VERSION 5.7 ;
  NOWIREEXTENSIONATPIN ON ;
  DIVIDERCHAR "/" ;
  BUSBITCHARS "[]" ;
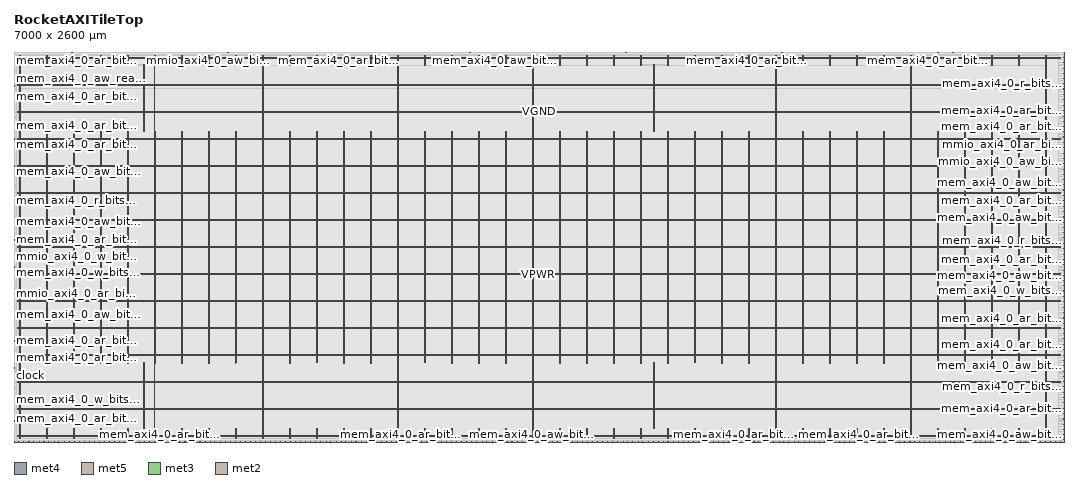
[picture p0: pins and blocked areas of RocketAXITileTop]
MACRO RocketAXITileTop
  CLASS BLOCK ;
  FOREIGN RocketAXITileTop ;
  ORIGIN 0.000 0.000 ;
  SIZE 7000.000 BY 2600.000 ;
  PIN VGND
    DIRECTION INOUT ;
    USE GROUND ;
    PORT
      LAYER met4 ;
        RECT 39.060 21.520 40.660 2578.800 ;
    END
    PORT
      LAYER met4 ;
        RECT 219.060 21.520 220.660 90.020 ;
    END
    PORT
      LAYER met4 ;
        RECT 219.060 527.140 220.660 2072.400 ;
    END
    PORT
      LAYER met4 ;
        RECT 219.060 2509.520 220.660 2578.800 ;
    END
    PORT
      LAYER met4 ;
        RECT 399.060 21.520 400.660 90.020 ;
    END
    PORT
      LAYER met4 ;
        RECT 399.060 526.520 400.660 2073.020 ;
    END
    PORT
      LAYER met4 ;
        RECT 399.060 2509.520 400.660 2578.800 ;
    END
    PORT
      LAYER met4 ;
        RECT 579.060 21.520 580.660 89.400 ;
    END
    PORT
      LAYER met4 ;
        RECT 579.060 527.140 580.660 2072.400 ;
    END
    PORT
      LAYER met4 ;
        RECT 579.060 2510.140 580.660 2578.800 ;
    END
    PORT
      LAYER met4 ;
        RECT 759.060 21.520 760.660 90.020 ;
    END
    PORT
      LAYER met4 ;
        RECT 759.060 526.520 760.660 2073.020 ;
    END
    PORT
      LAYER met4 ;
        RECT 759.060 2509.520 760.660 2578.800 ;
    END
    PORT
      LAYER met4 ;
        RECT 939.060 21.520 940.660 90.020 ;
    END
    PORT
      LAYER met4 ;
        RECT 939.060 526.520 940.660 2073.020 ;
    END
    PORT
      LAYER met4 ;
        RECT 939.060 2509.520 940.660 2578.800 ;
    END
    PORT
      LAYER met4 ;
        RECT 1119.060 21.520 1120.660 90.020 ;
    END
    PORT
      LAYER met4 ;
        RECT 1119.060 526.520 1120.660 2073.020 ;
    END
    PORT
      LAYER met4 ;
        RECT 1119.060 2509.520 1120.660 2578.800 ;
    END
    PORT
      LAYER met4 ;
        RECT 1299.060 21.520 1300.660 90.020 ;
    END
    PORT
      LAYER met4 ;
        RECT 1299.060 526.520 1300.660 2073.020 ;
    END
    PORT
      LAYER met4 ;
        RECT 1299.060 2509.520 1300.660 2578.800 ;
    END
    PORT
      LAYER met4 ;
        RECT 1479.060 21.520 1480.660 89.400 ;
    END
    PORT
      LAYER met4 ;
        RECT 1479.060 527.140 1480.660 2072.400 ;
    END
    PORT
      LAYER met4 ;
        RECT 1479.060 2510.140 1480.660 2578.800 ;
    END
    PORT
      LAYER met4 ;
        RECT 1659.060 21.520 1660.660 2578.800 ;
    END
    PORT
      LAYER met4 ;
        RECT 1839.060 21.520 1840.660 90.020 ;
    END
    PORT
      LAYER met4 ;
        RECT 1839.060 526.520 1840.660 2073.020 ;
    END
    PORT
      LAYER met4 ;
        RECT 1839.060 2509.520 1840.660 2578.800 ;
    END
    PORT
      LAYER met4 ;
        RECT 2019.060 21.520 2020.660 90.020 ;
    END
    PORT
      LAYER met4 ;
        RECT 2019.060 527.140 2020.660 2072.400 ;
    END
    PORT
      LAYER met4 ;
        RECT 2019.060 2509.520 2020.660 2578.800 ;
    END
    PORT
      LAYER met4 ;
        RECT 2199.060 21.520 2200.660 90.020 ;
    END
    PORT
      LAYER met4 ;
        RECT 2199.060 526.520 2200.660 2073.020 ;
    END
    PORT
      LAYER met4 ;
        RECT 2199.060 2509.520 2200.660 2578.800 ;
    END
    PORT
      LAYER met4 ;
        RECT 2379.060 21.520 2380.660 90.020 ;
    END
    PORT
      LAYER met4 ;
        RECT 2379.060 526.520 2380.660 2073.020 ;
    END
    PORT
      LAYER met4 ;
        RECT 2379.060 2509.520 2380.660 2578.800 ;
    END
    PORT
      LAYER met4 ;
        RECT 2559.060 21.520 2560.660 2578.800 ;
    END
    PORT
      LAYER met4 ;
        RECT 2739.060 21.520 2740.660 90.020 ;
    END
    PORT
      LAYER met4 ;
        RECT 2739.060 527.140 2740.660 2072.400 ;
    END
    PORT
      LAYER met4 ;
        RECT 2739.060 2509.520 2740.660 2578.800 ;
    END
    PORT
      LAYER met4 ;
        RECT 2919.060 21.520 2920.660 90.020 ;
    END
    PORT
      LAYER met4 ;
        RECT 2919.060 526.520 2920.660 2073.020 ;
    END
    PORT
      LAYER met4 ;
        RECT 2919.060 2509.520 2920.660 2578.800 ;
    END
    PORT
      LAYER met4 ;
        RECT 3099.060 21.520 3100.660 90.020 ;
    END
    PORT
      LAYER met4 ;
        RECT 3099.060 526.520 3100.660 2073.020 ;
    END
    PORT
      LAYER met4 ;
        RECT 3099.060 2509.520 3100.660 2578.800 ;
    END
    PORT
      LAYER met4 ;
        RECT 3279.060 21.520 3280.660 90.020 ;
    END
    PORT
      LAYER met4 ;
        RECT 3279.060 526.520 3280.660 2073.020 ;
    END
    PORT
      LAYER met4 ;
        RECT 3279.060 2509.520 3280.660 2578.800 ;
    END
    PORT
      LAYER met4 ;
        RECT 3459.060 21.520 3460.660 2578.800 ;
    END
    PORT
      LAYER met4 ;
        RECT 3639.060 21.520 3640.660 90.020 ;
    END
    PORT
      LAYER met4 ;
        RECT 3639.060 526.520 3640.660 2073.020 ;
    END
    PORT
      LAYER met4 ;
        RECT 3639.060 2509.520 3640.660 2578.800 ;
    END
    PORT
      LAYER met4 ;
        RECT 3819.060 21.520 3820.660 89.400 ;
    END
    PORT
      LAYER met4 ;
        RECT 3819.060 526.520 3820.660 2073.020 ;
    END
    PORT
      LAYER met4 ;
        RECT 3819.060 2510.140 3820.660 2578.800 ;
    END
    PORT
      LAYER met4 ;
        RECT 3999.060 21.520 4000.660 90.020 ;
    END
    PORT
      LAYER met4 ;
        RECT 3999.060 526.520 4000.660 2073.020 ;
    END
    PORT
      LAYER met4 ;
        RECT 3999.060 2509.520 4000.660 2578.800 ;
    END
    PORT
      LAYER met4 ;
        RECT 4179.060 21.520 4180.660 90.020 ;
    END
    PORT
      LAYER met4 ;
        RECT 4179.060 526.520 4180.660 2073.020 ;
    END
    PORT
      LAYER met4 ;
        RECT 4179.060 2509.520 4180.660 2578.800 ;
    END
    PORT
      LAYER met4 ;
        RECT 4359.060 21.520 4360.660 90.020 ;
    END
    PORT
      LAYER met4 ;
        RECT 4359.060 526.520 4360.660 2073.020 ;
    END
    PORT
      LAYER met4 ;
        RECT 4359.060 2509.520 4360.660 2578.800 ;
    END
    PORT
      LAYER met4 ;
        RECT 4539.060 21.520 4540.660 90.020 ;
    END
    PORT
      LAYER met4 ;
        RECT 4539.060 527.140 4540.660 2072.400 ;
    END
    PORT
      LAYER met4 ;
        RECT 4539.060 2509.520 4540.660 2578.800 ;
    END
    PORT
      LAYER met4 ;
        RECT 4719.060 21.520 4720.660 90.020 ;
    END
    PORT
      LAYER met4 ;
        RECT 4719.060 526.520 4720.660 2073.020 ;
    END
    PORT
      LAYER met4 ;
        RECT 4719.060 2509.520 4720.660 2578.800 ;
    END
    PORT
      LAYER met4 ;
        RECT 4899.060 21.520 4900.660 90.020 ;
    END
    PORT
      LAYER met4 ;
        RECT 4899.060 526.520 4900.660 2073.020 ;
    END
    PORT
      LAYER met4 ;
        RECT 4899.060 2509.520 4900.660 2578.800 ;
    END
    PORT
      LAYER met4 ;
        RECT 5079.060 21.520 5080.660 2578.800 ;
    END
    PORT
      LAYER met4 ;
        RECT 5259.060 21.520 5260.660 90.020 ;
    END
    PORT
      LAYER met4 ;
        RECT 5259.060 526.520 5260.660 2073.020 ;
    END
    PORT
      LAYER met4 ;
        RECT 5259.060 2509.520 5260.660 2578.800 ;
    END
    PORT
      LAYER met4 ;
        RECT 5439.060 21.520 5440.660 90.020 ;
    END
    PORT
      LAYER met4 ;
        RECT 5439.060 526.520 5440.660 2073.020 ;
    END
    PORT
      LAYER met4 ;
        RECT 5439.060 2509.520 5440.660 2578.800 ;
    END
    PORT
      LAYER met4 ;
        RECT 5619.060 21.520 5620.660 90.020 ;
    END
    PORT
      LAYER met4 ;
        RECT 5619.060 526.520 5620.660 2073.020 ;
    END
    PORT
      LAYER met4 ;
        RECT 5619.060 2509.520 5620.660 2578.800 ;
    END
    PORT
      LAYER met4 ;
        RECT 5799.060 21.520 5800.660 89.400 ;
    END
    PORT
      LAYER met4 ;
        RECT 5799.060 526.520 5800.660 2073.020 ;
    END
    PORT
      LAYER met4 ;
        RECT 5799.060 2510.140 5800.660 2578.800 ;
    END
    PORT
      LAYER met4 ;
        RECT 5979.060 21.520 5980.660 2578.800 ;
    END
    PORT
      LAYER met4 ;
        RECT 6159.060 21.520 6160.660 90.020 ;
    END
    PORT
      LAYER met4 ;
        RECT 6159.060 527.140 6160.660 2072.400 ;
    END
    PORT
      LAYER met4 ;
        RECT 6159.060 2509.520 6160.660 2578.800 ;
    END
    PORT
      LAYER met4 ;
        RECT 6339.060 21.520 6340.660 90.020 ;
    END
    PORT
      LAYER met4 ;
        RECT 6339.060 527.140 6340.660 2072.400 ;
    END
    PORT
      LAYER met4 ;
        RECT 6339.060 2509.520 6340.660 2578.800 ;
    END
    PORT
      LAYER met4 ;
        RECT 6519.060 21.520 6520.660 90.020 ;
    END
    PORT
      LAYER met4 ;
        RECT 6519.060 526.520 6520.660 2073.020 ;
    END
    PORT
      LAYER met4 ;
        RECT 6519.060 2509.520 6520.660 2578.800 ;
    END
    PORT
      LAYER met4 ;
        RECT 6699.060 21.520 6700.660 90.020 ;
    END
    PORT
      LAYER met4 ;
        RECT 6699.060 526.520 6700.660 2073.020 ;
    END
    PORT
      LAYER met4 ;
        RECT 6699.060 2509.520 6700.660 2578.800 ;
    END
    PORT
      LAYER met4 ;
        RECT 6879.060 21.520 6880.660 2578.800 ;
    END
    PORT
      LAYER met5 ;
        RECT 20.000 40.910 6979.820 42.510 ;
    END
    PORT
      LAYER met5 ;
        RECT 20.000 220.910 6979.820 222.510 ;
    END
    PORT
      LAYER met5 ;
        RECT 20.000 400.910 6979.820 402.510 ;
    END
    PORT
      LAYER met5 ;
        RECT 20.000 580.910 6979.820 582.510 ;
    END
    PORT
      LAYER met5 ;
        RECT 20.000 760.910 6979.820 762.510 ;
    END
    PORT
      LAYER met5 ;
        RECT 20.000 940.910 6979.820 942.510 ;
    END
    PORT
      LAYER met5 ;
        RECT 20.000 1120.910 6979.820 1122.510 ;
    END
    PORT
      LAYER met5 ;
        RECT 20.000 1300.910 6979.820 1302.510 ;
    END
    PORT
      LAYER met5 ;
        RECT 20.000 1480.910 6979.820 1482.510 ;
    END
    PORT
      LAYER met5 ;
        RECT 20.000 1660.910 6979.820 1662.510 ;
    END
    PORT
      LAYER met5 ;
        RECT 20.000 1840.910 6979.820 1842.510 ;
    END
    PORT
      LAYER met5 ;
        RECT 20.000 2020.910 6979.820 2022.510 ;
    END
    PORT
      LAYER met5 ;
        RECT 20.000 2200.910 6979.820 2202.510 ;
    END
    PORT
      LAYER met5 ;
        RECT 20.000 2380.910 6979.820 2382.510 ;
    END
    PORT
      LAYER met5 ;
        RECT 20.000 2560.910 6979.820 2562.510 ;
    END
    PORT
      LAYER met4 ;
        RECT 865.380 86.800 866.980 527.920 ;
    END
    PORT
      LAYER met4 ;
        RECT 4267.540 2069.680 4269.140 2513.520 ;
    END
    PORT
      LAYER met4 ;
        RECT 865.380 2072.400 866.980 2513.520 ;
    END
    PORT
      LAYER met4 ;
        RECT 4267.540 86.800 4269.140 530.640 ;
    END
  END VGND
  PIN VPWR
    DIRECTION INOUT ;
    USE POWER ;
    PORT
      LAYER met4 ;
        RECT 35.760 21.520 37.360 2578.800 ;
    END
    PORT
      LAYER met4 ;
        RECT 215.760 21.520 217.360 90.020 ;
    END
    PORT
      LAYER met4 ;
        RECT 215.760 527.140 217.360 2072.400 ;
    END
    PORT
      LAYER met4 ;
        RECT 215.760 2509.520 217.360 2578.800 ;
    END
    PORT
      LAYER met4 ;
        RECT 395.760 21.520 397.360 90.020 ;
    END
    PORT
      LAYER met4 ;
        RECT 395.760 527.140 397.360 2072.400 ;
    END
    PORT
      LAYER met4 ;
        RECT 395.760 2509.520 397.360 2578.800 ;
    END
    PORT
      LAYER met4 ;
        RECT 575.760 21.520 577.360 90.020 ;
    END
    PORT
      LAYER met4 ;
        RECT 575.760 526.520 577.360 2073.020 ;
    END
    PORT
      LAYER met4 ;
        RECT 575.760 2509.520 577.360 2578.800 ;
    END
    PORT
      LAYER met4 ;
        RECT 755.760 21.520 757.360 90.020 ;
    END
    PORT
      LAYER met4 ;
        RECT 755.760 526.520 757.360 2073.020 ;
    END
    PORT
      LAYER met4 ;
        RECT 755.760 2509.520 757.360 2578.800 ;
    END
    PORT
      LAYER met4 ;
        RECT 935.760 21.520 937.360 2578.800 ;
    END
    PORT
      LAYER met4 ;
        RECT 1115.760 21.520 1117.360 89.400 ;
    END
    PORT
      LAYER met4 ;
        RECT 1115.760 527.140 1117.360 2072.400 ;
    END
    PORT
      LAYER met4 ;
        RECT 1115.760 2510.140 1117.360 2578.800 ;
    END
    PORT
      LAYER met4 ;
        RECT 1295.760 21.520 1297.360 90.020 ;
    END
    PORT
      LAYER met4 ;
        RECT 1295.760 526.520 1297.360 2073.020 ;
    END
    PORT
      LAYER met4 ;
        RECT 1295.760 2509.520 1297.360 2578.800 ;
    END
    PORT
      LAYER met4 ;
        RECT 1475.760 21.520 1477.360 90.020 ;
    END
    PORT
      LAYER met4 ;
        RECT 1475.760 526.520 1477.360 2073.020 ;
    END
    PORT
      LAYER met4 ;
        RECT 1475.760 2509.520 1477.360 2578.800 ;
    END
    PORT
      LAYER met4 ;
        RECT 1655.760 21.520 1657.360 2578.800 ;
    END
    PORT
      LAYER met4 ;
        RECT 1835.760 21.520 1837.360 90.020 ;
    END
    PORT
      LAYER met4 ;
        RECT 1835.760 526.520 1837.360 2073.020 ;
    END
    PORT
      LAYER met4 ;
        RECT 1835.760 2509.520 1837.360 2578.800 ;
    END
    PORT
      LAYER met4 ;
        RECT 2015.760 21.520 2017.360 89.400 ;
    END
    PORT
      LAYER met4 ;
        RECT 2015.760 527.140 2017.360 2072.400 ;
    END
    PORT
      LAYER met4 ;
        RECT 2015.760 2510.140 2017.360 2578.800 ;
    END
    PORT
      LAYER met4 ;
        RECT 2195.760 21.520 2197.360 90.020 ;
    END
    PORT
      LAYER met4 ;
        RECT 2195.760 526.520 2197.360 2073.020 ;
    END
    PORT
      LAYER met4 ;
        RECT 2195.760 2509.520 2197.360 2578.800 ;
    END
    PORT
      LAYER met4 ;
        RECT 2375.760 21.520 2377.360 90.020 ;
    END
    PORT
      LAYER met4 ;
        RECT 2375.760 526.520 2377.360 2073.020 ;
    END
    PORT
      LAYER met4 ;
        RECT 2375.760 2509.520 2377.360 2578.800 ;
    END
    PORT
      LAYER met4 ;
        RECT 2555.760 21.520 2557.360 2578.800 ;
    END
    PORT
      LAYER met4 ;
        RECT 2735.760 21.520 2737.360 90.020 ;
    END
    PORT
      LAYER met4 ;
        RECT 2735.760 527.140 2737.360 2072.400 ;
    END
    PORT
      LAYER met4 ;
        RECT 2735.760 2509.520 2737.360 2578.800 ;
    END
    PORT
      LAYER met4 ;
        RECT 2915.760 21.520 2917.360 89.400 ;
    END
    PORT
      LAYER met4 ;
        RECT 2915.760 527.140 2917.360 2072.400 ;
    END
    PORT
      LAYER met4 ;
        RECT 2915.760 2510.140 2917.360 2578.800 ;
    END
    PORT
      LAYER met4 ;
        RECT 3095.760 21.520 3097.360 90.020 ;
    END
    PORT
      LAYER met4 ;
        RECT 3095.760 526.520 3097.360 2073.020 ;
    END
    PORT
      LAYER met4 ;
        RECT 3095.760 2509.520 3097.360 2578.800 ;
    END
    PORT
      LAYER met4 ;
        RECT 3275.760 21.520 3277.360 90.020 ;
    END
    PORT
      LAYER met4 ;
        RECT 3275.760 526.520 3277.360 2073.020 ;
    END
    PORT
      LAYER met4 ;
        RECT 3275.760 2509.520 3277.360 2578.800 ;
    END
    PORT
      LAYER met4 ;
        RECT 3455.760 21.520 3457.360 2578.800 ;
    END
    PORT
      LAYER met4 ;
        RECT 3635.760 21.520 3637.360 90.020 ;
    END
    PORT
      LAYER met4 ;
        RECT 3635.760 526.520 3637.360 2073.020 ;
    END
    PORT
      LAYER met4 ;
        RECT 3635.760 2509.520 3637.360 2578.800 ;
    END
    PORT
      LAYER met4 ;
        RECT 3815.760 21.520 3817.360 90.020 ;
    END
    PORT
      LAYER met4 ;
        RECT 3815.760 527.140 3817.360 2072.400 ;
    END
    PORT
      LAYER met4 ;
        RECT 3815.760 2509.520 3817.360 2578.800 ;
    END
    PORT
      LAYER met4 ;
        RECT 3995.760 21.520 3997.360 90.020 ;
    END
    PORT
      LAYER met4 ;
        RECT 3995.760 526.520 3997.360 2073.020 ;
    END
    PORT
      LAYER met4 ;
        RECT 3995.760 2509.520 3997.360 2578.800 ;
    END
    PORT
      LAYER met4 ;
        RECT 4175.760 21.520 4177.360 90.020 ;
    END
    PORT
      LAYER met4 ;
        RECT 4175.760 526.520 4177.360 2073.020 ;
    END
    PORT
      LAYER met4 ;
        RECT 4175.760 2509.520 4177.360 2578.800 ;
    END
    PORT
      LAYER met4 ;
        RECT 4355.760 21.520 4357.360 90.020 ;
    END
    PORT
      LAYER met4 ;
        RECT 4355.760 526.520 4357.360 2073.020 ;
    END
    PORT
      LAYER met4 ;
        RECT 4355.760 2509.520 4357.360 2578.800 ;
    END
    PORT
      LAYER met4 ;
        RECT 4535.760 21.520 4537.360 90.020 ;
    END
    PORT
      LAYER met4 ;
        RECT 4535.760 527.140 4537.360 2072.400 ;
    END
    PORT
      LAYER met4 ;
        RECT 4535.760 2509.520 4537.360 2578.800 ;
    END
    PORT
      LAYER met4 ;
        RECT 4715.760 21.520 4717.360 89.400 ;
    END
    PORT
      LAYER met4 ;
        RECT 4715.760 527.140 4717.360 2072.400 ;
    END
    PORT
      LAYER met4 ;
        RECT 4715.760 2510.140 4717.360 2578.800 ;
    END
    PORT
      LAYER met4 ;
        RECT 4895.760 21.520 4897.360 90.020 ;
    END
    PORT
      LAYER met4 ;
        RECT 4895.760 526.520 4897.360 2073.020 ;
    END
    PORT
      LAYER met4 ;
        RECT 4895.760 2509.520 4897.360 2578.800 ;
    END
    PORT
      LAYER met4 ;
        RECT 5075.760 21.520 5077.360 2578.800 ;
    END
    PORT
      LAYER met4 ;
        RECT 5255.760 21.520 5257.360 90.020 ;
    END
    PORT
      LAYER met4 ;
        RECT 5255.760 526.520 5257.360 2073.020 ;
    END
    PORT
      LAYER met4 ;
        RECT 5255.760 2509.520 5257.360 2578.800 ;
    END
    PORT
      LAYER met4 ;
        RECT 5435.760 21.520 5437.360 90.020 ;
    END
    PORT
      LAYER met4 ;
        RECT 5435.760 526.520 5437.360 2073.020 ;
    END
    PORT
      LAYER met4 ;
        RECT 5435.760 2509.520 5437.360 2578.800 ;
    END
    PORT
      LAYER met4 ;
        RECT 5615.760 21.520 5617.360 89.400 ;
    END
    PORT
      LAYER met4 ;
        RECT 5615.760 527.140 5617.360 2072.400 ;
    END
    PORT
      LAYER met4 ;
        RECT 5615.760 2510.140 5617.360 2578.800 ;
    END
    PORT
      LAYER met4 ;
        RECT 5795.760 21.520 5797.360 90.020 ;
    END
    PORT
      LAYER met4 ;
        RECT 5795.760 526.520 5797.360 2073.020 ;
    END
    PORT
      LAYER met4 ;
        RECT 5795.760 2509.520 5797.360 2578.800 ;
    END
    PORT
      LAYER met4 ;
        RECT 5975.760 21.520 5977.360 2578.800 ;
    END
    PORT
      LAYER met4 ;
        RECT 6155.760 21.520 6157.360 90.020 ;
    END
    PORT
      LAYER met4 ;
        RECT 6155.760 526.520 6157.360 2073.020 ;
    END
    PORT
      LAYER met4 ;
        RECT 6155.760 2509.520 6157.360 2578.800 ;
    END
    PORT
      LAYER met4 ;
        RECT 6335.760 21.520 6337.360 90.020 ;
    END
    PORT
      LAYER met4 ;
        RECT 6335.760 527.140 6337.360 2072.400 ;
    END
    PORT
      LAYER met4 ;
        RECT 6335.760 2509.520 6337.360 2578.800 ;
    END
    PORT
      LAYER met4 ;
        RECT 6515.760 21.520 6517.360 89.400 ;
    END
    PORT
      LAYER met4 ;
        RECT 6515.760 527.140 6517.360 2072.400 ;
    END
    PORT
      LAYER met4 ;
        RECT 6515.760 2510.140 6517.360 2578.800 ;
    END
    PORT
      LAYER met4 ;
        RECT 6695.760 21.520 6697.360 90.020 ;
    END
    PORT
      LAYER met4 ;
        RECT 6695.760 526.520 6697.360 2073.020 ;
    END
    PORT
      LAYER met4 ;
        RECT 6695.760 2509.520 6697.360 2578.800 ;
    END
    PORT
      LAYER met4 ;
        RECT 6875.760 21.520 6877.360 2578.800 ;
    END
    PORT
      LAYER met5 ;
        RECT 20.000 37.610 6979.820 39.210 ;
    END
    PORT
      LAYER met5 ;
        RECT 20.000 217.610 6979.820 219.210 ;
    END
    PORT
      LAYER met5 ;
        RECT 20.000 397.610 6979.820 399.210 ;
    END
    PORT
      LAYER met5 ;
        RECT 20.000 577.610 6979.820 579.210 ;
    END
    PORT
      LAYER met5 ;
        RECT 20.000 757.610 6979.820 759.210 ;
    END
    PORT
      LAYER met5 ;
        RECT 20.000 937.610 6979.820 939.210 ;
    END
    PORT
      LAYER met5 ;
        RECT 20.000 1117.610 6979.820 1119.210 ;
    END
    PORT
      LAYER met5 ;
        RECT 20.000 1297.610 6979.820 1299.210 ;
    END
    PORT
      LAYER met5 ;
        RECT 20.000 1477.610 6979.820 1479.210 ;
    END
    PORT
      LAYER met5 ;
        RECT 20.000 1657.610 6979.820 1659.210 ;
    END
    PORT
      LAYER met5 ;
        RECT 20.000 1837.610 6979.820 1839.210 ;
    END
    PORT
      LAYER met5 ;
        RECT 20.000 2017.610 6979.820 2019.210 ;
    END
    PORT
      LAYER met5 ;
        RECT 20.000 2197.610 6979.820 2199.210 ;
    END
    PORT
      LAYER met5 ;
        RECT 20.000 2377.610 6979.820 2379.210 ;
    END
    PORT
      LAYER met5 ;
        RECT 20.000 2557.610 6979.820 2559.210 ;
    END
    PORT
      LAYER met4 ;
        RECT 4263.860 2069.680 4265.460 2513.520 ;
    END
    PORT
      LAYER met4 ;
        RECT 4263.860 86.800 4265.460 530.640 ;
    END
  END VPWR
  PIN clock
    DIRECTION INPUT ;
    USE SIGNAL ;
    ANTENNAGATEAREA 1.286700 ;
    ANTENNADIFFAREA 0.434700 ;
    PORT
      LAYER met3 ;
        RECT 0.000 493.040 4.000 493.640 ;
    END
  END clock
  PIN mem_axi4_0_ar_bits_addr[0]
    DIRECTION OUTPUT TRISTATE ;
    USE SIGNAL ;
    ANTENNADIFFAREA 0.795200 ;
    PORT
      LAYER met2 ;
        RECT 4179.650 2596.000 4179.930 2600.000 ;
    END
  END mem_axi4_0_ar_bits_addr[0]
  PIN mem_axi4_0_ar_bits_addr[10]
    DIRECTION OUTPUT TRISTATE ;
    USE SIGNAL ;
    ANTENNADIFFAREA 0.795200 ;
    PORT
      LAYER met2 ;
        RECT 2550.330 0.000 2550.610 4.000 ;
    END
  END mem_axi4_0_ar_bits_addr[10]
  PIN mem_axi4_0_ar_bits_addr[11]
    DIRECTION OUTPUT TRISTATE ;
    USE SIGNAL ;
    ANTENNADIFFAREA 0.795200 ;
    PORT
      LAYER met2 ;
        RECT 4514.530 2596.000 4514.810 2600.000 ;
    END
  END mem_axi4_0_ar_bits_addr[11]
  PIN mem_axi4_0_ar_bits_addr[12]
    DIRECTION OUTPUT TRISTATE ;
    USE SIGNAL ;
    ANTENNADIFFAREA 0.795200 ;
    PORT
      LAYER met3 ;
        RECT 0.000 1346.440 4.000 1347.040 ;
    END
  END mem_axi4_0_ar_bits_addr[12]
  PIN mem_axi4_0_ar_bits_addr[13]
    DIRECTION OUTPUT TRISTATE ;
    USE SIGNAL ;
    ANTENNADIFFAREA 0.795200 ;
    PORT
      LAYER met3 ;
        RECT 6996.000 2104.640 7000.000 2105.240 ;
    END
  END mem_axi4_0_ar_bits_addr[13]
  PIN mem_axi4_0_ar_bits_addr[14]
    DIRECTION OUTPUT TRISTATE ;
    USE SIGNAL ;
    ANTENNADIFFAREA 0.795200 ;
    PORT
      LAYER met3 ;
        RECT 0.000 68.040 4.000 68.640 ;
    END
  END mem_axi4_0_ar_bits_addr[14]
  PIN mem_axi4_0_ar_bits_addr[15]
    DIRECTION OUTPUT TRISTATE ;
    USE SIGNAL ;
    ANTENNADIFFAREA 0.795200 ;
    PORT
      LAYER met3 ;
        RECT 0.000 2301.840 4.000 2302.440 ;
    END
  END mem_axi4_0_ar_bits_addr[15]
  PIN mem_axi4_0_ar_bits_addr[16]
    DIRECTION OUTPUT TRISTATE ;
    USE SIGNAL ;
    ANTENNADIFFAREA 0.795200 ;
    PORT
      LAYER met2 ;
        RECT 4884.830 2596.000 4885.110 2600.000 ;
    END
  END mem_axi4_0_ar_bits_addr[16]
  PIN mem_axi4_0_ar_bits_addr[17]
    DIRECTION OUTPUT TRISTATE ;
    USE SIGNAL ;
    ANTENNADIFFAREA 0.795200 ;
    PORT
      LAYER met2 ;
        RECT 2167.150 2596.000 2167.430 2600.000 ;
    END
  END mem_axi4_0_ar_bits_addr[17]
  PIN mem_axi4_0_ar_bits_addr[18]
    DIRECTION OUTPUT TRISTATE ;
    USE SIGNAL ;
    ANTENNADIFFAREA 0.795200 ;
    PORT
      LAYER met3 ;
        RECT 6996.000 1217.240 7000.000 1217.840 ;
    END
  END mem_axi4_0_ar_bits_addr[18]
  PIN mem_axi4_0_ar_bits_addr[19]
    DIRECTION OUTPUT TRISTATE ;
    USE SIGNAL ;
    ANTENNADIFFAREA 0.795200 ;
    PORT
      LAYER met3 ;
        RECT 6996.000 826.240 7000.000 826.840 ;
    END
  END mem_axi4_0_ar_bits_addr[19]
  PIN mem_axi4_0_ar_bits_addr[1]
    DIRECTION OUTPUT TRISTATE ;
    USE SIGNAL ;
    ANTENNADIFFAREA 0.795200 ;
    PORT
      LAYER met3 ;
        RECT 0.000 353.640 4.000 354.240 ;
    END
  END mem_axi4_0_ar_bits_addr[1]
  PIN mem_axi4_0_ar_bits_addr[20]
    DIRECTION OUTPUT TRISTATE ;
    USE SIGNAL ;
    ANTENNADIFFAREA 0.795200 ;
    PORT
      LAYER met2 ;
        RECT 3677.330 2596.000 3677.610 2600.000 ;
    END
  END mem_axi4_0_ar_bits_addr[20]
  PIN mem_axi4_0_ar_bits_addr[21]
    DIRECTION OUTPUT TRISTATE ;
    USE SIGNAL ;
    ANTENNADIFFAREA 0.795200 ;
    PORT
      LAYER met2 ;
        RECT 3574.290 2596.000 3574.570 2600.000 ;
    END
  END mem_axi4_0_ar_bits_addr[21]
  PIN mem_axi4_0_ar_bits_addr[22]
    DIRECTION OUTPUT TRISTATE ;
    USE SIGNAL ;
    ANTENNADIFFAREA 0.795200 ;
    PORT
      LAYER met2 ;
        RECT 6092.330 2596.000 6092.610 2600.000 ;
    END
  END mem_axi4_0_ar_bits_addr[22]
  PIN mem_axi4_0_ar_bits_addr[23]
    DIRECTION OUTPUT TRISTATE ;
    USE SIGNAL ;
    ANTENNADIFFAREA 0.795200 ;
    PORT
      LAYER met3 ;
        RECT 6996.000 261.840 7000.000 262.440 ;
    END
  END mem_axi4_0_ar_bits_addr[23]
  PIN mem_axi4_0_ar_bits_addr[24]
    DIRECTION OUTPUT TRISTATE ;
    USE SIGNAL ;
    ANTENNADIFFAREA 0.795200 ;
    PORT
      LAYER met2 ;
        RECT 386.490 2596.000 386.770 2600.000 ;
    END
  END mem_axi4_0_ar_bits_addr[24]
  PIN mem_axi4_0_ar_bits_addr[25]
    DIRECTION OUTPUT TRISTATE ;
    USE SIGNAL ;
    ANTENNADIFFAREA 0.795200 ;
    PORT
      LAYER met3 ;
        RECT 0.000 673.240 4.000 673.840 ;
    END
  END mem_axi4_0_ar_bits_addr[25]
  PIN mem_axi4_0_ar_bits_addr[26]
    DIRECTION OUTPUT TRISTATE ;
    USE SIGNAL ;
    ANTENNADIFFAREA 0.795200 ;
    PORT
      LAYER met2 ;
        RECT 972.530 0.000 972.810 4.000 ;
    END
  END mem_axi4_0_ar_bits_addr[26]
  PIN mem_axi4_0_ar_bits_addr[27]
    DIRECTION OUTPUT TRISTATE ;
    USE SIGNAL ;
    ANTENNADIFFAREA 0.795200 ;
    PORT
      LAYER met2 ;
        RECT 4797.890 0.000 4798.170 4.000 ;
    END
  END mem_axi4_0_ar_bits_addr[27]
  PIN mem_axi4_0_ar_bits_addr[28]
    DIRECTION OUTPUT TRISTATE ;
    USE SIGNAL ;
    ANTENNADIFFAREA 0.795200 ;
    PORT
      LAYER met3 ;
        RECT 0.000 564.440 4.000 565.040 ;
    END
  END mem_axi4_0_ar_bits_addr[28]
  PIN mem_axi4_0_ar_bits_addr[29]
    DIRECTION OUTPUT TRISTATE ;
    USE SIGNAL ;
    ANTENNADIFFAREA 0.795200 ;
    PORT
      LAYER met2 ;
        RECT 3107.390 2596.000 3107.670 2600.000 ;
    END
  END mem_axi4_0_ar_bits_addr[29]
  PIN mem_axi4_0_ar_bits_addr[2]
    DIRECTION OUTPUT TRISTATE ;
    USE SIGNAL ;
    ANTENNADIFFAREA 0.795200 ;
    PORT
      LAYER met3 ;
        RECT 0.000 210.840 4.000 211.440 ;
    END
  END mem_axi4_0_ar_bits_addr[2]
  PIN mem_axi4_0_ar_bits_addr[30]
    DIRECTION OUTPUT TRISTATE ;
    USE SIGNAL ;
    ANTENNADIFFAREA 0.795200 ;
    PORT
      LAYER met3 ;
        RECT 0.000 2373.240 4.000 2373.840 ;
    END
  END mem_axi4_0_ar_bits_addr[30]
  PIN mem_axi4_0_ar_bits_addr[31]
    DIRECTION OUTPUT TRISTATE ;
    USE SIGNAL ;
    ANTENNADIFFAREA 0.795200 ;
    PORT
      LAYER met2 ;
        RECT 19.410 2596.000 19.690 2600.000 ;
    END
  END mem_axi4_0_ar_bits_addr[31]
  PIN mem_axi4_0_ar_bits_addr[3]
    DIRECTION OUTPUT TRISTATE ;
    USE SIGNAL ;
    ANTENNADIFFAREA 0.795200 ;
    PORT
      LAYER met2 ;
        RECT 4112.030 2596.000 4112.310 2600.000 ;
    END
  END mem_axi4_0_ar_bits_addr[3]
  PIN mem_axi4_0_ar_bits_addr[4]
    DIRECTION OUTPUT TRISTATE ;
    USE SIGNAL ;
    ANTENNADIFFAREA 0.795200 ;
    PORT
      LAYER met3 ;
        RECT 0.000 1876.840 4.000 1877.440 ;
    END
  END mem_axi4_0_ar_bits_addr[4]
  PIN mem_axi4_0_ar_bits_addr[5]
    DIRECTION OUTPUT TRISTATE ;
    USE SIGNAL ;
    ANTENNADIFFAREA 0.795200 ;
    PORT
      LAYER met2 ;
        RECT 4079.830 2596.000 4080.110 2600.000 ;
    END
  END mem_axi4_0_ar_bits_addr[5]
  PIN mem_axi4_0_ar_bits_addr[6]
    DIRECTION OUTPUT TRISTATE ;
    USE SIGNAL ;
    ANTENNADIFFAREA 0.795200 ;
    PORT
      LAYER met2 ;
        RECT 1764.650 2596.000 1764.930 2600.000 ;
    END
  END mem_axi4_0_ar_bits_addr[6]
  PIN mem_axi4_0_ar_bits_addr[7]
    DIRECTION OUTPUT TRISTATE ;
    USE SIGNAL ;
    ANTENNADIFFAREA 0.795200 ;
    PORT
      LAYER met2 ;
        RECT 4314.890 2596.000 4315.170 2600.000 ;
    END
  END mem_axi4_0_ar_bits_addr[7]
  PIN mem_axi4_0_ar_bits_addr[8]
    DIRECTION OUTPUT TRISTATE ;
    USE SIGNAL ;
    ANTENNADIFFAREA 0.795200 ;
    PORT
      LAYER met2 ;
        RECT 6462.630 2596.000 6462.910 2600.000 ;
    END
  END mem_axi4_0_ar_bits_addr[8]
  PIN mem_axi4_0_ar_bits_addr[9]
    DIRECTION OUTPUT TRISTATE ;
    USE SIGNAL ;
    ANTENNADIFFAREA 0.795200 ;
    PORT
      LAYER met2 ;
        RECT 4395.390 0.000 4395.670 4.000 ;
    END
  END mem_axi4_0_ar_bits_addr[9]
  PIN mem_axi4_0_ar_bits_burst[0]
    DIRECTION OUTPUT TRISTATE ;
    USE SIGNAL ;
    PORT
      LAYER met3 ;
        RECT 6996.000 224.440 7000.000 225.040 ;
    END
  END mem_axi4_0_ar_bits_burst[0]
  PIN mem_axi4_0_ar_bits_burst[1]
    DIRECTION OUTPUT TRISTATE ;
    USE SIGNAL ;
    PORT
      LAYER met2 ;
        RECT 3957.470 0.000 3957.750 4.000 ;
    END
  END mem_axi4_0_ar_bits_burst[1]
  PIN mem_axi4_0_ar_bits_cache[0]
    DIRECTION OUTPUT TRISTATE ;
    USE SIGNAL ;
    PORT
      LAYER met3 ;
        RECT 0.000 1982.240 4.000 1982.840 ;
    END
  END mem_axi4_0_ar_bits_cache[0]
  PIN mem_axi4_0_ar_bits_cache[1]
    DIRECTION OUTPUT TRISTATE ;
    USE SIGNAL ;
    PORT
      LAYER met2 ;
        RECT 6964.950 2596.000 6965.230 2600.000 ;
    END
  END mem_axi4_0_ar_bits_cache[1]
  PIN mem_axi4_0_ar_bits_cache[2]
    DIRECTION OUTPUT TRISTATE ;
    USE SIGNAL ;
    PORT
      LAYER met2 ;
        RECT 4549.950 2596.000 4550.230 2600.000 ;
    END
  END mem_axi4_0_ar_bits_cache[2]
  PIN mem_axi4_0_ar_bits_cache[3]
    DIRECTION OUTPUT TRISTATE ;
    USE SIGNAL ;
    PORT
      LAYER met2 ;
        RECT 5635.090 0.000 5635.370 4.000 ;
    END
  END mem_axi4_0_ar_bits_cache[3]
  PIN mem_axi4_0_ar_bits_id[0]
    DIRECTION OUTPUT TRISTATE ;
    USE SIGNAL ;
    PORT
      LAYER met2 ;
        RECT 1259.110 2596.000 1259.390 2600.000 ;
    END
  END mem_axi4_0_ar_bits_id[0]
  PIN mem_axi4_0_ar_bits_id[1]
    DIRECTION OUTPUT TRISTATE ;
    USE SIGNAL ;
    PORT
      LAYER met2 ;
        RECT 892.030 2596.000 892.310 2600.000 ;
    END
  END mem_axi4_0_ar_bits_id[1]
  PIN mem_axi4_0_ar_bits_id[2]
    DIRECTION OUTPUT TRISTATE ;
    USE SIGNAL ;
    PORT
      LAYER met2 ;
        RECT 5503.070 0.000 5503.350 4.000 ;
    END
  END mem_axi4_0_ar_bits_id[2]
  PIN mem_axi4_0_ar_bits_id[3]
    DIRECTION OUTPUT TRISTATE ;
    USE SIGNAL ;
    PORT
      LAYER met2 ;
        RECT 2582.530 0.000 2582.810 4.000 ;
    END
  END mem_axi4_0_ar_bits_id[3]
  PIN mem_axi4_0_ar_bits_len[0]
    DIRECTION OUTPUT TRISTATE ;
    USE SIGNAL ;
    PORT
      LAYER met3 ;
        RECT 0.000 2053.640 4.000 2054.240 ;
    END
  END mem_axi4_0_ar_bits_len[0]
  PIN mem_axi4_0_ar_bits_len[1]
    DIRECTION OUTPUT TRISTATE ;
    USE SIGNAL ;
    PORT
      LAYER met2 ;
        RECT 5020.070 2596.000 5020.350 2600.000 ;
    END
  END mem_axi4_0_ar_bits_len[1]
  PIN mem_axi4_0_ar_bits_len[2]
    DIRECTION OUTPUT TRISTATE ;
    USE SIGNAL ;
    PORT
      LAYER met2 ;
        RECT 4849.410 2596.000 4849.690 2600.000 ;
    END
  END mem_axi4_0_ar_bits_len[2]
  PIN mem_axi4_0_ar_bits_len[3]
    DIRECTION OUTPUT TRISTATE ;
    USE SIGNAL ;
    PORT
      LAYER met2 ;
        RECT 5084.470 2596.000 5084.750 2600.000 ;
    END
  END mem_axi4_0_ar_bits_len[3]
  PIN mem_axi4_0_ar_bits_len[4]
    DIRECTION OUTPUT TRISTATE ;
    USE SIGNAL ;
    PORT
      LAYER met2 ;
        RECT 5367.830 0.000 5368.110 4.000 ;
    END
  END mem_axi4_0_ar_bits_len[4]
  PIN mem_axi4_0_ar_bits_len[5]
    DIRECTION OUTPUT TRISTATE ;
    USE SIGNAL ;
    PORT
      LAYER met2 ;
        RECT 6829.710 2596.000 6829.990 2600.000 ;
    END
  END mem_axi4_0_ar_bits_len[5]
  PIN mem_axi4_0_ar_bits_len[6]
    DIRECTION OUTPUT TRISTATE ;
    USE SIGNAL ;
    PORT
      LAYER met2 ;
        RECT 2669.470 2596.000 2669.750 2600.000 ;
    END
  END mem_axi4_0_ar_bits_len[6]
  PIN mem_axi4_0_ar_bits_len[7]
    DIRECTION OUTPUT TRISTATE ;
    USE SIGNAL ;
    PORT
      LAYER met2 ;
        RECT 6060.130 2596.000 6060.410 2600.000 ;
    END
  END mem_axi4_0_ar_bits_len[7]
  PIN mem_axi4_0_ar_bits_lock
    DIRECTION OUTPUT TRISTATE ;
    USE SIGNAL ;
    PORT
      LAYER met3 ;
        RECT 6996.000 2210.040 7000.000 2210.640 ;
    END
  END mem_axi4_0_ar_bits_lock
  PIN mem_axi4_0_ar_bits_prot[0]
    DIRECTION OUTPUT TRISTATE ;
    USE SIGNAL ;
    PORT
      LAYER met2 ;
        RECT 1809.730 0.000 1810.010 4.000 ;
    END
  END mem_axi4_0_ar_bits_prot[0]
  PIN mem_axi4_0_ar_bits_prot[1]
    DIRECTION OUTPUT TRISTATE ;
    USE SIGNAL ;
    PORT
      LAYER met2 ;
        RECT 5689.830 2596.000 5690.110 2600.000 ;
    END
  END mem_axi4_0_ar_bits_prot[1]
  PIN mem_axi4_0_ar_bits_prot[2]
    DIRECTION OUTPUT TRISTATE ;
    USE SIGNAL ;
    PORT
      LAYER met3 ;
        RECT 6996.000 190.440 7000.000 191.040 ;
    END
  END mem_axi4_0_ar_bits_prot[2]
  PIN mem_axi4_0_ar_bits_qos[0]
    DIRECTION OUTPUT TRISTATE ;
    USE SIGNAL ;
    PORT
      LAYER met3 ;
        RECT 6996.000 649.440 7000.000 650.040 ;
    END
  END mem_axi4_0_ar_bits_qos[0]
  PIN mem_axi4_0_ar_bits_qos[1]
    DIRECTION OUTPUT TRISTATE ;
    USE SIGNAL ;
    PORT
      LAYER met2 ;
        RECT 4414.710 2596.000 4414.990 2600.000 ;
    END
  END mem_axi4_0_ar_bits_qos[1]
  PIN mem_axi4_0_ar_bits_qos[2]
    DIRECTION OUTPUT TRISTATE ;
    USE SIGNAL ;
    PORT
      LAYER met3 ;
        RECT 6996.000 1608.240 7000.000 1608.840 ;
    END
  END mem_axi4_0_ar_bits_qos[2]
  PIN mem_axi4_0_ar_bits_qos[3]
    DIRECTION OUTPUT TRISTATE ;
    USE SIGNAL ;
    PORT
      LAYER met3 ;
        RECT 0.000 2230.440 4.000 2231.040 ;
    END
  END mem_axi4_0_ar_bits_qos[3]
  PIN mem_axi4_0_ar_bits_size[0]
    DIRECTION OUTPUT TRISTATE ;
    USE SIGNAL ;
    ANTENNADIFFAREA 0.795200 ;
    PORT
      LAYER met2 ;
        RECT 354.290 2596.000 354.570 2600.000 ;
    END
  END mem_axi4_0_ar_bits_size[0]
  PIN mem_axi4_0_ar_bits_size[1]
    DIRECTION OUTPUT TRISTATE ;
    USE SIGNAL ;
    ANTENNADIFFAREA 0.795200 ;
    PORT
      LAYER met2 ;
        RECT 1059.470 2596.000 1059.750 2600.000 ;
    END
  END mem_axi4_0_ar_bits_size[1]
  PIN mem_axi4_0_ar_bits_size[2]
    DIRECTION OUTPUT TRISTATE ;
    USE SIGNAL ;
    PORT
      LAYER met2 ;
        RECT 4359.970 0.000 4360.250 4.000 ;
    END
  END mem_axi4_0_ar_bits_size[2]
  PIN mem_axi4_0_ar_ready
    DIRECTION INPUT ;
    USE SIGNAL ;
    ANTENNAGATEAREA 0.426000 ;
    PORT
      LAYER met2 ;
        RECT 637.650 0.000 637.930 4.000 ;
    END
  END mem_axi4_0_ar_ready
  PIN mem_axi4_0_ar_valid
    DIRECTION OUTPUT TRISTATE ;
    USE SIGNAL ;
    ANTENNADIFFAREA 0.795200 ;
    PORT
      LAYER met2 ;
        RECT 2972.150 2596.000 2972.430 2600.000 ;
    END
  END mem_axi4_0_ar_valid
  PIN mem_axi4_0_aw_bits_addr[0]
    DIRECTION OUTPUT TRISTATE ;
    USE SIGNAL ;
    ANTENNADIFFAREA 0.795200 ;
    PORT
      LAYER met2 ;
        RECT 132.110 0.000 132.390 4.000 ;
    END
  END mem_axi4_0_aw_bits_addr[0]
  PIN mem_axi4_0_aw_bits_addr[10]
    DIRECTION OUTPUT TRISTATE ;
    USE SIGNAL ;
    ANTENNADIFFAREA 0.795200 ;
    PORT
      LAYER met2 ;
        RECT 2917.410 0.000 2917.690 4.000 ;
    END
  END mem_axi4_0_aw_bits_addr[10]
  PIN mem_axi4_0_aw_bits_addr[11]
    DIRECTION OUTPUT TRISTATE ;
    USE SIGNAL ;
    ANTENNADIFFAREA 0.795200 ;
    PORT
      LAYER met2 ;
        RECT 3207.210 2596.000 3207.490 2600.000 ;
    END
  END mem_axi4_0_aw_bits_addr[11]
  PIN mem_axi4_0_aw_bits_addr[12]
    DIRECTION OUTPUT TRISTATE ;
    USE SIGNAL ;
    ANTENNADIFFAREA 0.795200 ;
    PORT
      LAYER met2 ;
        RECT 6494.830 2596.000 6495.110 2600.000 ;
    END
  END mem_axi4_0_aw_bits_addr[12]
  PIN mem_axi4_0_aw_bits_addr[13]
    DIRECTION OUTPUT TRISTATE ;
    USE SIGNAL ;
    ANTENNADIFFAREA 0.795200 ;
    PORT
      LAYER met3 ;
        RECT 0.000 1805.440 4.000 1806.040 ;
    END
  END mem_axi4_0_aw_bits_addr[13]
  PIN mem_axi4_0_aw_bits_addr[14]
    DIRECTION OUTPUT TRISTATE ;
    USE SIGNAL ;
    ANTENNADIFFAREA 0.795200 ;
    PORT
      LAYER met2 ;
        RECT 3120.270 0.000 3120.550 4.000 ;
    END
  END mem_axi4_0_aw_bits_addr[14]
  PIN mem_axi4_0_aw_bits_addr[15]
    DIRECTION OUTPUT TRISTATE ;
    USE SIGNAL ;
    ANTENNADIFFAREA 0.795200 ;
    PORT
      LAYER met2 ;
        RECT 3455.150 0.000 3455.430 4.000 ;
    END
  END mem_axi4_0_aw_bits_addr[15]
  PIN mem_axi4_0_aw_bits_addr[16]
    DIRECTION OUTPUT TRISTATE ;
    USE SIGNAL ;
    ANTENNADIFFAREA 0.795200 ;
    PORT
      LAYER met3 ;
        RECT 6996.000 1679.640 7000.000 1680.240 ;
    END
  END mem_axi4_0_aw_bits_addr[16]
  PIN mem_axi4_0_aw_bits_addr[17]
    DIRECTION OUTPUT TRISTATE ;
    USE SIGNAL ;
    ANTENNADIFFAREA 0.795200 ;
    PORT
      LAYER met2 ;
        RECT 4562.830 0.000 4563.110 4.000 ;
    END
  END mem_axi4_0_aw_bits_addr[17]
  PIN mem_axi4_0_aw_bits_addr[18]
    DIRECTION OUTPUT TRISTATE ;
    USE SIGNAL ;
    ANTENNADIFFAREA 0.795200 ;
    PORT
      LAYER met2 ;
        RECT 4617.570 2596.000 4617.850 2600.000 ;
    END
  END mem_axi4_0_aw_bits_addr[18]
  PIN mem_axi4_0_aw_bits_addr[19]
    DIRECTION OUTPUT TRISTATE ;
    USE SIGNAL ;
    ANTENNADIFFAREA 0.795200 ;
    PORT
      LAYER met3 ;
        RECT 6996.000 2563.640 7000.000 2564.240 ;
    END
  END mem_axi4_0_aw_bits_addr[19]
  PIN mem_axi4_0_aw_bits_addr[1]
    DIRECTION OUTPUT TRISTATE ;
    USE SIGNAL ;
    ANTENNADIFFAREA 0.795200 ;
    PORT
      LAYER met3 ;
        RECT 6996.000 1145.840 7000.000 1146.440 ;
    END
  END mem_axi4_0_aw_bits_addr[1]
  PIN mem_axi4_0_aw_bits_addr[20]
    DIRECTION OUTPUT TRISTATE ;
    USE SIGNAL ;
    ANTENNADIFFAREA 0.795200 ;
    PORT
      LAYER met2 ;
        RECT 2299.170 2596.000 2299.450 2600.000 ;
    END
  END mem_axi4_0_aw_bits_addr[20]
  PIN mem_axi4_0_aw_bits_addr[21]
    DIRECTION OUTPUT TRISTATE ;
    USE SIGNAL ;
    ANTENNADIFFAREA 0.795200 ;
    PORT
      LAYER met3 ;
        RECT 6996.000 1183.240 7000.000 1183.840 ;
    END
  END mem_axi4_0_aw_bits_addr[21]
  PIN mem_axi4_0_aw_bits_addr[22]
    DIRECTION OUTPUT TRISTATE ;
    USE SIGNAL ;
    ANTENNADIFFAREA 0.795200 ;
    PORT
      LAYER met2 ;
        RECT 1597.210 2596.000 1597.490 2600.000 ;
    END
  END mem_axi4_0_aw_bits_addr[22]
  PIN mem_axi4_0_aw_bits_addr[23]
    DIRECTION OUTPUT TRISTATE ;
    USE SIGNAL ;
    ANTENNADIFFAREA 0.795200 ;
    PORT
      LAYER met3 ;
        RECT 6996.000 544.040 7000.000 544.640 ;
    END
  END mem_axi4_0_aw_bits_addr[23]
  PIN mem_axi4_0_aw_bits_addr[24]
    DIRECTION OUTPUT TRISTATE ;
    USE SIGNAL ;
    ANTENNADIFFAREA 0.795200 ;
    PORT
      LAYER met2 ;
        RECT 6742.770 0.000 6743.050 4.000 ;
    END
  END mem_axi4_0_aw_bits_addr[24]
  PIN mem_axi4_0_aw_bits_addr[25]
    DIRECTION OUTPUT TRISTATE ;
    USE SIGNAL ;
    ANTENNADIFFAREA 0.795200 ;
    PORT
      LAYER met2 ;
        RECT 3442.270 2596.000 3442.550 2600.000 ;
    END
  END mem_axi4_0_aw_bits_addr[25]
  PIN mem_axi4_0_aw_bits_addr[26]
    DIRECTION OUTPUT TRISTATE ;
    USE SIGNAL ;
    ANTENNADIFFAREA 0.795200 ;
    PORT
      LAYER met2 ;
        RECT 5657.630 2596.000 5657.910 2600.000 ;
    END
  END mem_axi4_0_aw_bits_addr[26]
  PIN mem_axi4_0_aw_bits_addr[27]
    DIRECTION OUTPUT TRISTATE ;
    USE SIGNAL ;
    ANTENNADIFFAREA 0.795200 ;
    PORT
      LAYER met3 ;
        RECT 0.000 1414.440 4.000 1415.040 ;
    END
  END mem_axi4_0_aw_bits_addr[27]
  PIN mem_axi4_0_aw_bits_addr[28]
    DIRECTION OUTPUT TRISTATE ;
    USE SIGNAL ;
    ANTENNADIFFAREA 0.795200 ;
    PORT
      LAYER met2 ;
        RECT 2817.590 0.000 2817.870 4.000 ;
    END
  END mem_axi4_0_aw_bits_addr[28]
  PIN mem_axi4_0_aw_bits_addr[29]
    DIRECTION OUTPUT TRISTATE ;
    USE SIGNAL ;
    ANTENNADIFFAREA 0.795200 ;
    PORT
      LAYER met3 ;
        RECT 6996.000 510.040 7000.000 510.640 ;
    END
  END mem_axi4_0_aw_bits_addr[29]
  PIN mem_axi4_0_aw_bits_addr[2]
    DIRECTION OUTPUT TRISTATE ;
    USE SIGNAL ;
    ANTENNADIFFAREA 0.795200 ;
    PORT
      LAYER met3 ;
        RECT 6996.000 438.640 7000.000 439.240 ;
    END
  END mem_axi4_0_aw_bits_addr[2]
  PIN mem_axi4_0_aw_bits_addr[30]
    DIRECTION OUTPUT TRISTATE ;
    USE SIGNAL ;
    ANTENNADIFFAREA 0.795200 ;
    PORT
      LAYER met3 ;
        RECT 6996.000 1499.440 7000.000 1500.040 ;
    END
  END mem_axi4_0_aw_bits_addr[30]
  PIN mem_axi4_0_aw_bits_addr[31]
    DIRECTION OUTPUT TRISTATE ;
    USE SIGNAL ;
    ANTENNADIFFAREA 0.795200 ;
    PORT
      LAYER met2 ;
        RECT 2279.850 0.000 2280.130 4.000 ;
    END
  END mem_axi4_0_aw_bits_addr[31]
  PIN mem_axi4_0_aw_bits_addr[3]
    DIRECTION OUTPUT TRISTATE ;
    USE SIGNAL ;
    ANTENNADIFFAREA 0.795200 ;
    PORT
      LAYER met2 ;
        RECT 5957.090 2596.000 5957.370 2600.000 ;
    END
  END mem_axi4_0_aw_bits_addr[3]
  PIN mem_axi4_0_aw_bits_addr[4]
    DIRECTION OUTPUT TRISTATE ;
    USE SIGNAL ;
    ANTENNADIFFAREA 0.795200 ;
    PORT
      LAYER met2 ;
        RECT 1742.110 0.000 1742.390 4.000 ;
    END
  END mem_axi4_0_aw_bits_addr[4]
  PIN mem_axi4_0_aw_bits_addr[5]
    DIRECTION OUTPUT TRISTATE ;
    USE SIGNAL ;
    ANTENNADIFFAREA 0.795200 ;
    PORT
      LAYER met3 ;
        RECT 0.000 1309.040 4.000 1309.640 ;
    END
  END mem_axi4_0_aw_bits_addr[5]
  PIN mem_axi4_0_aw_bits_addr[6]
    DIRECTION OUTPUT TRISTATE ;
    USE SIGNAL ;
    ANTENNADIFFAREA 0.795200 ;
    PORT
      LAYER met3 ;
        RECT 0.000 1771.440 4.000 1772.040 ;
    END
  END mem_axi4_0_aw_bits_addr[6]
  PIN mem_axi4_0_aw_bits_addr[7]
    DIRECTION OUTPUT TRISTATE ;
    USE SIGNAL ;
    ANTENNADIFFAREA 0.795200 ;
    PORT
      LAYER met3 ;
        RECT 0.000 1948.240 4.000 1948.840 ;
    END
  END mem_axi4_0_aw_bits_addr[7]
  PIN mem_axi4_0_aw_bits_addr[8]
    DIRECTION OUTPUT TRISTATE ;
    USE SIGNAL ;
    ANTENNADIFFAREA 0.795200 ;
    PORT
      LAYER met2 ;
        RECT 1932.090 2596.000 1932.370 2600.000 ;
    END
  END mem_axi4_0_aw_bits_addr[8]
  PIN mem_axi4_0_aw_bits_addr[9]
    DIRECTION OUTPUT TRISTATE ;
    USE SIGNAL ;
    ANTENNADIFFAREA 0.795200 ;
    PORT
      LAYER met2 ;
        RECT 3342.450 2596.000 3342.730 2600.000 ;
    END
  END mem_axi4_0_aw_bits_addr[9]
  PIN mem_axi4_0_aw_bits_burst[0]
    DIRECTION OUTPUT TRISTATE ;
    USE SIGNAL ;
    PORT
      LAYER met3 ;
        RECT 6996.000 1111.840 7000.000 1112.440 ;
    END
  END mem_axi4_0_aw_bits_burst[0]
  PIN mem_axi4_0_aw_bits_burst[1]
    DIRECTION OUTPUT TRISTATE ;
    USE SIGNAL ;
    PORT
      LAYER met2 ;
        RECT 5837.950 0.000 5838.230 4.000 ;
    END
  END mem_axi4_0_aw_bits_burst[1]
  PIN mem_axi4_0_aw_bits_cache[0]
    DIRECTION OUTPUT TRISTATE ;
    USE SIGNAL ;
    PORT
      LAYER met2 ;
        RECT 6407.890 0.000 6408.170 4.000 ;
    END
  END mem_axi4_0_aw_bits_cache[0]
  PIN mem_axi4_0_aw_bits_cache[1]
    DIRECTION OUTPUT TRISTATE ;
    USE SIGNAL ;
    PORT
      LAYER met2 ;
        RECT 1912.770 0.000 1913.050 4.000 ;
    END
  END mem_axi4_0_aw_bits_cache[1]
  PIN mem_axi4_0_aw_bits_cache[2]
    DIRECTION OUTPUT TRISTATE ;
    USE SIGNAL ;
    PORT
      LAYER met3 ;
        RECT 0.000 1700.040 4.000 1700.640 ;
    END
  END mem_axi4_0_aw_bits_cache[2]
  PIN mem_axi4_0_aw_bits_cache[3]
    DIRECTION OUTPUT TRISTATE ;
    USE SIGNAL ;
    PORT
      LAYER met2 ;
        RECT 1709.910 0.000 1710.190 4.000 ;
    END
  END mem_axi4_0_aw_bits_cache[3]
  PIN mem_axi4_0_aw_bits_id[0]
    DIRECTION OUTPUT TRISTATE ;
    USE SIGNAL ;
    PORT
      LAYER met2 ;
        RECT 1207.590 0.000 1207.870 4.000 ;
    END
  END mem_axi4_0_aw_bits_id[0]
  PIN mem_axi4_0_aw_bits_id[1]
    DIRECTION OUTPUT TRISTATE ;
    USE SIGNAL ;
    PORT
      LAYER met2 ;
        RECT 2502.030 2596.000 2502.310 2600.000 ;
    END
  END mem_axi4_0_aw_bits_id[1]
  PIN mem_axi4_0_aw_bits_id[2]
    DIRECTION OUTPUT TRISTATE ;
    USE SIGNAL ;
    PORT
      LAYER met2 ;
        RECT 3609.710 2596.000 3609.990 2600.000 ;
    END
  END mem_axi4_0_aw_bits_id[2]
  PIN mem_axi4_0_aw_bits_id[3]
    DIRECTION OUTPUT TRISTATE ;
    USE SIGNAL ;
    PORT
      LAYER met3 ;
        RECT 6996.000 329.840 7000.000 330.440 ;
    END
  END mem_axi4_0_aw_bits_id[3]
  PIN mem_axi4_0_aw_bits_len[0]
    DIRECTION OUTPUT TRISTATE ;
    USE SIGNAL ;
    PORT
      LAYER met2 ;
        RECT 4192.530 0.000 4192.810 4.000 ;
    END
  END mem_axi4_0_aw_bits_len[0]
  PIN mem_axi4_0_aw_bits_len[1]
    DIRECTION OUTPUT TRISTATE ;
    USE SIGNAL ;
    PORT
      LAYER met3 ;
        RECT 6996.000 2138.640 7000.000 2139.240 ;
    END
  END mem_axi4_0_aw_bits_len[1]
  PIN mem_axi4_0_aw_bits_len[2]
    DIRECTION OUTPUT TRISTATE ;
    USE SIGNAL ;
    PORT
      LAYER met2 ;
        RECT 1777.530 0.000 1777.810 4.000 ;
    END
  END mem_axi4_0_aw_bits_len[2]
  PIN mem_axi4_0_aw_bits_len[3]
    DIRECTION OUTPUT TRISTATE ;
    USE SIGNAL ;
    PORT
      LAYER met2 ;
        RECT 4347.090 2596.000 4347.370 2600.000 ;
    END
  END mem_axi4_0_aw_bits_len[3]
  PIN mem_axi4_0_aw_bits_len[4]
    DIRECTION OUTPUT TRISTATE ;
    USE SIGNAL ;
    PORT
      LAYER met2 ;
        RECT 3722.410 0.000 3722.690 4.000 ;
    END
  END mem_axi4_0_aw_bits_len[4]
  PIN mem_axi4_0_aw_bits_len[5]
    DIRECTION OUTPUT TRISTATE ;
    USE SIGNAL ;
    PORT
      LAYER met2 ;
        RECT 2469.830 2596.000 2470.110 2600.000 ;
    END
  END mem_axi4_0_aw_bits_len[5]
  PIN mem_axi4_0_aw_bits_len[6]
    DIRECTION OUTPUT TRISTATE ;
    USE SIGNAL ;
    PORT
      LAYER met2 ;
        RECT 2212.230 0.000 2212.510 4.000 ;
    END
  END mem_axi4_0_aw_bits_len[6]
  PIN mem_axi4_0_aw_bits_len[7]
    DIRECTION OUTPUT TRISTATE ;
    USE SIGNAL ;
    PORT
      LAYER met2 ;
        RECT 904.910 0.000 905.190 4.000 ;
    END
  END mem_axi4_0_aw_bits_len[7]
  PIN mem_axi4_0_aw_bits_lock
    DIRECTION OUTPUT TRISTATE ;
    USE SIGNAL ;
    PORT
      LAYER met2 ;
        RECT 6878.010 0.000 6878.290 4.000 ;
    END
  END mem_axi4_0_aw_bits_lock
  PIN mem_axi4_0_aw_bits_prot[0]
    DIRECTION OUTPUT TRISTATE ;
    USE SIGNAL ;
    PORT
      LAYER met2 ;
        RECT 724.590 2596.000 724.870 2600.000 ;
    END
  END mem_axi4_0_aw_bits_prot[0]
  PIN mem_axi4_0_aw_bits_prot[1]
    DIRECTION OUTPUT TRISTATE ;
    USE SIGNAL ;
    PORT
      LAYER met3 ;
        RECT 0.000 850.040 4.000 850.640 ;
    END
  END mem_axi4_0_aw_bits_prot[1]
  PIN mem_axi4_0_aw_bits_prot[2]
    DIRECTION OUTPUT TRISTATE ;
    USE SIGNAL ;
    PORT
      LAYER met2 ;
        RECT 1442.650 0.000 1442.930 4.000 ;
    END
  END mem_axi4_0_aw_bits_prot[2]
  PIN mem_axi4_0_aw_bits_qos[0]
    DIRECTION OUTPUT TRISTATE ;
    USE SIGNAL ;
    PORT
      LAYER met2 ;
        RECT 6610.750 0.000 6611.030 4.000 ;
    END
  END mem_axi4_0_aw_bits_qos[0]
  PIN mem_axi4_0_aw_bits_qos[1]
    DIRECTION OUTPUT TRISTATE ;
    USE SIGNAL ;
    PORT
      LAYER met2 ;
        RECT 4279.470 2596.000 4279.750 2600.000 ;
    END
  END mem_axi4_0_aw_bits_qos[1]
  PIN mem_axi4_0_aw_bits_qos[2]
    DIRECTION OUTPUT TRISTATE ;
    USE SIGNAL ;
    PORT
      LAYER met3 ;
        RECT 0.000 2512.640 4.000 2513.240 ;
    END
  END mem_axi4_0_aw_bits_qos[2]
  PIN mem_axi4_0_aw_bits_qos[3]
    DIRECTION OUTPUT TRISTATE ;
    USE SIGNAL ;
    PORT
      LAYER met2 ;
        RECT 4762.470 0.000 4762.750 4.000 ;
    END
  END mem_axi4_0_aw_bits_qos[3]
  PIN mem_axi4_0_aw_bits_size[0]
    DIRECTION OUTPUT TRISTATE ;
    USE SIGNAL ;
    ANTENNADIFFAREA 0.795200 ;
    PORT
      LAYER met2 ;
        RECT 4649.770 2596.000 4650.050 2600.000 ;
    END
  END mem_axi4_0_aw_bits_size[0]
  PIN mem_axi4_0_aw_bits_size[1]
    DIRECTION OUTPUT TRISTATE ;
    USE SIGNAL ;
    ANTENNADIFFAREA 0.795200 ;
    PORT
      LAYER met3 ;
        RECT 0.000 1485.840 4.000 1486.440 ;
    END
  END mem_axi4_0_aw_bits_size[1]
  PIN mem_axi4_0_aw_bits_size[2]
    DIRECTION OUTPUT TRISTATE ;
    USE SIGNAL ;
    PORT
      LAYER met2 ;
        RECT 5164.970 0.000 5165.250 4.000 ;
    END
  END mem_axi4_0_aw_bits_size[2]
  PIN mem_axi4_0_aw_ready
    DIRECTION INPUT ;
    USE SIGNAL ;
    ANTENNAGATEAREA 0.742500 ;
    PORT
      LAYER met3 ;
        RECT 0.000 2478.640 4.000 2479.240 ;
    END
  END mem_axi4_0_aw_ready
  PIN mem_axi4_0_aw_valid
    DIRECTION OUTPUT TRISTATE ;
    USE SIGNAL ;
    ANTENNADIFFAREA 0.795200 ;
    PORT
      LAYER met2 ;
        RECT 5200.390 0.000 5200.670 4.000 ;
    END
  END mem_axi4_0_aw_valid
  PIN mem_axi4_0_b_bits_id[0]
    DIRECTION INPUT ;
    USE SIGNAL ;
    ANTENNAGATEAREA 0.495000 ;
    PORT
      LAYER met3 ;
        RECT 6996.000 47.640 7000.000 48.240 ;
    END
  END mem_axi4_0_b_bits_id[0]
  PIN mem_axi4_0_b_bits_id[1]
    DIRECTION INPUT ;
    USE SIGNAL ;
    ANTENNAGATEAREA 0.126000 ;
    PORT
      LAYER met2 ;
        RECT 2872.330 2596.000 2872.610 2600.000 ;
    END
  END mem_axi4_0_b_bits_id[1]
  PIN mem_axi4_0_b_bits_id[2]
    DIRECTION INPUT ;
    USE SIGNAL ;
    ANTENNAGATEAREA 0.126000 ;
    PORT
      LAYER met2 ;
        RECT 6308.070 0.000 6308.350 4.000 ;
    END
  END mem_axi4_0_b_bits_id[2]
  PIN mem_axi4_0_b_bits_id[3]
    DIRECTION INPUT ;
    USE SIGNAL ;
    ANTENNAGATEAREA 0.126000 ;
    PORT
      LAYER met2 ;
        RECT 4965.330 0.000 4965.610 4.000 ;
    END
  END mem_axi4_0_b_bits_id[3]
  PIN mem_axi4_0_b_bits_resp[0]
    DIRECTION INPUT ;
    USE SIGNAL ;
    ANTENNAGATEAREA 0.126000 ;
    PORT
      LAYER met2 ;
        RECT 5219.710 2596.000 5219.990 2600.000 ;
    END
  END mem_axi4_0_b_bits_resp[0]
  PIN mem_axi4_0_b_bits_resp[1]
    DIRECTION INPUT ;
    USE SIGNAL ;
    ANTENNAGATEAREA 0.126000 ;
    PORT
      LAYER met2 ;
        RECT 2180.030 0.000 2180.310 4.000 ;
    END
  END mem_axi4_0_b_bits_resp[1]
  PIN mem_axi4_0_b_ready
    DIRECTION OUTPUT TRISTATE ;
    USE SIGNAL ;
    ANTENNADIFFAREA 0.795200 ;
    PORT
      LAYER met2 ;
        RECT 2131.730 2596.000 2132.010 2600.000 ;
    END
  END mem_axi4_0_b_ready
  PIN mem_axi4_0_b_valid
    DIRECTION INPUT ;
    USE SIGNAL ;
    ANTENNAGATEAREA 0.126000 ;
    PORT
      LAYER met2 ;
        RECT 6159.950 2596.000 6160.230 2600.000 ;
    END
  END mem_axi4_0_b_valid
  PIN mem_axi4_0_r_bits_data[0]
    DIRECTION INPUT ;
    USE SIGNAL ;
    ANTENNAGATEAREA 0.126000 ;
    PORT
      LAYER met2 ;
        RECT 3912.390 2596.000 3912.670 2600.000 ;
    END
  END mem_axi4_0_r_bits_data[0]
  PIN mem_axi4_0_r_bits_data[10]
    DIRECTION INPUT ;
    USE SIGNAL ;
    ANTENNAGATEAREA 0.213000 ;
    PORT
      LAYER met3 ;
        RECT 0.000 1557.240 4.000 1557.840 ;
    END
  END mem_axi4_0_r_bits_data[10]
  PIN mem_axi4_0_r_bits_data[11]
    DIRECTION INPUT ;
    USE SIGNAL ;
    ANTENNAGATEAREA 0.213000 ;
    PORT
      LAYER met2 ;
        RECT 1127.090 2596.000 1127.370 2600.000 ;
    END
  END mem_axi4_0_r_bits_data[11]
  PIN mem_axi4_0_r_bits_data[12]
    DIRECTION INPUT ;
    USE SIGNAL ;
    ANTENNAGATEAREA 0.495000 ;
    PORT
      LAYER met3 ;
        RECT 6996.000 1288.640 7000.000 1289.240 ;
    END
  END mem_axi4_0_r_bits_data[12]
  PIN mem_axi4_0_r_bits_data[13]
    DIRECTION INPUT ;
    USE SIGNAL ;
    ANTENNAGATEAREA 0.495000 ;
    PORT
      LAYER met3 ;
        RECT 6996.000 2172.640 7000.000 2173.240 ;
    END
  END mem_axi4_0_r_bits_data[13]
  PIN mem_axi4_0_r_bits_data[14]
    DIRECTION INPUT ;
    USE SIGNAL ;
    ANTENNAGATEAREA 0.126000 ;
    PORT
      LAYER met2 ;
        RECT 2112.410 0.000 2112.690 4.000 ;
    END
  END mem_axi4_0_r_bits_data[14]
  PIN mem_axi4_0_r_bits_data[15]
    DIRECTION INPUT ;
    USE SIGNAL ;
    ANTENNAGATEAREA 0.126000 ;
    PORT
      LAYER met2 ;
        RECT 3287.710 0.000 3287.990 4.000 ;
    END
  END mem_axi4_0_r_bits_data[15]
  PIN mem_axi4_0_r_bits_data[16]
    DIRECTION INPUT ;
    USE SIGNAL ;
    ANTENNAGATEAREA 0.196500 ;
    PORT
      LAYER met2 ;
        RECT 5789.650 2596.000 5789.930 2600.000 ;
    END
  END mem_axi4_0_r_bits_data[16]
  PIN mem_axi4_0_r_bits_data[17]
    DIRECTION INPUT ;
    USE SIGNAL ;
    ANTENNAGATEAREA 0.126000 ;
    PORT
      LAYER met2 ;
        RECT 4817.210 2596.000 4817.490 2600.000 ;
    END
  END mem_axi4_0_r_bits_data[17]
  PIN mem_axi4_0_r_bits_data[18]
    DIRECTION INPUT ;
    USE SIGNAL ;
    ANTENNAGATEAREA 0.742500 ;
    PORT
      LAYER met2 ;
        RECT 6208.250 0.000 6208.530 4.000 ;
    END
  END mem_axi4_0_r_bits_data[18]
  PIN mem_axi4_0_r_bits_data[19]
    DIRECTION INPUT ;
    USE SIGNAL ;
    ANTENNAGATEAREA 0.213000 ;
    PORT
      LAYER met3 ;
        RECT 0.000 1628.640 4.000 1629.240 ;
    END
  END mem_axi4_0_r_bits_data[19]
  PIN mem_axi4_0_r_bits_data[1]
    DIRECTION INPUT ;
    USE SIGNAL ;
    ANTENNAGATEAREA 0.196500 ;
    PORT
      LAYER met3 ;
        RECT 6996.000 2386.840 7000.000 2387.440 ;
    END
  END mem_axi4_0_r_bits_data[1]
  PIN mem_axi4_0_r_bits_data[20]
    DIRECTION INPUT ;
    USE SIGNAL ;
    ANTENNAGATEAREA 0.990000 ;
    PORT
      LAYER met2 ;
        RECT 5992.510 2596.000 5992.790 2600.000 ;
    END
  END mem_axi4_0_r_bits_data[20]
  PIN mem_axi4_0_r_bits_data[21]
    DIRECTION INPUT ;
    USE SIGNAL ;
    ANTENNAGATEAREA 0.126000 ;
    PORT
      LAYER met2 ;
        RECT 1529.590 2596.000 1529.870 2600.000 ;
    END
  END mem_axi4_0_r_bits_data[21]
  PIN mem_axi4_0_r_bits_data[22]
    DIRECTION INPUT ;
    USE SIGNAL ;
    ANTENNAGATEAREA 0.126000 ;
    PORT
      LAYER met2 ;
        RECT 2701.670 2596.000 2701.950 2600.000 ;
    END
  END mem_axi4_0_r_bits_data[22]
  PIN mem_axi4_0_r_bits_data[23]
    DIRECTION INPUT ;
    USE SIGNAL ;
    ANTENNAGATEAREA 0.742500 ;
    PORT
      LAYER met2 ;
        RECT 5973.190 0.000 5973.470 4.000 ;
    END
  END mem_axi4_0_r_bits_data[23]
  PIN mem_axi4_0_r_bits_data[24]
    DIRECTION INPUT ;
    USE SIGNAL ;
    ANTENNAGATEAREA 0.126000 ;
    PORT
      LAYER met2 ;
        RECT 3641.910 2596.000 3642.190 2600.000 ;
    END
  END mem_axi4_0_r_bits_data[24]
  PIN mem_axi4_0_r_bits_data[25]
    DIRECTION INPUT ;
    USE SIGNAL ;
    ANTENNAGATEAREA 0.126000 ;
    PORT
      LAYER met2 ;
        RECT 1877.350 0.000 1877.630 4.000 ;
    END
  END mem_axi4_0_r_bits_data[25]
  PIN mem_axi4_0_r_bits_data[26]
    DIRECTION INPUT ;
    USE SIGNAL ;
    ANTENNAGATEAREA 0.742500 ;
    PORT
      LAYER met2 ;
        RECT 32.290 0.000 32.570 4.000 ;
    END
  END mem_axi4_0_r_bits_data[26]
  PIN mem_axi4_0_r_bits_data[27]
    DIRECTION INPUT ;
    USE SIGNAL ;
    ANTENNAGATEAREA 0.126000 ;
    PORT
      LAYER met2 ;
        RECT 3017.230 0.000 3017.510 4.000 ;
    END
  END mem_axi4_0_r_bits_data[27]
  PIN mem_axi4_0_r_bits_data[28]
    DIRECTION INPUT ;
    USE SIGNAL ;
    ANTENNAGATEAREA 0.990000 ;
    PORT
      LAYER met2 ;
        RECT 6127.750 2596.000 6128.030 2600.000 ;
    END
  END mem_axi4_0_r_bits_data[28]
  PIN mem_axi4_0_r_bits_data[29]
    DIRECTION INPUT ;
    USE SIGNAL ;
    ANTENNAGATEAREA 0.126000 ;
    PORT
      LAYER met2 ;
        RECT 1091.670 2596.000 1091.950 2600.000 ;
    END
  END mem_axi4_0_r_bits_data[29]
  PIN mem_axi4_0_r_bits_data[2]
    DIRECTION INPUT ;
    USE SIGNAL ;
    ANTENNAGATEAREA 0.126000 ;
    PORT
      LAYER met2 ;
        RECT 4730.270 0.000 4730.550 4.000 ;
    END
  END mem_axi4_0_r_bits_data[2]
  PIN mem_axi4_0_r_bits_data[30]
    DIRECTION INPUT ;
    USE SIGNAL ;
    ANTENNAGATEAREA 0.126000 ;
    PORT
      LAYER met2 ;
        RECT 4382.510 2596.000 4382.790 2600.000 ;
    END
  END mem_axi4_0_r_bits_data[30]
  PIN mem_axi4_0_r_bits_data[31]
    DIRECTION INPUT ;
    USE SIGNAL ;
    ANTENNAGATEAREA 0.126000 ;
    PORT
      LAYER met2 ;
        RECT 3139.590 2596.000 3139.870 2600.000 ;
    END
  END mem_axi4_0_r_bits_data[31]
  PIN mem_axi4_0_r_bits_data[32]
    DIRECTION INPUT ;
    USE SIGNAL ;
    ANTENNAGATEAREA 0.213000 ;
    PORT
      LAYER met2 ;
        RECT 5032.950 0.000 5033.230 4.000 ;
    END
  END mem_axi4_0_r_bits_data[32]
  PIN mem_axi4_0_r_bits_data[33]
    DIRECTION INPUT ;
    USE SIGNAL ;
    ANTENNAGATEAREA 0.213000 ;
    PORT
      LAYER met3 ;
        RECT 6996.000 2067.240 7000.000 2067.840 ;
    END
  END mem_axi4_0_r_bits_data[33]
  PIN mem_axi4_0_r_bits_data[34]
    DIRECTION INPUT ;
    USE SIGNAL ;
    ANTENNAGATEAREA 0.196500 ;
    PORT
      LAYER met2 ;
        RECT 589.350 2596.000 589.630 2600.000 ;
    END
  END mem_axi4_0_r_bits_data[34]
  PIN mem_axi4_0_r_bits_data[35]
    DIRECTION INPUT ;
    USE SIGNAL ;
    ANTENNAGATEAREA 0.126000 ;
    PORT
      LAYER met2 ;
        RECT 4717.390 2596.000 4717.670 2600.000 ;
    END
  END mem_axi4_0_r_bits_data[35]
  PIN mem_axi4_0_r_bits_data[36]
    DIRECTION INPUT ;
    USE SIGNAL ;
    ANTENNAGATEAREA 0.126000 ;
    PORT
      LAYER met2 ;
        RECT 5119.890 2596.000 5120.170 2600.000 ;
    END
  END mem_axi4_0_r_bits_data[36]
  PIN mem_axi4_0_r_bits_data[37]
    DIRECTION INPUT ;
    USE SIGNAL ;
    ANTENNAGATEAREA 0.126000 ;
    PORT
      LAYER met2 ;
        RECT 4327.770 0.000 4328.050 4.000 ;
    END
  END mem_axi4_0_r_bits_data[37]
  PIN mem_axi4_0_r_bits_data[38]
    DIRECTION INPUT ;
    USE SIGNAL ;
    ANTENNAGATEAREA 0.126000 ;
    PORT
      LAYER met2 ;
        RECT 2601.850 2596.000 2602.130 2600.000 ;
    END
  END mem_axi4_0_r_bits_data[38]
  PIN mem_axi4_0_r_bits_data[39]
    DIRECTION INPUT ;
    USE SIGNAL ;
    ANTENNAGATEAREA 0.126000 ;
    PORT
      LAYER met2 ;
        RECT 991.850 2596.000 992.130 2600.000 ;
    END
  END mem_axi4_0_r_bits_data[39]
  PIN mem_axi4_0_r_bits_data[3]
    DIRECTION INPUT ;
    USE SIGNAL ;
    ANTENNAGATEAREA 0.126000 ;
    PORT
      LAYER met2 ;
        RECT 5702.710 0.000 5702.990 4.000 ;
    END
  END mem_axi4_0_r_bits_data[3]
  PIN mem_axi4_0_r_bits_data[40]
    DIRECTION INPUT ;
    USE SIGNAL ;
    ANTENNAGATEAREA 0.126000 ;
    PORT
      LAYER met2 ;
        RECT 2904.530 2596.000 2904.810 2600.000 ;
    END
  END mem_axi4_0_r_bits_data[40]
  PIN mem_axi4_0_r_bits_data[41]
    DIRECTION INPUT ;
    USE SIGNAL ;
    ANTENNAGATEAREA 0.126000 ;
    PORT
      LAYER met2 ;
        RECT 4681.970 2596.000 4682.250 2600.000 ;
    END
  END mem_axi4_0_r_bits_data[41]
  PIN mem_axi4_0_r_bits_data[42]
    DIRECTION INPUT ;
    USE SIGNAL ;
    ANTENNAGATEAREA 0.126000 ;
    PORT
      LAYER met2 ;
        RECT 4160.330 0.000 4160.610 4.000 ;
    END
  END mem_axi4_0_r_bits_data[42]
  PIN mem_axi4_0_r_bits_data[43]
    DIRECTION INPUT ;
    USE SIGNAL ;
    ANTENNAGATEAREA 0.126000 ;
    PORT
      LAYER met2 ;
        RECT 4060.510 0.000 4060.790 4.000 ;
    END
  END mem_axi4_0_r_bits_data[43]
  PIN mem_axi4_0_r_bits_data[44]
    DIRECTION INPUT ;
    USE SIGNAL ;
    ANTENNAGATEAREA 0.126000 ;
    PORT
      LAYER met2 ;
        RECT 1999.710 2596.000 1999.990 2600.000 ;
    END
  END mem_axi4_0_r_bits_data[44]
  PIN mem_axi4_0_r_bits_data[45]
    DIRECTION INPUT ;
    USE SIGNAL ;
    ANTENNAGATEAREA 0.742500 ;
    PORT
      LAYER met3 ;
        RECT 0.000 530.440 4.000 531.040 ;
    END
  END mem_axi4_0_r_bits_data[45]
  PIN mem_axi4_0_r_bits_data[46]
    DIRECTION INPUT ;
    USE SIGNAL ;
    ANTENNAGATEAREA 0.495000 ;
    PORT
      LAYER met3 ;
        RECT 6996.000 1322.640 7000.000 1323.240 ;
    END
  END mem_axi4_0_r_bits_data[46]
  PIN mem_axi4_0_r_bits_data[47]
    DIRECTION INPUT ;
    USE SIGNAL ;
    ANTENNAGATEAREA 0.495000 ;
    PORT
      LAYER met2 ;
        RECT 6443.310 0.000 6443.590 4.000 ;
    END
  END mem_axi4_0_r_bits_data[47]
  PIN mem_axi4_0_r_bits_data[48]
    DIRECTION INPUT ;
    USE SIGNAL ;
    ANTENNAGATEAREA 0.742500 ;
    PORT
      LAYER met3 ;
        RECT 6996.000 367.240 7000.000 367.840 ;
    END
  END mem_axi4_0_r_bits_data[48]
  PIN mem_axi4_0_r_bits_data[49]
    DIRECTION INPUT ;
    USE SIGNAL ;
    ANTENNAGATEAREA 0.742500 ;
    PORT
      LAYER met3 ;
        RECT 6996.000 401.240 7000.000 401.840 ;
    END
  END mem_axi4_0_r_bits_data[49]
  PIN mem_axi4_0_r_bits_data[4]
    DIRECTION INPUT ;
    USE SIGNAL ;
    ANTENNAGATEAREA 0.213000 ;
    PORT
      LAYER met2 ;
        RECT 6729.890 2596.000 6730.170 2600.000 ;
    END
  END mem_axi4_0_r_bits_data[4]
  PIN mem_axi4_0_r_bits_data[50]
    DIRECTION INPUT ;
    USE SIGNAL ;
    ANTENNAGATEAREA 0.126000 ;
    PORT
      LAYER met2 ;
        RECT 5757.450 2596.000 5757.730 2600.000 ;
    END
  END mem_axi4_0_r_bits_data[50]
  PIN mem_axi4_0_r_bits_data[51]
    DIRECTION INPUT ;
    USE SIGNAL ;
    ANTENNAGATEAREA 0.126000 ;
    PORT
      LAYER met2 ;
        RECT 5467.650 0.000 5467.930 4.000 ;
    END
  END mem_axi4_0_r_bits_data[51]
  PIN mem_axi4_0_r_bits_data[52]
    DIRECTION INPUT ;
    USE SIGNAL ;
    ANTENNAGATEAREA 0.495000 ;
    PORT
      LAYER met2 ;
        RECT 5905.570 0.000 5905.850 4.000 ;
    END
  END mem_axi4_0_r_bits_data[52]
  PIN mem_axi4_0_r_bits_data[53]
    DIRECTION INPUT ;
    USE SIGNAL ;
    ANTENNAGATEAREA 0.495000 ;
    PORT
      LAYER met2 ;
        RECT 570.030 0.000 570.310 4.000 ;
    END
  END mem_axi4_0_r_bits_data[53]
  PIN mem_axi4_0_r_bits_data[54]
    DIRECTION INPUT ;
    USE SIGNAL ;
    ANTENNAGATEAREA 0.742500 ;
    PORT
      LAYER met2 ;
        RECT 6675.150 0.000 6675.430 4.000 ;
    END
  END mem_axi4_0_r_bits_data[54]
  PIN mem_axi4_0_r_bits_data[55]
    DIRECTION INPUT ;
    USE SIGNAL ;
    ANTENNAGATEAREA 0.213000 ;
    PORT
      LAYER met2 ;
        RECT 1024.050 2596.000 1024.330 2600.000 ;
    END
  END mem_axi4_0_r_bits_data[55]
  PIN mem_axi4_0_r_bits_data[56]
    DIRECTION INPUT ;
    USE SIGNAL ;
    ANTENNAGATEAREA 0.196500 ;
    PORT
      LAYER met2 ;
        RECT 1610.090 0.000 1610.370 4.000 ;
    END
  END mem_axi4_0_r_bits_data[56]
  PIN mem_axi4_0_r_bits_data[57]
    DIRECTION INPUT ;
    USE SIGNAL ;
    ANTENNAGATEAREA 0.126000 ;
    PORT
      LAYER met2 ;
        RECT 5187.510 2596.000 5187.790 2600.000 ;
    END
  END mem_axi4_0_r_bits_data[57]
  PIN mem_axi4_0_r_bits_data[58]
    DIRECTION INPUT ;
    USE SIGNAL ;
    ANTENNAGATEAREA 0.213000 ;
    PORT
      LAYER met3 ;
        RECT 0.000 2407.240 4.000 2407.840 ;
    END
  END mem_axi4_0_r_bits_data[58]
  PIN mem_axi4_0_r_bits_data[59]
    DIRECTION INPUT ;
    USE SIGNAL ;
    ANTENNAGATEAREA 0.742500 ;
    PORT
      LAYER met3 ;
        RECT 0.000 105.440 4.000 106.040 ;
    END
  END mem_axi4_0_r_bits_data[59]
  PIN mem_axi4_0_r_bits_data[5]
    DIRECTION INPUT ;
    USE SIGNAL ;
    ANTENNAGATEAREA 0.196500 ;
    PORT
      LAYER met3 ;
        RECT 6996.000 897.640 7000.000 898.240 ;
    END
  END mem_axi4_0_r_bits_data[5]
  PIN mem_axi4_0_r_bits_data[60]
    DIRECTION INPUT ;
    USE SIGNAL ;
    ANTENNAGATEAREA 0.126000 ;
    PORT
      LAYER met2 ;
        RECT 6227.570 2596.000 6227.850 2600.000 ;
    END
  END mem_axi4_0_r_bits_data[60]
  PIN mem_axi4_0_r_bits_data[61]
    DIRECTION INPUT ;
    USE SIGNAL ;
    ANTENNAGATEAREA 0.990000 ;
    PORT
      LAYER met2 ;
        RECT 1104.550 0.000 1104.830 4.000 ;
    END
  END mem_axi4_0_r_bits_data[61]
  PIN mem_axi4_0_r_bits_data[62]
    DIRECTION INPUT ;
    USE SIGNAL ;
    ANTENNAGATEAREA 0.126000 ;
    PORT
      LAYER met2 ;
        RECT 3274.830 2596.000 3275.110 2600.000 ;
    END
  END mem_axi4_0_r_bits_data[62]
  PIN mem_axi4_0_r_bits_data[63]
    DIRECTION INPUT ;
    USE SIGNAL ;
    ANTENNAGATEAREA 0.126000 ;
    PORT
      LAYER met2 ;
        RECT 1474.850 0.000 1475.130 4.000 ;
    END
  END mem_axi4_0_r_bits_data[63]
  PIN mem_axi4_0_r_bits_data[6]
    DIRECTION INPUT ;
    USE SIGNAL ;
    ANTENNAGATEAREA 0.990000 ;
    PORT
      LAYER met3 ;
        RECT 0.000 2159.040 4.000 2159.640 ;
    END
  END mem_axi4_0_r_bits_data[6]
  PIN mem_axi4_0_r_bits_data[7]
    DIRECTION INPUT ;
    USE SIGNAL ;
    ANTENNAGATEAREA 0.990000 ;
    PORT
      LAYER met3 ;
        RECT 6996.000 1747.640 7000.000 1748.240 ;
    END
  END mem_axi4_0_r_bits_data[7]
  PIN mem_axi4_0_r_bits_data[8]
    DIRECTION INPUT ;
    USE SIGNAL ;
    ANTENNAGATEAREA 0.126000 ;
    PORT
      LAYER met2 ;
        RECT 3474.470 2596.000 3474.750 2600.000 ;
    END
  END mem_axi4_0_r_bits_data[8]
  PIN mem_axi4_0_r_bits_data[9]
    DIRECTION INPUT ;
    USE SIGNAL ;
    ANTENNAGATEAREA 0.126000 ;
    PORT
      LAYER met2 ;
        RECT 3590.390 0.000 3590.670 4.000 ;
    END
  END mem_axi4_0_r_bits_data[9]
  PIN mem_axi4_0_r_bits_id[0]
    DIRECTION INPUT ;
    USE SIGNAL ;
    ANTENNAGATEAREA 0.126000 ;
    PORT
      LAYER met2 ;
        RECT 3944.590 2596.000 3944.870 2600.000 ;
    END
  END mem_axi4_0_r_bits_id[0]
  PIN mem_axi4_0_r_bits_id[1]
    DIRECTION INPUT ;
    USE SIGNAL ;
    ANTENNAGATEAREA 0.196500 ;
    PORT
      LAYER met3 ;
        RECT 6996.000 720.840 7000.000 721.440 ;
    END
  END mem_axi4_0_r_bits_id[1]
  PIN mem_axi4_0_r_bits_id[2]
    DIRECTION INPUT ;
    USE SIGNAL ;
    ANTENNAGATEAREA 0.852000 ;
    PORT
      LAYER met2 ;
        RECT 737.470 0.000 737.750 4.000 ;
    END
  END mem_axi4_0_r_bits_id[2]
  PIN mem_axi4_0_r_bits_id[3]
    DIRECTION INPUT ;
    USE SIGNAL ;
    ANTENNAGATEAREA 0.126000 ;
    PORT
      LAYER met2 ;
        RECT 6024.710 2596.000 6024.990 2600.000 ;
    END
  END mem_axi4_0_r_bits_id[3]
  PIN mem_axi4_0_r_bits_last
    DIRECTION INPUT ;
    USE SIGNAL ;
    ANTENNAGATEAREA 0.126000 ;
    PORT
      LAYER met2 ;
        RECT 6997.150 2596.000 6997.430 2600.000 ;
    END
  END mem_axi4_0_r_bits_last
  PIN mem_axi4_0_r_bits_resp[0]
    DIRECTION INPUT ;
    USE SIGNAL ;
    ANTENNAGATEAREA 0.126000 ;
    PORT
      LAYER met2 ;
        RECT 4630.450 0.000 4630.730 4.000 ;
    END
  END mem_axi4_0_r_bits_resp[0]
  PIN mem_axi4_0_r_bits_resp[1]
    DIRECTION INPUT ;
    USE SIGNAL ;
    ANTENNAGATEAREA 0.742500 ;
    PORT
      LAYER met2 ;
        RECT 937.110 0.000 937.390 4.000 ;
    END
  END mem_axi4_0_r_bits_resp[1]
  PIN mem_axi4_0_r_ready
    DIRECTION OUTPUT TRISTATE ;
    USE SIGNAL ;
    ANTENNADIFFAREA 0.795200 ;
    PORT
      LAYER met2 ;
        RECT 5805.750 0.000 5806.030 4.000 ;
    END
  END mem_axi4_0_r_ready
  PIN mem_axi4_0_r_valid
    DIRECTION INPUT ;
    USE SIGNAL ;
    ANTENNAGATEAREA 0.126000 ;
    PORT
      LAYER met3 ;
        RECT 6996.000 615.440 7000.000 616.040 ;
    END
  END mem_axi4_0_r_valid
  PIN mem_axi4_0_w_bits_data[0]
    DIRECTION OUTPUT TRISTATE ;
    USE SIGNAL ;
    ANTENNADIFFAREA 0.795200 ;
    PORT
      LAYER met2 ;
        RECT 3622.590 0.000 3622.870 4.000 ;
    END
  END mem_axi4_0_w_bits_data[0]
  PIN mem_axi4_0_w_bits_data[10]
    DIRECTION OUTPUT TRISTATE ;
    USE SIGNAL ;
    ANTENNADIFFAREA 0.795200 ;
    PORT
      LAYER met2 ;
        RECT 2717.770 0.000 2718.050 4.000 ;
    END
  END mem_axi4_0_w_bits_data[10]
  PIN mem_axi4_0_w_bits_data[11]
    DIRECTION OUTPUT TRISTATE ;
    USE SIGNAL ;
    ANTENNADIFFAREA 0.795200 ;
    PORT
      LAYER met2 ;
        RECT 6897.330 2596.000 6897.610 2600.000 ;
    END
  END mem_axi4_0_w_bits_data[11]
  PIN mem_axi4_0_w_bits_data[12]
    DIRECTION OUTPUT TRISTATE ;
    USE SIGNAL ;
    ANTENNADIFFAREA 0.795200 ;
    PORT
      LAYER met2 ;
        RECT 6327.390 2596.000 6327.670 2600.000 ;
    END
  END mem_axi4_0_w_bits_data[12]
  PIN mem_axi4_0_w_bits_data[13]
    DIRECTION OUTPUT TRISTATE ;
    USE SIGNAL ;
    ANTENNADIFFAREA 0.795200 ;
    PORT
      LAYER met2 ;
        RECT 689.170 2596.000 689.450 2600.000 ;
    END
  END mem_axi4_0_w_bits_data[13]
  PIN mem_axi4_0_w_bits_data[14]
    DIRECTION OUTPUT TRISTATE ;
    USE SIGNAL ;
    ANTENNADIFFAREA 0.795200 ;
    PORT
      LAYER met3 ;
        RECT 6996.000 1785.040 7000.000 1785.640 ;
    END
  END mem_axi4_0_w_bits_data[14]
  PIN mem_axi4_0_w_bits_data[15]
    DIRECTION OUTPUT TRISTATE ;
    USE SIGNAL ;
    ANTENNADIFFAREA 0.795200 ;
    PORT
      LAYER met2 ;
        RECT 3004.350 2596.000 3004.630 2600.000 ;
    END
  END mem_axi4_0_w_bits_data[15]
  PIN mem_axi4_0_w_bits_data[16]
    DIRECTION OUTPUT TRISTATE ;
    USE SIGNAL ;
    ANTENNADIFFAREA 0.795200 ;
    PORT
      LAYER met2 ;
        RECT 2569.650 2596.000 2569.930 2600.000 ;
    END
  END mem_axi4_0_w_bits_data[16]
  PIN mem_axi4_0_w_bits_data[17]
    DIRECTION OUTPUT TRISTATE ;
    USE SIGNAL ;
    ANTENNADIFFAREA 0.795200 ;
    PORT
      LAYER met2 ;
        RECT 2514.910 0.000 2515.190 4.000 ;
    END
  END mem_axi4_0_w_bits_data[17]
  PIN mem_axi4_0_w_bits_data[18]
    DIRECTION OUTPUT TRISTATE ;
    USE SIGNAL ;
    ANTENNADIFFAREA 0.795200 ;
    PORT
      LAYER met3 ;
        RECT 6996.000 472.640 7000.000 473.240 ;
    END
  END mem_axi4_0_w_bits_data[18]
  PIN mem_axi4_0_w_bits_data[19]
    DIRECTION OUTPUT TRISTATE ;
    USE SIGNAL ;
    ANTENNADIFFAREA 0.795200 ;
    PORT
      LAYER met3 ;
        RECT 6996.000 1819.040 7000.000 1819.640 ;
    END
  END mem_axi4_0_w_bits_data[19]
  PIN mem_axi4_0_w_bits_data[1]
    DIRECTION OUTPUT TRISTATE ;
    USE SIGNAL ;
    ANTENNADIFFAREA 0.795200 ;
    PORT
      LAYER met2 ;
        RECT 87.030 2596.000 87.310 2600.000 ;
    END
  END mem_axi4_0_w_bits_data[1]
  PIN mem_axi4_0_w_bits_data[20]
    DIRECTION OUTPUT TRISTATE ;
    USE SIGNAL ;
    ANTENNADIFFAREA 0.795200 ;
    PORT
      LAYER met2 ;
        RECT 5268.010 0.000 5268.290 4.000 ;
    END
  END mem_axi4_0_w_bits_data[20]
  PIN mem_axi4_0_w_bits_data[21]
    DIRECTION OUTPUT TRISTATE ;
    USE SIGNAL ;
    ANTENNADIFFAREA 0.795200 ;
    PORT
      LAYER met3 ;
        RECT 0.000 1275.040 4.000 1275.640 ;
    END
  END mem_axi4_0_w_bits_data[21]
  PIN mem_axi4_0_w_bits_data[22]
    DIRECTION OUTPUT TRISTATE ;
    USE SIGNAL ;
    ANTENNADIFFAREA 0.795200 ;
    PORT
      LAYER met2 ;
        RECT 2534.230 2596.000 2534.510 2600.000 ;
    END
  END mem_axi4_0_w_bits_data[22]
  PIN mem_axi4_0_w_bits_data[23]
    DIRECTION OUTPUT TRISTATE ;
    USE SIGNAL ;
    ANTENNADIFFAREA 0.795200 ;
    PORT
      LAYER met2 ;
        RECT 119.230 2596.000 119.510 2600.000 ;
    END
  END mem_axi4_0_w_bits_data[23]
  PIN mem_axi4_0_w_bits_data[24]
    DIRECTION OUTPUT TRISTATE ;
    USE SIGNAL ;
    ANTENNADIFFAREA 0.795200 ;
    PORT
      LAYER met2 ;
        RECT 1729.230 2596.000 1729.510 2600.000 ;
    END
  END mem_axi4_0_w_bits_data[24]
  PIN mem_axi4_0_w_bits_data[25]
    DIRECTION OUTPUT TRISTATE ;
    USE SIGNAL ;
    ANTENNADIFFAREA 0.795200 ;
    PORT
      LAYER met2 ;
        RECT 4463.010 0.000 4463.290 4.000 ;
    END
  END mem_axi4_0_w_bits_data[25]
  PIN mem_axi4_0_w_bits_data[26]
    DIRECTION OUTPUT TRISTATE ;
    USE SIGNAL ;
    ANTENNADIFFAREA 0.795200 ;
    PORT
      LAYER met2 ;
        RECT 4012.210 2596.000 4012.490 2600.000 ;
    END
  END mem_axi4_0_w_bits_data[26]
  PIN mem_axi4_0_w_bits_data[27]
    DIRECTION OUTPUT TRISTATE ;
    USE SIGNAL ;
    ANTENNADIFFAREA 0.795200 ;
    PORT
      LAYER met2 ;
        RECT 4147.450 2596.000 4147.730 2600.000 ;
    END
  END mem_axi4_0_w_bits_data[27]
  PIN mem_axi4_0_w_bits_data[28]
    DIRECTION OUTPUT TRISTATE ;
    USE SIGNAL ;
    ANTENNADIFFAREA 0.795200 ;
    PORT
      LAYER met2 ;
        RECT 5335.630 0.000 5335.910 4.000 ;
    END
  END mem_axi4_0_w_bits_data[28]
  PIN mem_axi4_0_w_bits_data[29]
    DIRECTION OUTPUT TRISTATE ;
    USE SIGNAL ;
    ANTENNADIFFAREA 0.795200 ;
    PORT
      LAYER met2 ;
        RECT 1407.230 0.000 1407.510 4.000 ;
    END
  END mem_axi4_0_w_bits_data[29]
  PIN mem_axi4_0_w_bits_data[2]
    DIRECTION OUTPUT TRISTATE ;
    USE SIGNAL ;
    ANTENNADIFFAREA 0.795200 ;
    PORT
      LAYER met2 ;
        RECT 151.430 2596.000 151.710 2600.000 ;
    END
  END mem_axi4_0_w_bits_data[2]
  PIN mem_axi4_0_w_bits_data[30]
    DIRECTION OUTPUT TRISTATE ;
    USE SIGNAL ;
    ANTENNADIFFAREA 0.795200 ;
    PORT
      LAYER met2 ;
        RECT 824.410 2596.000 824.690 2600.000 ;
    END
  END mem_axi4_0_w_bits_data[30]
  PIN mem_axi4_0_w_bits_data[31]
    DIRECTION OUTPUT TRISTATE ;
    USE SIGNAL ;
    ANTENNADIFFAREA 0.795200 ;
    PORT
      LAYER met2 ;
        RECT 6427.210 2596.000 6427.490 2600.000 ;
    END
  END mem_axi4_0_w_bits_data[31]
  PIN mem_axi4_0_w_bits_data[32]
    DIRECTION OUTPUT TRISTATE ;
    USE SIGNAL ;
    ANTENNADIFFAREA 0.795200 ;
    PORT
      LAYER met3 ;
        RECT 6996.000 2529.640 7000.000 2530.240 ;
    END
  END mem_axi4_0_w_bits_data[32]
  PIN mem_axi4_0_w_bits_data[33]
    DIRECTION OUTPUT TRISTATE ;
    USE SIGNAL ;
    ANTENNADIFFAREA 0.795200 ;
    PORT
      LAYER met2 ;
        RECT 6272.650 0.000 6272.930 4.000 ;
    END
  END mem_axi4_0_w_bits_data[33]
  PIN mem_axi4_0_w_bits_data[34]
    DIRECTION OUTPUT TRISTATE ;
    USE SIGNAL ;
    ANTENNADIFFAREA 0.795200 ;
    PORT
      LAYER met2 ;
        RECT 702.050 0.000 702.330 4.000 ;
    END
  END mem_axi4_0_w_bits_data[34]
  PIN mem_axi4_0_w_bits_data[35]
    DIRECTION OUTPUT TRISTATE ;
    USE SIGNAL ;
    ANTENNADIFFAREA 0.795200 ;
    PORT
      LAYER met2 ;
        RECT 6475.510 0.000 6475.790 4.000 ;
    END
  END mem_axi4_0_w_bits_data[35]
  PIN mem_axi4_0_w_bits_data[36]
    DIRECTION OUTPUT TRISTATE ;
    USE SIGNAL ;
    ANTENNADIFFAREA 0.795200 ;
    PORT
      LAYER met2 ;
        RECT 2031.910 2596.000 2032.190 2600.000 ;
    END
  END mem_axi4_0_w_bits_data[36]
  PIN mem_axi4_0_w_bits_data[37]
    DIRECTION OUTPUT TRISTATE ;
    USE SIGNAL ;
    ANTENNADIFFAREA 0.795200 ;
    PORT
      LAYER met2 ;
        RECT 6630.070 2596.000 6630.350 2600.000 ;
    END
  END mem_axi4_0_w_bits_data[37]
  PIN mem_axi4_0_w_bits_data[38]
    DIRECTION OUTPUT TRISTATE ;
    USE SIGNAL ;
    ANTENNADIFFAREA 0.795200 ;
    PORT
      LAYER met3 ;
        RECT 0.000 282.240 4.000 282.840 ;
    END
  END mem_axi4_0_w_bits_data[38]
  PIN mem_axi4_0_w_bits_data[39]
    DIRECTION OUTPUT TRISTATE ;
    USE SIGNAL ;
    ANTENNADIFFAREA 0.795200 ;
    PORT
      LAYER met3 ;
        RECT 6996.000 1006.440 7000.000 1007.040 ;
    END
  END mem_axi4_0_w_bits_data[39]
  PIN mem_axi4_0_w_bits_data[3]
    DIRECTION OUTPUT TRISTATE ;
    USE SIGNAL ;
    ANTENNADIFFAREA 0.795200 ;
    PORT
      LAYER met3 ;
        RECT 0.000 812.640 4.000 813.240 ;
    END
  END mem_axi4_0_w_bits_data[3]
  PIN mem_axi4_0_w_bits_data[40]
    DIRECTION OUTPUT TRISTATE ;
    USE SIGNAL ;
    ANTENNADIFFAREA 0.795200 ;
    PORT
      LAYER met3 ;
        RECT 0.000 1451.840 4.000 1452.440 ;
    END
  END mem_axi4_0_w_bits_data[40]
  PIN mem_axi4_0_w_bits_data[41]
    DIRECTION OUTPUT TRISTATE ;
    USE SIGNAL ;
    ANTENNADIFFAREA 0.795200 ;
    PORT
      LAYER met2 ;
        RECT 2985.030 0.000 2985.310 4.000 ;
    END
  END mem_axi4_0_w_bits_data[41]
  PIN mem_axi4_0_w_bits_data[42]
    DIRECTION OUTPUT TRISTATE ;
    USE SIGNAL ;
    ANTENNADIFFAREA 0.795200 ;
    PORT
      LAYER met2 ;
        RECT 6575.330 0.000 6575.610 4.000 ;
    END
  END mem_axi4_0_w_bits_data[42]
  PIN mem_axi4_0_w_bits_data[43]
    DIRECTION OUTPUT TRISTATE ;
    USE SIGNAL ;
    ANTENNADIFFAREA 0.795200 ;
    PORT
      LAYER met2 ;
        RECT 2234.770 2596.000 2235.050 2600.000 ;
    END
  END mem_axi4_0_w_bits_data[43]
  PIN mem_axi4_0_w_bits_data[44]
    DIRECTION OUTPUT TRISTATE ;
    USE SIGNAL ;
    ANTENNADIFFAREA 0.795200 ;
    PORT
      LAYER met2 ;
        RECT 254.470 2596.000 254.750 2600.000 ;
    END
  END mem_axi4_0_w_bits_data[44]
  PIN mem_axi4_0_w_bits_data[45]
    DIRECTION OUTPUT TRISTATE ;
    USE SIGNAL ;
    ANTENNADIFFAREA 0.795200 ;
    PORT
      LAYER met2 ;
        RECT 1944.970 0.000 1945.250 4.000 ;
    END
  END mem_axi4_0_w_bits_data[45]
  PIN mem_axi4_0_w_bits_data[46]
    DIRECTION OUTPUT TRISTATE ;
    USE SIGNAL ;
    ANTENNADIFFAREA 0.795200 ;
    PORT
      LAYER met2 ;
        RECT 3084.850 0.000 3085.130 4.000 ;
    END
  END mem_axi4_0_w_bits_data[46]
  PIN mem_axi4_0_w_bits_data[47]
    DIRECTION OUTPUT TRISTATE ;
    USE SIGNAL ;
    ANTENNADIFFAREA 0.795200 ;
    PORT
      LAYER met3 ;
        RECT 0.000 2550.040 4.000 2550.640 ;
    END
  END mem_axi4_0_w_bits_data[47]
  PIN mem_axi4_0_w_bits_data[48]
    DIRECTION OUTPUT TRISTATE ;
    USE SIGNAL ;
    ANTENNADIFFAREA 0.795200 ;
    PORT
      LAYER met2 ;
        RECT 1461.970 2596.000 1462.250 2600.000 ;
    END
  END mem_axi4_0_w_bits_data[48]
  PIN mem_axi4_0_w_bits_data[49]
    DIRECTION OUTPUT TRISTATE ;
    USE SIGNAL ;
    ANTENNADIFFAREA 0.795200 ;
    PORT
      LAYER met2 ;
        RECT 5670.510 0.000 5670.790 4.000 ;
    END
  END mem_axi4_0_w_bits_data[49]
  PIN mem_axi4_0_w_bits_data[4]
    DIRECTION OUTPUT TRISTATE ;
    USE SIGNAL ;
    ANTENNADIFFAREA 0.795200 ;
    PORT
      LAYER met3 ;
        RECT 0.000 2584.040 4.000 2584.640 ;
    END
  END mem_axi4_0_w_bits_data[4]
  PIN mem_axi4_0_w_bits_data[50]
    DIRECTION OUTPUT TRISTATE ;
    USE SIGNAL ;
    ANTENNADIFFAREA 0.795200 ;
    PORT
      LAYER met3 ;
        RECT 0.000 1132.240 4.000 1132.840 ;
    END
  END mem_axi4_0_w_bits_data[50]
  PIN mem_axi4_0_w_bits_data[51]
    DIRECTION OUTPUT TRISTATE ;
    USE SIGNAL ;
    ANTENNADIFFAREA 0.795200 ;
    PORT
      LAYER met2 ;
        RECT 4698.070 0.000 4698.350 4.000 ;
    END
  END mem_axi4_0_w_bits_data[51]
  PIN mem_axi4_0_w_bits_data[52]
    DIRECTION OUTPUT TRISTATE ;
    USE SIGNAL ;
    ANTENNADIFFAREA 0.795200 ;
    PORT
      LAYER met3 ;
        RECT 6996.000 1536.840 7000.000 1537.440 ;
    END
  END mem_axi4_0_w_bits_data[52]
  PIN mem_axi4_0_w_bits_data[53]
    DIRECTION OUTPUT TRISTATE ;
    USE SIGNAL ;
    ANTENNADIFFAREA 0.795200 ;
    PORT
      LAYER met2 ;
        RECT 3857.650 0.000 3857.930 4.000 ;
    END
  END mem_axi4_0_w_bits_data[53]
  PIN mem_axi4_0_w_bits_data[54]
    DIRECTION OUTPUT TRISTATE ;
    USE SIGNAL ;
    ANTENNADIFFAREA 0.795200 ;
    PORT
      LAYER met2 ;
        RECT 6295.190 2596.000 6295.470 2600.000 ;
    END
  END mem_axi4_0_w_bits_data[54]
  PIN mem_axi4_0_w_bits_data[55]
    DIRECTION OUTPUT TRISTATE ;
    USE SIGNAL ;
    ANTENNADIFFAREA 0.795200 ;
    PORT
      LAYER met2 ;
        RECT 5454.770 2596.000 5455.050 2600.000 ;
    END
  END mem_axi4_0_w_bits_data[55]
  PIN mem_axi4_0_w_bits_data[56]
    DIRECTION OUTPUT TRISTATE ;
    USE SIGNAL ;
    ANTENNADIFFAREA 0.795200 ;
    PORT
      LAYER met2 ;
        RECT 1239.790 0.000 1240.070 4.000 ;
    END
  END mem_axi4_0_w_bits_data[56]
  PIN mem_axi4_0_w_bits_data[57]
    DIRECTION OUTPUT TRISTATE ;
    USE SIGNAL ;
    ANTENNADIFFAREA 0.795200 ;
    PORT
      LAYER met2 ;
        RECT 5937.770 0.000 5938.050 4.000 ;
    END
  END mem_axi4_0_w_bits_data[57]
  PIN mem_axi4_0_w_bits_data[58]
    DIRECTION OUTPUT TRISTATE ;
    USE SIGNAL ;
    ANTENNADIFFAREA 0.795200 ;
    PORT
      LAYER met2 ;
        RECT 2080.210 0.000 2080.490 4.000 ;
    END
  END mem_axi4_0_w_bits_data[58]
  PIN mem_axi4_0_w_bits_data[59]
    DIRECTION OUTPUT TRISTATE ;
    USE SIGNAL ;
    ANTENNADIFFAREA 0.795200 ;
    PORT
      LAYER met2 ;
        RECT 5570.690 0.000 5570.970 4.000 ;
    END
  END mem_axi4_0_w_bits_data[59]
  PIN mem_axi4_0_w_bits_data[5]
    DIRECTION OUTPUT TRISTATE ;
    USE SIGNAL ;
    ANTENNADIFFAREA 0.795200 ;
    PORT
      LAYER met3 ;
        RECT 6996.000 1074.440 7000.000 1075.040 ;
    END
  END mem_axi4_0_w_bits_data[5]
  PIN mem_axi4_0_w_bits_data[60]
    DIRECTION OUTPUT TRISTATE ;
    USE SIGNAL ;
    ANTENNADIFFAREA 0.795200 ;
    PORT
      LAYER met2 ;
        RECT 3052.650 0.000 3052.930 4.000 ;
    END
  END mem_axi4_0_w_bits_data[60]
  PIN mem_axi4_0_w_bits_data[61]
    DIRECTION OUTPUT TRISTATE ;
    USE SIGNAL ;
    ANTENNADIFFAREA 0.795200 ;
    PORT
      LAYER met2 ;
        RECT 2482.710 0.000 2482.990 4.000 ;
    END
  END mem_axi4_0_w_bits_data[61]
  PIN mem_axi4_0_w_bits_data[62]
    DIRECTION OUTPUT TRISTATE ;
    USE SIGNAL ;
    ANTENNADIFFAREA 0.795200 ;
    PORT
      LAYER met2 ;
        RECT 267.350 0.000 267.630 4.000 ;
    END
  END mem_axi4_0_w_bits_data[62]
  PIN mem_axi4_0_w_bits_data[63]
    DIRECTION OUTPUT TRISTATE ;
    USE SIGNAL ;
    ANTENNADIFFAREA 0.795200 ;
    PORT
      LAYER met2 ;
        RECT 434.790 0.000 435.070 4.000 ;
    END
  END mem_axi4_0_w_bits_data[63]
  PIN mem_axi4_0_w_bits_data[6]
    DIRECTION OUTPUT TRISTATE ;
    USE SIGNAL ;
    ANTENNADIFFAREA 0.795200 ;
    PORT
      LAYER met2 ;
        RECT 3690.210 0.000 3690.490 4.000 ;
    END
  END mem_axi4_0_w_bits_data[6]
  PIN mem_axi4_0_w_bits_data[7]
    DIRECTION OUTPUT TRISTATE ;
    USE SIGNAL ;
    ANTENNADIFFAREA 0.795200 ;
    PORT
      LAYER met2 ;
        RECT 4527.410 0.000 4527.690 4.000 ;
    END
  END mem_axi4_0_w_bits_data[7]
  PIN mem_axi4_0_w_bits_data[8]
    DIRECTION OUTPUT TRISTATE ;
    USE SIGNAL ;
    ANTENNADIFFAREA 0.795200 ;
    PORT
      LAYER met2 ;
        RECT 4749.590 2596.000 4749.870 2600.000 ;
    END
  END mem_axi4_0_w_bits_data[8]
  PIN mem_axi4_0_w_bits_data[9]
    DIRECTION OUTPUT TRISTATE ;
    USE SIGNAL ;
    ANTENNADIFFAREA 0.795200 ;
    PORT
      LAYER met2 ;
        RECT 5535.270 0.000 5535.550 4.000 ;
    END
  END mem_axi4_0_w_bits_data[9]
  PIN mem_axi4_0_w_bits_last
    DIRECTION OUTPUT TRISTATE ;
    USE SIGNAL ;
    PORT
      LAYER met2 ;
        RECT 6932.750 2596.000 6933.030 2600.000 ;
    END
  END mem_axi4_0_w_bits_last
  PIN mem_axi4_0_w_bits_strb[0]
    DIRECTION OUTPUT TRISTATE ;
    USE SIGNAL ;
    ANTENNADIFFAREA 0.795200 ;
    PORT
      LAYER met2 ;
        RECT 334.970 0.000 335.250 4.000 ;
    END
  END mem_axi4_0_w_bits_strb[0]
  PIN mem_axi4_0_w_bits_strb[1]
    DIRECTION OUTPUT TRISTATE ;
    USE SIGNAL ;
    ANTENNADIFFAREA 0.795200 ;
    PORT
      LAYER met3 ;
        RECT 6996.000 2315.440 7000.000 2316.040 ;
    END
  END mem_axi4_0_w_bits_strb[1]
  PIN mem_axi4_0_w_bits_strb[2]
    DIRECTION OUTPUT TRISTATE ;
    USE SIGNAL ;
    ANTENNADIFFAREA 0.795200 ;
    PORT
      LAYER met3 ;
        RECT 0.000 635.840 4.000 636.440 ;
    END
  END mem_axi4_0_w_bits_strb[2]
  PIN mem_axi4_0_w_bits_strb[3]
    DIRECTION OUTPUT TRISTATE ;
    USE SIGNAL ;
    ANTENNADIFFAREA 0.795200 ;
    PORT
      LAYER met2 ;
        RECT 1375.030 0.000 1375.310 4.000 ;
    END
  END mem_axi4_0_w_bits_strb[3]
  PIN mem_axi4_0_w_bits_strb[4]
    DIRECTION OUTPUT TRISTATE ;
    USE SIGNAL ;
    ANTENNADIFFAREA 0.795200 ;
    PORT
      LAYER met2 ;
        RECT 1832.270 2596.000 1832.550 2600.000 ;
    END
  END mem_axi4_0_w_bits_strb[4]
  PIN mem_axi4_0_w_bits_strb[5]
    DIRECTION OUTPUT TRISTATE ;
    USE SIGNAL ;
    ANTENNADIFFAREA 0.795200 ;
    PORT
      LAYER met2 ;
        RECT 6642.950 0.000 6643.230 4.000 ;
    END
  END mem_axi4_0_w_bits_strb[5]
  PIN mem_axi4_0_w_bits_strb[6]
    DIRECTION OUTPUT TRISTATE ;
    USE SIGNAL ;
    ANTENNADIFFAREA 0.795200 ;
    PORT
      LAYER met2 ;
        RECT 4662.650 0.000 4662.930 4.000 ;
    END
  END mem_axi4_0_w_bits_strb[6]
  PIN mem_axi4_0_w_bits_strb[7]
    DIRECTION OUTPUT TRISTATE ;
    USE SIGNAL ;
    ANTENNADIFFAREA 0.795200 ;
    PORT
      LAYER met3 ;
        RECT 0.000 1910.840 4.000 1911.440 ;
    END
  END mem_axi4_0_w_bits_strb[7]
  PIN mem_axi4_0_w_ready
    DIRECTION INPUT ;
    USE SIGNAL ;
    ANTENNAGATEAREA 0.126000 ;
    PORT
      LAYER met2 ;
        RECT 2379.670 0.000 2379.950 4.000 ;
    END
  END mem_axi4_0_w_ready
  PIN mem_axi4_0_w_valid
    DIRECTION OUTPUT TRISTATE ;
    USE SIGNAL ;
    ANTENNADIFFAREA 0.795200 ;
    PORT
      LAYER met2 ;
        RECT 2315.270 0.000 2315.550 4.000 ;
    END
  END mem_axi4_0_w_valid
  PIN mmio_axi4_0_ar_bits_addr[0]
    DIRECTION OUTPUT TRISTATE ;
    USE SIGNAL ;
    ANTENNADIFFAREA 0.795200 ;
    PORT
      LAYER met2 ;
        RECT 5152.090 2596.000 5152.370 2600.000 ;
    END
  END mmio_axi4_0_ar_bits_addr[0]
  PIN mmio_axi4_0_ar_bits_addr[10]
    DIRECTION OUTPUT TRISTATE ;
    USE SIGNAL ;
    ANTENNADIFFAREA 0.795200 ;
    PORT
      LAYER met2 ;
        RECT 6530.250 2596.000 6530.530 2600.000 ;
    END
  END mmio_axi4_0_ar_bits_addr[10]
  PIN mmio_axi4_0_ar_bits_addr[11]
    DIRECTION OUTPUT TRISTATE ;
    USE SIGNAL ;
    ANTENNADIFFAREA 0.795200 ;
    PORT
      LAYER met3 ;
        RECT 6996.000 2420.840 7000.000 2421.440 ;
    END
  END mmio_axi4_0_ar_bits_addr[11]
  PIN mmio_axi4_0_ar_bits_addr[12]
    DIRECTION OUTPUT TRISTATE ;
    USE SIGNAL ;
    ANTENNADIFFAREA 0.795200 ;
    PORT
      LAYER met2 ;
        RECT 602.230 0.000 602.510 4.000 ;
    END
  END mmio_axi4_0_ar_bits_addr[12]
  PIN mmio_axi4_0_ar_bits_addr[13]
    DIRECTION OUTPUT TRISTATE ;
    USE SIGNAL ;
    ANTENNADIFFAREA 0.795200 ;
    PORT
      LAYER met2 ;
        RECT 3487.350 0.000 3487.630 4.000 ;
    END
  END mmio_axi4_0_ar_bits_addr[13]
  PIN mmio_axi4_0_ar_bits_addr[14]
    DIRECTION OUTPUT TRISTATE ;
    USE SIGNAL ;
    ANTENNADIFFAREA 0.795200 ;
    PORT
      LAYER met2 ;
        RECT 3889.850 0.000 3890.130 4.000 ;
    END
  END mmio_axi4_0_ar_bits_addr[14]
  PIN mmio_axi4_0_ar_bits_addr[15]
    DIRECTION OUTPUT TRISTATE ;
    USE SIGNAL ;
    ANTENNADIFFAREA 0.795200 ;
    PORT
      LAYER met2 ;
        RECT 6810.390 0.000 6810.670 4.000 ;
    END
  END mmio_axi4_0_ar_bits_addr[15]
  PIN mmio_axi4_0_ar_bits_addr[16]
    DIRECTION OUTPUT TRISTATE ;
    USE SIGNAL ;
    ANTENNADIFFAREA 0.795200 ;
    PORT
      LAYER met2 ;
        RECT 6259.770 2596.000 6260.050 2600.000 ;
    END
  END mmio_axi4_0_ar_bits_addr[16]
  PIN mmio_axi4_0_ar_bits_addr[17]
    DIRECTION OUTPUT TRISTATE ;
    USE SIGNAL ;
    ANTENNADIFFAREA 0.795200 ;
    PORT
      LAYER met3 ;
        RECT 0.000 1591.240 4.000 1591.840 ;
    END
  END mmio_axi4_0_ar_bits_addr[17]
  PIN mmio_axi4_0_ar_bits_addr[18]
    DIRECTION OUTPUT TRISTATE ;
    USE SIGNAL ;
    ANTENNADIFFAREA 0.795200 ;
    PORT
      LAYER met2 ;
        RECT 2147.830 0.000 2148.110 4.000 ;
    END
  END mmio_axi4_0_ar_bits_addr[18]
  PIN mmio_axi4_0_ar_bits_addr[19]
    DIRECTION OUTPUT TRISTATE ;
    USE SIGNAL ;
    ANTENNADIFFAREA 0.795200 ;
    PORT
      LAYER met2 ;
        RECT 3187.890 0.000 3188.170 4.000 ;
    END
  END mmio_axi4_0_ar_bits_addr[19]
  PIN mmio_axi4_0_ar_bits_addr[1]
    DIRECTION OUTPUT TRISTATE ;
    USE SIGNAL ;
    ANTENNADIFFAREA 0.795200 ;
    PORT
      LAYER met3 ;
        RECT 0.000 707.240 4.000 707.840 ;
    END
  END mmio_axi4_0_ar_bits_addr[1]
  PIN mmio_axi4_0_ar_bits_addr[20]
    DIRECTION OUTPUT TRISTATE ;
    USE SIGNAL ;
    ANTENNADIFFAREA 0.795200 ;
    PORT
      LAYER met3 ;
        RECT 6996.000 2492.240 7000.000 2492.840 ;
    END
  END mmio_axi4_0_ar_bits_addr[20]
  PIN mmio_axi4_0_ar_bits_addr[21]
    DIRECTION OUTPUT TRISTATE ;
    USE SIGNAL ;
    ANTENNADIFFAREA 0.795200 ;
    PORT
      LAYER met2 ;
        RECT 5892.690 2596.000 5892.970 2600.000 ;
    END
  END mmio_axi4_0_ar_bits_addr[21]
  PIN mmio_axi4_0_ar_bits_addr[22]
    DIRECTION OUTPUT TRISTATE ;
    USE SIGNAL ;
    ANTENNADIFFAREA 0.795200 ;
    PORT
      LAYER met2 ;
        RECT 3355.330 0.000 3355.610 4.000 ;
    END
  END mmio_axi4_0_ar_bits_addr[22]
  PIN mmio_axi4_0_ar_bits_addr[23]
    DIRECTION OUTPUT TRISTATE ;
    USE SIGNAL ;
    ANTENNADIFFAREA 0.795200 ;
    PORT
      LAYER met2 ;
        RECT 2682.350 0.000 2682.630 4.000 ;
    END
  END mmio_axi4_0_ar_bits_addr[23]
  PIN mmio_axi4_0_ar_bits_addr[24]
    DIRECTION OUTPUT TRISTATE ;
    USE SIGNAL ;
    ANTENNADIFFAREA 0.795200 ;
    PORT
      LAYER met3 ;
        RECT 0.000 244.840 4.000 245.440 ;
    END
  END mmio_axi4_0_ar_bits_addr[24]
  PIN mmio_axi4_0_ar_bits_addr[25]
    DIRECTION OUTPUT TRISTATE ;
    USE SIGNAL ;
    ANTENNADIFFAREA 0.795200 ;
    PORT
      LAYER met2 ;
        RECT 6977.830 0.000 6978.110 4.000 ;
    END
  END mmio_axi4_0_ar_bits_addr[25]
  PIN mmio_axi4_0_ar_bits_addr[26]
    DIRECTION OUTPUT TRISTATE ;
    USE SIGNAL ;
    ANTENNADIFFAREA 0.795200 ;
    PORT
      LAYER met2 ;
        RECT 2247.650 0.000 2247.930 4.000 ;
    END
  END mmio_axi4_0_ar_bits_addr[26]
  PIN mmio_axi4_0_ar_bits_addr[27]
    DIRECTION OUTPUT TRISTATE ;
    USE SIGNAL ;
    ANTENNADIFFAREA 0.795200 ;
    PORT
      LAYER met2 ;
        RECT 2804.710 2596.000 2804.990 2600.000 ;
    END
  END mmio_axi4_0_ar_bits_addr[27]
  PIN mmio_axi4_0_ar_bits_addr[28]
    DIRECTION OUTPUT TRISTATE ;
    USE SIGNAL ;
    ANTENNADIFFAREA 0.795200 ;
    PORT
      LAYER met2 ;
        RECT 4227.950 0.000 4228.230 4.000 ;
    END
  END mmio_axi4_0_ar_bits_addr[28]
  PIN mmio_axi4_0_ar_bits_addr[29]
    DIRECTION OUTPUT TRISTATE ;
    USE SIGNAL ;
    ANTENNADIFFAREA 0.795200 ;
    PORT
      LAYER met2 ;
        RECT 5435.450 0.000 5435.730 4.000 ;
    END
  END mmio_axi4_0_ar_bits_addr[29]
  PIN mmio_axi4_0_ar_bits_addr[2]
    DIRECTION OUTPUT TRISTATE ;
    USE SIGNAL ;
    ANTENNADIFFAREA 0.795200 ;
    PORT
      LAYER met2 ;
        RECT 1796.850 2596.000 1797.130 2600.000 ;
    END
  END mmio_axi4_0_ar_bits_addr[2]
  PIN mmio_axi4_0_ar_bits_addr[30]
    DIRECTION OUTPUT TRISTATE ;
    USE SIGNAL ;
    ANTENNADIFFAREA 0.795200 ;
    PORT
      LAYER met2 ;
        RECT 1677.710 0.000 1677.990 4.000 ;
    END
  END mmio_axi4_0_ar_bits_addr[30]
  PIN mmio_axi4_0_ar_bits_addr[3]
    DIRECTION OUTPUT TRISTATE ;
    USE SIGNAL ;
    ANTENNADIFFAREA 0.795200 ;
    PORT
      LAYER met2 ;
        RECT 2402.210 2596.000 2402.490 2600.000 ;
    END
  END mmio_axi4_0_ar_bits_addr[3]
  PIN mmio_axi4_0_ar_bits_addr[4]
    DIRECTION OUTPUT TRISTATE ;
    USE SIGNAL ;
    ANTENNADIFFAREA 0.795200 ;
    PORT
      LAYER met2 ;
        RECT 3152.470 0.000 3152.750 4.000 ;
    END
  END mmio_axi4_0_ar_bits_addr[4]
  PIN mmio_axi4_0_ar_bits_addr[5]
    DIRECTION OUTPUT TRISTATE ;
    USE SIGNAL ;
    ANTENNADIFFAREA 0.795200 ;
    PORT
      LAYER met2 ;
        RECT 1629.410 2596.000 1629.690 2600.000 ;
    END
  END mmio_axi4_0_ar_bits_addr[5]
  PIN mmio_axi4_0_ar_bits_addr[6]
    DIRECTION OUTPUT TRISTATE ;
    USE SIGNAL ;
    ANTENNADIFFAREA 0.795200 ;
    PORT
      LAYER met2 ;
        RECT 3654.790 0.000 3655.070 4.000 ;
    END
  END mmio_axi4_0_ar_bits_addr[6]
  PIN mmio_axi4_0_ar_bits_addr[7]
    DIRECTION OUTPUT TRISTATE ;
    USE SIGNAL ;
    ANTENNADIFFAREA 0.795200 ;
    PORT
      LAYER met2 ;
        RECT 788.990 2596.000 789.270 2600.000 ;
    END
  END mmio_axi4_0_ar_bits_addr[7]
  PIN mmio_axi4_0_ar_bits_addr[8]
    DIRECTION OUTPUT TRISTATE ;
    USE SIGNAL ;
    ANTENNADIFFAREA 0.795200 ;
    PORT
      LAYER met3 ;
        RECT 0.000 989.440 4.000 990.040 ;
    END
  END mmio_axi4_0_ar_bits_addr[8]
  PIN mmio_axi4_0_ar_bits_addr[9]
    DIRECTION OUTPUT TRISTATE ;
    USE SIGNAL ;
    ANTENNADIFFAREA 0.795200 ;
    PORT
      LAYER met2 ;
        RECT 4495.210 0.000 4495.490 4.000 ;
    END
  END mmio_axi4_0_ar_bits_addr[9]
  PIN mmio_axi4_0_ar_bits_burst[0]
    DIRECTION OUTPUT TRISTATE ;
    USE SIGNAL ;
    PORT
      LAYER met2 ;
        RECT 6845.810 0.000 6846.090 4.000 ;
    END
  END mmio_axi4_0_ar_bits_burst[0]
  PIN mmio_axi4_0_ar_bits_burst[1]
    DIRECTION OUTPUT TRISTATE ;
    USE SIGNAL ;
    PORT
      LAYER met2 ;
        RECT 1226.910 2596.000 1227.190 2600.000 ;
    END
  END mmio_axi4_0_ar_bits_burst[1]
  PIN mmio_axi4_0_ar_bits_cache[0]
    DIRECTION OUTPUT TRISTATE ;
    USE SIGNAL ;
    PORT
      LAYER met2 ;
        RECT 856.610 2596.000 856.890 2600.000 ;
    END
  END mmio_axi4_0_ar_bits_cache[0]
  PIN mmio_axi4_0_ar_bits_cache[1]
    DIRECTION OUTPUT TRISTATE ;
    USE SIGNAL ;
    PORT
      LAYER met2 ;
        RECT 1139.970 0.000 1140.250 4.000 ;
    END
  END mmio_axi4_0_ar_bits_cache[1]
  PIN mmio_axi4_0_ar_bits_cache[2]
    DIRECTION OUTPUT TRISTATE ;
    USE SIGNAL ;
    PORT
      LAYER met2 ;
        RECT 1561.790 2596.000 1562.070 2600.000 ;
    END
  END mmio_axi4_0_ar_bits_cache[2]
  PIN mmio_axi4_0_ar_bits_cache[3]
    DIRECTION OUTPUT TRISTATE ;
    USE SIGNAL ;
    PORT
      LAYER met2 ;
        RECT 3387.530 0.000 3387.810 4.000 ;
    END
  END mmio_axi4_0_ar_bits_cache[3]
  PIN mmio_axi4_0_ar_bits_id[0]
    DIRECTION OUTPUT TRISTATE ;
    USE SIGNAL ;
    PORT
      LAYER met3 ;
        RECT 0.000 955.440 4.000 956.040 ;
    END
  END mmio_axi4_0_ar_bits_id[0]
  PIN mmio_axi4_0_ar_bits_id[1]
    DIRECTION OUTPUT TRISTATE ;
    USE SIGNAL ;
    PORT
      LAYER met2 ;
        RECT 2637.270 2596.000 2637.550 2600.000 ;
    END
  END mmio_axi4_0_ar_bits_id[1]
  PIN mmio_axi4_0_ar_bits_id[2]
    DIRECTION OUTPUT TRISTATE ;
    USE SIGNAL ;
    PORT
      LAYER met2 ;
        RECT 4211.850 2596.000 4212.130 2600.000 ;
    END
  END mmio_axi4_0_ar_bits_id[2]
  PIN mmio_axi4_0_ar_bits_id[3]
    DIRECTION OUTPUT TRISTATE ;
    USE SIGNAL ;
    PORT
      LAYER met2 ;
        RECT 3307.030 2596.000 3307.310 2600.000 ;
    END
  END mmio_axi4_0_ar_bits_id[3]
  PIN mmio_axi4_0_ar_bits_len[0]
    DIRECTION OUTPUT TRISTATE ;
    USE SIGNAL ;
    PORT
      LAYER met2 ;
        RECT 3522.770 0.000 3523.050 4.000 ;
    END
  END mmio_axi4_0_ar_bits_len[0]
  PIN mmio_axi4_0_ar_bits_len[1]
    DIRECTION OUTPUT TRISTATE ;
    USE SIGNAL ;
    PORT
      LAYER met2 ;
        RECT 5870.150 0.000 5870.430 4.000 ;
    END
  END mmio_axi4_0_ar_bits_len[1]
  PIN mmio_axi4_0_ar_bits_len[2]
    DIRECTION OUTPUT TRISTATE ;
    USE SIGNAL ;
    PORT
      LAYER met2 ;
        RECT 6797.510 2596.000 6797.790 2600.000 ;
    END
  END mmio_axi4_0_ar_bits_len[2]
  PIN mmio_axi4_0_ar_bits_len[3]
    DIRECTION OUTPUT TRISTATE ;
    USE SIGNAL ;
    PORT
      LAYER met2 ;
        RECT 6662.270 2596.000 6662.550 2600.000 ;
    END
  END mmio_axi4_0_ar_bits_len[3]
  PIN mmio_axi4_0_ar_bits_len[4]
    DIRECTION OUTPUT TRISTATE ;
    USE SIGNAL ;
    PORT
      LAYER met2 ;
        RECT 4595.030 0.000 4595.310 4.000 ;
    END
  END mmio_axi4_0_ar_bits_len[4]
  PIN mmio_axi4_0_ar_bits_len[5]
    DIRECTION OUTPUT TRISTATE ;
    USE SIGNAL ;
    PORT
      LAYER met2 ;
        RECT 2044.790 0.000 2045.070 4.000 ;
    END
  END mmio_axi4_0_ar_bits_len[5]
  PIN mmio_axi4_0_ar_bits_len[6]
    DIRECTION OUTPUT TRISTATE ;
    USE SIGNAL ;
    PORT
      LAYER met3 ;
        RECT 0.000 1523.240 4.000 1523.840 ;
    END
  END mmio_axi4_0_ar_bits_len[6]
  PIN mmio_axi4_0_ar_bits_len[7]
    DIRECTION OUTPUT TRISTATE ;
    USE SIGNAL ;
    PORT
      LAYER met3 ;
        RECT 6996.000 2033.240 7000.000 2033.840 ;
    END
  END mmio_axi4_0_ar_bits_len[7]
  PIN mmio_axi4_0_ar_bits_lock
    DIRECTION OUTPUT TRISTATE ;
    USE SIGNAL ;
    PORT
      LAYER met2 ;
        RECT 5100.570 0.000 5100.850 4.000 ;
    END
  END mmio_axi4_0_ar_bits_lock
  PIN mmio_axi4_0_ar_bits_prot[0]
    DIRECTION OUTPUT TRISTATE ;
    USE SIGNAL ;
    PORT
      LAYER met2 ;
        RECT 6697.690 2596.000 6697.970 2600.000 ;
    END
  END mmio_axi4_0_ar_bits_prot[0]
  PIN mmio_axi4_0_ar_bits_prot[1]
    DIRECTION OUTPUT TRISTATE ;
    USE SIGNAL ;
    PORT
      LAYER met2 ;
        RECT 1172.170 0.000 1172.450 4.000 ;
    END
  END mmio_axi4_0_ar_bits_prot[1]
  PIN mmio_axi4_0_ar_bits_prot[2]
    DIRECTION OUTPUT TRISTATE ;
    USE SIGNAL ;
    PORT
      LAYER met2 ;
        RECT 3809.350 2596.000 3809.630 2600.000 ;
    END
  END mmio_axi4_0_ar_bits_prot[2]
  PIN mmio_axi4_0_ar_bits_qos[0]
    DIRECTION OUTPUT TRISTATE ;
    USE SIGNAL ;
    PORT
      LAYER met2 ;
        RECT 4952.450 2596.000 4952.730 2600.000 ;
    END
  END mmio_axi4_0_ar_bits_qos[0]
  PIN mmio_axi4_0_ar_bits_qos[1]
    DIRECTION OUTPUT TRISTATE ;
    USE SIGNAL ;
    PORT
      LAYER met2 ;
        RECT 2769.290 2596.000 2769.570 2600.000 ;
    END
  END mmio_axi4_0_ar_bits_qos[1]
  PIN mmio_axi4_0_ar_bits_qos[2]
    DIRECTION OUTPUT TRISTATE ;
    USE SIGNAL ;
    PORT
      LAYER met3 ;
        RECT 0.000 34.040 4.000 34.640 ;
    END
  END mmio_axi4_0_ar_bits_qos[2]
  PIN mmio_axi4_0_ar_bits_qos[3]
    DIRECTION OUTPUT TRISTATE ;
    USE SIGNAL ;
    PORT
      LAYER met2 ;
        RECT 5857.270 2596.000 5857.550 2600.000 ;
    END
  END mmio_axi4_0_ar_bits_qos[3]
  PIN mmio_axi4_0_ar_bits_size[0]
    DIRECTION OUTPUT TRISTATE ;
    USE SIGNAL ;
    ANTENNADIFFAREA 0.795200 ;
    PORT
      LAYER met3 ;
        RECT 0.000 2019.640 4.000 2020.240 ;
    END
  END mmio_axi4_0_ar_bits_size[0]
  PIN mmio_axi4_0_ar_bits_size[1]
    DIRECTION OUTPUT TRISTATE ;
    USE SIGNAL ;
    ANTENNADIFFAREA 0.795200 ;
    PORT
      LAYER met3 ;
        RECT 0.000 425.040 4.000 425.640 ;
    END
  END mmio_axi4_0_ar_bits_size[1]
  PIN mmio_axi4_0_ar_bits_size[2]
    DIRECTION OUTPUT TRISTATE ;
    USE SIGNAL ;
    PORT
      LAYER met2 ;
        RECT 1697.030 2596.000 1697.310 2600.000 ;
    END
  END mmio_axi4_0_ar_bits_size[2]
  PIN mmio_axi4_0_ar_ready
    DIRECTION INPUT ;
    USE SIGNAL ;
    ANTENNAGATEAREA 0.126000 ;
    PORT
      LAYER met2 ;
        RECT 3319.910 0.000 3320.190 4.000 ;
    END
  END mmio_axi4_0_ar_ready
  PIN mmio_axi4_0_ar_valid
    DIRECTION OUTPUT TRISTATE ;
    USE SIGNAL ;
    ANTENNADIFFAREA 0.795200 ;
    PORT
      LAYER met2 ;
        RECT 6910.210 0.000 6910.490 4.000 ;
    END
  END mmio_axi4_0_ar_valid
  PIN mmio_axi4_0_aw_bits_addr[0]
    DIRECTION OUTPUT TRISTATE ;
    USE SIGNAL ;
    ANTENNADIFFAREA 0.795200 ;
    PORT
      LAYER met2 ;
        RECT 869.490 0.000 869.770 4.000 ;
    END
  END mmio_axi4_0_aw_bits_addr[0]
  PIN mmio_axi4_0_aw_bits_addr[10]
    DIRECTION OUTPUT TRISTATE ;
    USE SIGNAL ;
    ANTENNADIFFAREA 0.795200 ;
    PORT
      LAYER met2 ;
        RECT 1159.290 2596.000 1159.570 2600.000 ;
    END
  END mmio_axi4_0_aw_bits_addr[10]
  PIN mmio_axi4_0_aw_bits_addr[11]
    DIRECTION OUTPUT TRISTATE ;
    USE SIGNAL ;
    ANTENNADIFFAREA 0.795200 ;
    PORT
      LAYER met2 ;
        RECT 2650.150 0.000 2650.430 4.000 ;
    END
  END mmio_axi4_0_aw_bits_addr[11]
  PIN mmio_axi4_0_aw_bits_addr[12]
    DIRECTION OUTPUT TRISTATE ;
    USE SIGNAL ;
    ANTENNADIFFAREA 0.795200 ;
    PORT
      LAYER met2 ;
        RECT 2099.530 2596.000 2099.810 2600.000 ;
    END
  END mmio_axi4_0_aw_bits_addr[12]
  PIN mmio_axi4_0_aw_bits_addr[13]
    DIRECTION OUTPUT TRISTATE ;
    USE SIGNAL ;
    ANTENNADIFFAREA 0.795200 ;
    PORT
      LAYER met2 ;
        RECT 3239.410 2596.000 3239.690 2600.000 ;
    END
  END mmio_axi4_0_aw_bits_addr[13]
  PIN mmio_axi4_0_aw_bits_addr[14]
    DIRECTION OUTPUT TRISTATE ;
    USE SIGNAL ;
    ANTENNADIFFAREA 0.795200 ;
    PORT
      LAYER met3 ;
        RECT 0.000 1662.640 4.000 1663.240 ;
    END
  END mmio_axi4_0_aw_bits_addr[14]
  PIN mmio_axi4_0_aw_bits_addr[15]
    DIRECTION OUTPUT TRISTATE ;
    USE SIGNAL ;
    ANTENNADIFFAREA 0.795200 ;
    PORT
      LAYER met2 ;
        RECT 4830.090 0.000 4830.370 4.000 ;
    END
  END mmio_axi4_0_aw_bits_addr[15]
  PIN mmio_axi4_0_aw_bits_addr[16]
    DIRECTION OUTPUT TRISTATE ;
    USE SIGNAL ;
    ANTENNADIFFAREA 0.795200 ;
    PORT
      LAYER met2 ;
        RECT 186.850 2596.000 187.130 2600.000 ;
    END
  END mmio_axi4_0_aw_bits_addr[16]
  PIN mmio_axi4_0_aw_bits_addr[17]
    DIRECTION OUTPUT TRISTATE ;
    USE SIGNAL ;
    ANTENNADIFFAREA 0.795200 ;
    PORT
      LAYER met2 ;
        RECT 3844.770 2596.000 3845.050 2600.000 ;
    END
  END mmio_axi4_0_aw_bits_addr[17]
  PIN mmio_axi4_0_aw_bits_addr[18]
    DIRECTION OUTPUT TRISTATE ;
    USE SIGNAL ;
    ANTENNADIFFAREA 0.795200 ;
    PORT
      LAYER met2 ;
        RECT 1642.290 0.000 1642.570 4.000 ;
    END
  END mmio_axi4_0_aw_bits_addr[18]
  PIN mmio_axi4_0_aw_bits_addr[19]
    DIRECTION OUTPUT TRISTATE ;
    USE SIGNAL ;
    ANTENNADIFFAREA 0.795200 ;
    PORT
      LAYER met2 ;
        RECT 3709.530 2596.000 3709.810 2600.000 ;
    END
  END mmio_axi4_0_aw_bits_addr[19]
  PIN mmio_axi4_0_aw_bits_addr[1]
    DIRECTION OUTPUT TRISTATE ;
    USE SIGNAL ;
    ANTENNADIFFAREA 0.795200 ;
    PORT
      LAYER met2 ;
        RECT 959.650 2596.000 959.930 2600.000 ;
    END
  END mmio_axi4_0_aw_bits_addr[1]
  PIN mmio_axi4_0_aw_bits_addr[20]
    DIRECTION OUTPUT TRISTATE ;
    USE SIGNAL ;
    ANTENNADIFFAREA 0.795200 ;
    PORT
      LAYER met2 ;
        RECT 3542.090 2596.000 3542.370 2600.000 ;
    END
  END mmio_axi4_0_aw_bits_addr[20]
  PIN mmio_axi4_0_aw_bits_addr[21]
    DIRECTION OUTPUT TRISTATE ;
    USE SIGNAL ;
    ANTENNADIFFAREA 0.795200 ;
    PORT
      LAYER met2 ;
        RECT 6778.190 0.000 6778.470 4.000 ;
    END
  END mmio_axi4_0_aw_bits_addr[21]
  PIN mmio_axi4_0_aw_bits_addr[22]
    DIRECTION OUTPUT TRISTATE ;
    USE SIGNAL ;
    ANTENNADIFFAREA 0.795200 ;
    PORT
      LAYER met2 ;
        RECT 3790.030 0.000 3790.310 4.000 ;
    END
  END mmio_axi4_0_aw_bits_addr[22]
  PIN mmio_axi4_0_aw_bits_addr[23]
    DIRECTION OUTPUT TRISTATE ;
    USE SIGNAL ;
    ANTENNADIFFAREA 0.795200 ;
    PORT
      LAYER met2 ;
        RECT 5738.130 0.000 5738.410 4.000 ;
    END
  END mmio_axi4_0_aw_bits_addr[23]
  PIN mmio_axi4_0_aw_bits_addr[24]
    DIRECTION OUTPUT TRISTATE ;
    USE SIGNAL ;
    ANTENNADIFFAREA 0.795200 ;
    PORT
      LAYER met3 ;
        RECT 6996.000 758.240 7000.000 758.840 ;
    END
  END mmio_axi4_0_aw_bits_addr[24]
  PIN mmio_axi4_0_aw_bits_addr[25]
    DIRECTION OUTPUT TRISTATE ;
    USE SIGNAL ;
    ANTENNADIFFAREA 0.795200 ;
    PORT
      LAYER met2 ;
        RECT 5554.590 2596.000 5554.870 2600.000 ;
    END
  END mmio_axi4_0_aw_bits_addr[25]
  PIN mmio_axi4_0_aw_bits_addr[26]
    DIRECTION OUTPUT TRISTATE ;
    USE SIGNAL ;
    ANTENNADIFFAREA 0.795200 ;
    PORT
      LAYER met3 ;
        RECT 0.000 741.240 4.000 741.840 ;
    END
  END mmio_axi4_0_aw_bits_addr[26]
  PIN mmio_axi4_0_aw_bits_addr[27]
    DIRECTION OUTPUT TRISTATE ;
    USE SIGNAL ;
    ANTENNADIFFAREA 0.795200 ;
    PORT
      LAYER met2 ;
        RECT 2447.290 0.000 2447.570 4.000 ;
    END
  END mmio_axi4_0_aw_bits_addr[27]
  PIN mmio_axi4_0_aw_bits_addr[28]
    DIRECTION OUTPUT TRISTATE ;
    USE SIGNAL ;
    ANTENNADIFFAREA 0.795200 ;
    PORT
      LAYER met2 ;
        RECT 1326.730 2596.000 1327.010 2600.000 ;
    END
  END mmio_axi4_0_aw_bits_addr[28]
  PIN mmio_axi4_0_aw_bits_addr[29]
    DIRECTION OUTPUT TRISTATE ;
    USE SIGNAL ;
    ANTENNADIFFAREA 0.795200 ;
    PORT
      LAYER met3 ;
        RECT 0.000 1166.240 4.000 1166.840 ;
    END
  END mmio_axi4_0_aw_bits_addr[29]
  PIN mmio_axi4_0_aw_bits_addr[2]
    DIRECTION OUTPUT TRISTATE ;
    USE SIGNAL ;
    ANTENNADIFFAREA 0.795200 ;
    PORT
      LAYER met2 ;
        RECT 299.550 0.000 299.830 4.000 ;
    END
  END mmio_axi4_0_aw_bits_addr[2]
  PIN mmio_axi4_0_aw_bits_addr[30]
    DIRECTION OUTPUT TRISTATE ;
    USE SIGNAL ;
    ANTENNADIFFAREA 0.795200 ;
    PORT
      LAYER met2 ;
        RECT 1339.610 0.000 1339.890 4.000 ;
    END
  END mmio_axi4_0_aw_bits_addr[30]
  PIN mmio_axi4_0_aw_bits_addr[3]
    DIRECTION OUTPUT TRISTATE ;
    USE SIGNAL ;
    ANTENNADIFFAREA 0.795200 ;
    PORT
      LAYER met2 ;
        RECT 5300.210 0.000 5300.490 4.000 ;
    END
  END mmio_axi4_0_aw_bits_addr[3]
  PIN mmio_axi4_0_aw_bits_addr[4]
    DIRECTION OUTPUT TRISTATE ;
    USE SIGNAL ;
    ANTENNADIFFAREA 0.795200 ;
    PORT
      LAYER met3 ;
        RECT 6996.000 1924.440 7000.000 1925.040 ;
    END
  END mmio_axi4_0_aw_bits_addr[4]
  PIN mmio_axi4_0_aw_bits_addr[5]
    DIRECTION OUTPUT TRISTATE ;
    USE SIGNAL ;
    ANTENNADIFFAREA 0.795200 ;
    PORT
      LAYER met2 ;
        RECT 6507.710 0.000 6507.990 4.000 ;
    END
  END mmio_axi4_0_aw_bits_addr[5]
  PIN mmio_axi4_0_aw_bits_addr[6]
    DIRECTION OUTPUT TRISTATE ;
    USE SIGNAL ;
    ANTENNADIFFAREA 0.795200 ;
    PORT
      LAYER met2 ;
        RECT 502.410 0.000 502.690 4.000 ;
    END
  END mmio_axi4_0_aw_bits_addr[6]
  PIN mmio_axi4_0_aw_bits_addr[7]
    DIRECTION OUTPUT TRISTATE ;
    USE SIGNAL ;
    ANTENNADIFFAREA 0.795200 ;
    PORT
      LAYER met2 ;
        RECT 6172.830 0.000 6173.110 4.000 ;
    END
  END mmio_axi4_0_aw_bits_addr[7]
  PIN mmio_axi4_0_aw_bits_addr[8]
    DIRECTION OUTPUT TRISTATE ;
    USE SIGNAL ;
    ANTENNADIFFAREA 0.795200 ;
    PORT
      LAYER met2 ;
        RECT 3220.090 0.000 3220.370 4.000 ;
    END
  END mmio_axi4_0_aw_bits_addr[8]
  PIN mmio_axi4_0_aw_bits_addr[9]
    DIRECTION OUTPUT TRISTATE ;
    USE SIGNAL ;
    ANTENNADIFFAREA 0.795200 ;
    PORT
      LAYER met2 ;
        RECT 3744.950 2596.000 3745.230 2600.000 ;
    END
  END mmio_axi4_0_aw_bits_addr[9]
  PIN mmio_axi4_0_aw_bits_burst[0]
    DIRECTION OUTPUT TRISTATE ;
    USE SIGNAL ;
    PORT
      LAYER met2 ;
        RECT 924.230 2596.000 924.510 2600.000 ;
    END
  END mmio_axi4_0_aw_bits_burst[0]
  PIN mmio_axi4_0_aw_bits_burst[1]
    DIRECTION OUTPUT TRISTATE ;
    USE SIGNAL ;
    PORT
      LAYER met3 ;
        RECT 6996.000 119.040 7000.000 119.640 ;
    END
  END mmio_axi4_0_aw_bits_burst[1]
  PIN mmio_axi4_0_aw_bits_cache[0]
    DIRECTION OUTPUT TRISTATE ;
    USE SIGNAL ;
    PORT
      LAYER met3 ;
        RECT 6996.000 2281.440 7000.000 2282.040 ;
    END
  END mmio_axi4_0_aw_bits_cache[0]
  PIN mmio_axi4_0_aw_bits_cache[1]
    DIRECTION OUTPUT TRISTATE ;
    USE SIGNAL ;
    PORT
      LAYER met2 ;
        RECT 6765.310 2596.000 6765.590 2600.000 ;
    END
  END mmio_axi4_0_aw_bits_cache[1]
  PIN mmio_axi4_0_aw_bits_cache[2]
    DIRECTION OUTPUT TRISTATE ;
    USE SIGNAL ;
    PORT
      LAYER met2 ;
        RECT 5622.210 2596.000 5622.490 2600.000 ;
    END
  END mmio_axi4_0_aw_bits_cache[2]
  PIN mmio_axi4_0_aw_bits_cache[3]
    DIRECTION OUTPUT TRISTATE ;
    USE SIGNAL ;
    PORT
      LAYER met2 ;
        RECT 1191.490 2596.000 1191.770 2600.000 ;
    END
  END mmio_axi4_0_aw_bits_cache[3]
  PIN mmio_axi4_0_aw_bits_id[0]
    DIRECTION OUTPUT TRISTATE ;
    USE SIGNAL ;
    PORT
      LAYER met2 ;
        RECT 3980.010 2596.000 3980.290 2600.000 ;
    END
  END mmio_axi4_0_aw_bits_id[0]
  PIN mmio_axi4_0_aw_bits_id[1]
    DIRECTION OUTPUT TRISTATE ;
    USE SIGNAL ;
    PORT
      LAYER met2 ;
        RECT 1507.050 0.000 1507.330 4.000 ;
    END
  END mmio_axi4_0_aw_bits_id[1]
  PIN mmio_axi4_0_aw_bits_id[2]
    DIRECTION OUTPUT TRISTATE ;
    USE SIGNAL ;
    PORT
      LAYER met2 ;
        RECT 3171.790 2596.000 3172.070 2600.000 ;
    END
  END mmio_axi4_0_aw_bits_id[2]
  PIN mmio_axi4_0_aw_bits_id[3]
    DIRECTION OUTPUT TRISTATE ;
    USE SIGNAL ;
    PORT
      LAYER met2 ;
        RECT 6105.210 0.000 6105.490 4.000 ;
    END
  END mmio_axi4_0_aw_bits_id[3]
  PIN mmio_axi4_0_aw_bits_len[0]
    DIRECTION OUTPUT TRISTATE ;
    USE SIGNAL ;
    PORT
      LAYER met3 ;
        RECT 6996.000 295.840 7000.000 296.440 ;
    END
  END mmio_axi4_0_aw_bits_len[0]
  PIN mmio_axi4_0_aw_bits_len[1]
    DIRECTION OUTPUT TRISTATE ;
    USE SIGNAL ;
    PORT
      LAYER met2 ;
        RECT 1494.170 2596.000 1494.450 2600.000 ;
    END
  END mmio_axi4_0_aw_bits_len[1]
  PIN mmio_axi4_0_aw_bits_len[2]
    DIRECTION OUTPUT TRISTATE ;
    USE SIGNAL ;
    PORT
      LAYER met2 ;
        RECT 3554.970 0.000 3555.250 4.000 ;
    END
  END mmio_axi4_0_aw_bits_len[2]
  PIN mmio_axi4_0_aw_bits_len[3]
    DIRECTION OUTPUT TRISTATE ;
    USE SIGNAL ;
    PORT
      LAYER met3 ;
        RECT 6996.000 1394.040 7000.000 1394.640 ;
    END
  END mmio_axi4_0_aw_bits_len[3]
  PIN mmio_axi4_0_aw_bits_len[4]
    DIRECTION OUTPUT TRISTATE ;
    USE SIGNAL ;
    PORT
      LAYER met3 ;
        RECT 6996.000 792.240 7000.000 792.840 ;
    END
  END mmio_axi4_0_aw_bits_len[4]
  PIN mmio_axi4_0_aw_bits_len[5]
    DIRECTION OUTPUT TRISTATE ;
    USE SIGNAL ;
    PORT
      LAYER met2 ;
        RECT 6865.130 2596.000 6865.410 2600.000 ;
    END
  END mmio_axi4_0_aw_bits_len[5]
  PIN mmio_axi4_0_aw_bits_len[6]
    DIRECTION OUTPUT TRISTATE ;
    USE SIGNAL ;
    PORT
      LAYER met3 ;
        RECT 6996.000 1856.440 7000.000 1857.040 ;
    END
  END mmio_axi4_0_aw_bits_len[6]
  PIN mmio_axi4_0_aw_bits_len[7]
    DIRECTION OUTPUT TRISTATE ;
    USE SIGNAL ;
    PORT
      LAYER met2 ;
        RECT 4295.570 0.000 4295.850 4.000 ;
    END
  END mmio_axi4_0_aw_bits_len[7]
  PIN mmio_axi4_0_aw_bits_lock
    DIRECTION OUTPUT TRISTATE ;
    USE SIGNAL ;
    PORT
      LAYER met2 ;
        RECT 2836.910 2596.000 2837.190 2600.000 ;
    END
  END mmio_axi4_0_aw_bits_lock
  PIN mmio_axi4_0_aw_bits_prot[0]
    DIRECTION OUTPUT TRISTATE ;
    USE SIGNAL ;
    PORT
      LAYER met2 ;
        RECT 2199.350 2596.000 2199.630 2600.000 ;
    END
  END mmio_axi4_0_aw_bits_prot[0]
  PIN mmio_axi4_0_aw_bits_prot[1]
    DIRECTION OUTPUT TRISTATE ;
    USE SIGNAL ;
    PORT
      LAYER met2 ;
        RECT 1294.530 2596.000 1294.810 2600.000 ;
    END
  END mmio_axi4_0_aw_bits_prot[1]
  PIN mmio_axi4_0_aw_bits_prot[2]
    DIRECTION OUTPUT TRISTATE ;
    USE SIGNAL ;
    PORT
      LAYER met2 ;
        RECT 837.290 0.000 837.570 4.000 ;
    END
  END mmio_axi4_0_aw_bits_prot[2]
  PIN mmio_axi4_0_aw_bits_qos[0]
    DIRECTION OUTPUT TRISTATE ;
    USE SIGNAL ;
    PORT
      LAYER met2 ;
        RECT 1275.210 0.000 1275.490 4.000 ;
    END
  END mmio_axi4_0_aw_bits_qos[0]
  PIN mmio_axi4_0_aw_bits_qos[1]
    DIRECTION OUTPUT TRISTATE ;
    USE SIGNAL ;
    PORT
      LAYER met2 ;
        RECT 4427.590 0.000 4427.870 4.000 ;
    END
  END mmio_axi4_0_aw_bits_qos[1]
  PIN mmio_axi4_0_aw_bits_qos[2]
    DIRECTION OUTPUT TRISTATE ;
    USE SIGNAL ;
    PORT
      LAYER met2 ;
        RECT 6037.590 0.000 6037.870 4.000 ;
    END
  END mmio_axi4_0_aw_bits_qos[2]
  PIN mmio_axi4_0_aw_bits_qos[3]
    DIRECTION OUTPUT TRISTATE ;
    USE SIGNAL ;
    PORT
      LAYER met3 ;
        RECT 6996.000 1465.440 7000.000 1466.040 ;
    END
  END mmio_axi4_0_aw_bits_qos[3]
  PIN mmio_axi4_0_aw_bits_size[0]
    DIRECTION OUTPUT TRISTATE ;
    USE SIGNAL ;
    ANTENNADIFFAREA 0.795200 ;
    PORT
      LAYER met3 ;
        RECT 0.000 2196.440 4.000 2197.040 ;
    END
  END mmio_axi4_0_aw_bits_size[0]
  PIN mmio_axi4_0_aw_bits_size[1]
    DIRECTION OUTPUT TRISTATE ;
    USE SIGNAL ;
    ANTENNADIFFAREA 0.795200 ;
    PORT
      LAYER met2 ;
        RECT 4785.010 2596.000 4785.290 2600.000 ;
    END
  END mmio_axi4_0_aw_bits_size[1]
  PIN mmio_axi4_0_aw_bits_size[2]
    DIRECTION OUTPUT TRISTATE ;
    USE SIGNAL ;
    PORT
      LAYER met2 ;
        RECT 4044.410 2596.000 4044.690 2600.000 ;
    END
  END mmio_axi4_0_aw_bits_size[2]
  PIN mmio_axi4_0_aw_ready
    DIRECTION INPUT ;
    USE SIGNAL ;
    ANTENNAGATEAREA 0.990000 ;
    PORT
      LAYER met2 ;
        RECT 51.610 2596.000 51.890 2600.000 ;
    END
  END mmio_axi4_0_aw_ready
  PIN mmio_axi4_0_aw_valid
    DIRECTION OUTPUT TRISTATE ;
    USE SIGNAL ;
    ANTENNADIFFAREA 0.795200 ;
    PORT
      LAYER met2 ;
        RECT 454.110 2596.000 454.390 2600.000 ;
    END
  END mmio_axi4_0_aw_valid
  PIN mmio_axi4_0_b_bits_id[0]
    DIRECTION INPUT ;
    USE SIGNAL ;
    ANTENNAGATEAREA 0.742500 ;
    PORT
      LAYER met2 ;
        RECT 4897.710 0.000 4897.990 4.000 ;
    END
  END mmio_axi4_0_b_bits_id[0]
  PIN mmio_axi4_0_b_bits_id[1]
    DIRECTION INPUT ;
    USE SIGNAL ;
    ANTENNAGATEAREA 0.126000 ;
    PORT
      LAYER met2 ;
        RECT 3777.150 2596.000 3777.430 2600.000 ;
    END
  END mmio_axi4_0_b_bits_id[1]
  PIN mmio_axi4_0_b_bits_id[2]
    DIRECTION INPUT ;
    USE SIGNAL ;
    ANTENNAGATEAREA 0.990000 ;
    PORT
      LAYER met3 ;
        RECT 0.000 778.640 4.000 779.240 ;
    END
  END mmio_axi4_0_b_bits_id[2]
  PIN mmio_axi4_0_b_bits_id[3]
    DIRECTION INPUT ;
    USE SIGNAL ;
    ANTENNAGATEAREA 0.852000 ;
    PORT
      LAYER met3 ;
        RECT 6996.000 1431.440 7000.000 1432.040 ;
    END
  END mmio_axi4_0_b_bits_id[3]
  PIN mmio_axi4_0_b_bits_resp[0]
    DIRECTION INPUT ;
    USE SIGNAL ;
    ANTENNAGATEAREA 0.126000 ;
    PORT
      LAYER met3 ;
        RECT 0.000 1839.440 4.000 1840.040 ;
    END
  END mmio_axi4_0_b_bits_resp[0]
  PIN mmio_axi4_0_b_bits_resp[1]
    DIRECTION INPUT ;
    USE SIGNAL ;
    ANTENNAGATEAREA 0.495000 ;
    PORT
      LAYER met2 ;
        RECT 5522.390 2596.000 5522.670 2600.000 ;
    END
  END mmio_axi4_0_b_bits_resp[1]
  PIN mmio_axi4_0_b_ready
    DIRECTION OUTPUT TRISTATE ;
    USE SIGNAL ;
    ANTENNADIFFAREA 0.795200 ;
    PORT
      LAYER met2 ;
        RECT 6359.590 2596.000 6359.870 2600.000 ;
    END
  END mmio_axi4_0_b_ready
  PIN mmio_axi4_0_b_valid
    DIRECTION INPUT ;
    USE SIGNAL ;
    ANTENNAGATEAREA 0.742500 ;
    PORT
      LAYER met2 ;
        RECT 6562.450 2596.000 6562.730 2600.000 ;
    END
  END mmio_axi4_0_b_valid
  PIN mmio_axi4_0_r_bits_data[0]
    DIRECTION INPUT ;
    USE SIGNAL ;
    ANTENNAGATEAREA 0.126000 ;
    PORT
      LAYER met2 ;
        RECT 286.670 2596.000 286.950 2600.000 ;
    END
  END mmio_axi4_0_r_bits_data[0]
  PIN mmio_axi4_0_r_bits_data[10]
    DIRECTION INPUT ;
    USE SIGNAL ;
    ANTENNAGATEAREA 0.126000 ;
    PORT
      LAYER met2 ;
        RECT 2749.970 0.000 2750.250 4.000 ;
    END
  END mmio_axi4_0_r_bits_data[10]
  PIN mmio_axi4_0_r_bits_data[11]
    DIRECTION INPUT ;
    USE SIGNAL ;
    ANTENNAGATEAREA 0.126000 ;
    PORT
      LAYER met2 ;
        RECT 5052.270 2596.000 5052.550 2600.000 ;
    END
  END mmio_axi4_0_r_bits_data[11]
  PIN mmio_axi4_0_r_bits_data[12]
    DIRECTION INPUT ;
    USE SIGNAL ;
    ANTENNAGATEAREA 0.495000 ;
    PORT
      LAYER met2 ;
        RECT 167.530 0.000 167.810 4.000 ;
    END
  END mmio_axi4_0_r_bits_data[12]
  PIN mmio_axi4_0_r_bits_data[13]
    DIRECTION INPUT ;
    USE SIGNAL ;
    ANTENNAGATEAREA 0.742500 ;
    PORT
      LAYER met2 ;
        RECT 64.490 0.000 64.770 4.000 ;
    END
  END mmio_axi4_0_r_bits_data[13]
  PIN mmio_axi4_0_r_bits_data[14]
    DIRECTION INPUT ;
    USE SIGNAL ;
    ANTENNAGATEAREA 0.126000 ;
    PORT
      LAYER met2 ;
        RECT 521.730 2596.000 522.010 2600.000 ;
    END
  END mmio_axi4_0_r_bits_data[14]
  PIN mmio_axi4_0_r_bits_data[15]
    DIRECTION INPUT ;
    USE SIGNAL ;
    ANTENNAGATEAREA 0.126000 ;
    PORT
      LAYER met3 ;
        RECT 0.000 2444.640 4.000 2445.240 ;
    END
  END mmio_axi4_0_r_bits_data[15]
  PIN mmio_axi4_0_r_bits_data[16]
    DIRECTION INPUT ;
    USE SIGNAL ;
    ANTENNAGATEAREA 0.495000 ;
    PORT
      LAYER met2 ;
        RECT 5602.890 0.000 5603.170 4.000 ;
    END
  END mmio_axi4_0_r_bits_data[16]
  PIN mmio_axi4_0_r_bits_data[17]
    DIRECTION INPUT ;
    USE SIGNAL ;
    ANTENNAGATEAREA 0.126000 ;
    PORT
      LAYER met2 ;
        RECT 5490.190 2596.000 5490.470 2600.000 ;
    END
  END mmio_axi4_0_r_bits_data[17]
  PIN mmio_axi4_0_r_bits_data[18]
    DIRECTION INPUT ;
    USE SIGNAL ;
    ANTENNAGATEAREA 0.742500 ;
    PORT
      LAYER met2 ;
        RECT 6005.390 0.000 6005.670 4.000 ;
    END
  END mmio_axi4_0_r_bits_data[18]
  PIN mmio_axi4_0_r_bits_data[19]
    DIRECTION INPUT ;
    USE SIGNAL ;
    ANTENNAGATEAREA 0.126000 ;
    PORT
      LAYER met2 ;
        RECT 2366.790 2596.000 2367.070 2600.000 ;
    END
  END mmio_axi4_0_r_bits_data[19]
  PIN mmio_axi4_0_r_bits_data[1]
    DIRECTION INPUT ;
    USE SIGNAL ;
    ANTENNAGATEAREA 0.126000 ;
    PORT
      LAYER met3 ;
        RECT 0.000 2335.840 4.000 2336.440 ;
    END
  END mmio_axi4_0_r_bits_data[1]
  PIN mmio_axi4_0_r_bits_data[20]
    DIRECTION INPUT ;
    USE SIGNAL ;
    ANTENNAGATEAREA 0.126000 ;
    PORT
      LAYER met2 ;
        RECT 1040.150 0.000 1040.430 4.000 ;
    END
  END mmio_axi4_0_r_bits_data[20]
  PIN mmio_axi4_0_r_bits_data[21]
    DIRECTION INPUT ;
    USE SIGNAL ;
    ANTENNAGATEAREA 0.126000 ;
    PORT
      LAYER met2 ;
        RECT 2347.470 0.000 2347.750 4.000 ;
    END
  END mmio_axi4_0_r_bits_data[21]
  PIN mmio_axi4_0_r_bits_data[22]
    DIRECTION INPUT ;
    USE SIGNAL ;
    ANTENNAGATEAREA 0.126000 ;
    PORT
      LAYER met2 ;
        RECT 4917.030 2596.000 4917.310 2600.000 ;
    END
  END mmio_axi4_0_r_bits_data[22]
  PIN mmio_axi4_0_r_bits_data[23]
    DIRECTION INPUT ;
    USE SIGNAL ;
    ANTENNAGATEAREA 0.126000 ;
    PORT
      LAYER met2 ;
        RECT 4260.150 0.000 4260.430 4.000 ;
    END
  END mmio_axi4_0_r_bits_data[23]
  PIN mmio_axi4_0_r_bits_data[24]
    DIRECTION INPUT ;
    USE SIGNAL ;
    ANTENNAGATEAREA 0.213000 ;
    PORT
      LAYER met2 ;
        RECT 2012.590 0.000 2012.870 4.000 ;
    END
  END mmio_axi4_0_r_bits_data[24]
  PIN mmio_axi4_0_r_bits_data[25]
    DIRECTION INPUT ;
    USE SIGNAL ;
    ANTENNAGATEAREA 0.126000 ;
    PORT
      LAYER met2 ;
        RECT 1661.610 2596.000 1661.890 2600.000 ;
    END
  END mmio_axi4_0_r_bits_data[25]
  PIN mmio_axi4_0_r_bits_data[26]
    DIRECTION INPUT ;
    USE SIGNAL ;
    ANTENNAGATEAREA 0.126000 ;
    PORT
      LAYER met3 ;
        RECT 0.000 1734.040 4.000 1734.640 ;
    END
  END mmio_axi4_0_r_bits_data[26]
  PIN mmio_axi4_0_r_bits_data[27]
    DIRECTION INPUT ;
    USE SIGNAL ;
    ANTENNAGATEAREA 0.196500 ;
    PORT
      LAYER met3 ;
        RECT 6996.000 1961.840 7000.000 1962.440 ;
    END
  END mmio_axi4_0_r_bits_data[27]
  PIN mmio_axi4_0_r_bits_data[28]
    DIRECTION INPUT ;
    USE SIGNAL ;
    ANTENNAGATEAREA 0.126000 ;
    PORT
      LAYER met2 ;
        RECT 4092.710 0.000 4092.990 4.000 ;
    END
  END mmio_axi4_0_r_bits_data[28]
  PIN mmio_axi4_0_r_bits_data[29]
    DIRECTION INPUT ;
    USE SIGNAL ;
    ANTENNAGATEAREA 0.213000 ;
    PORT
      LAYER met2 ;
        RECT 2334.590 2596.000 2334.870 2600.000 ;
    END
  END mmio_axi4_0_r_bits_data[29]
  PIN mmio_axi4_0_r_bits_data[2]
    DIRECTION INPUT ;
    USE SIGNAL ;
    ANTENNAGATEAREA 0.495000 ;
    PORT
      LAYER met2 ;
        RECT 5232.590 0.000 5232.870 4.000 ;
    END
  END mmio_axi4_0_r_bits_data[2]
  PIN mmio_axi4_0_r_bits_data[30]
    DIRECTION INPUT ;
    USE SIGNAL ;
    ANTENNAGATEAREA 0.213000 ;
    PORT
      LAYER met2 ;
        RECT 1362.150 2596.000 1362.430 2600.000 ;
    END
  END mmio_axi4_0_r_bits_data[30]
  PIN mmio_axi4_0_r_bits_data[31]
    DIRECTION INPUT ;
    USE SIGNAL ;
    ANTENNAGATEAREA 0.126000 ;
    PORT
      LAYER met2 ;
        RECT 4247.270 2596.000 4247.550 2600.000 ;
    END
  END mmio_axi4_0_r_bits_data[31]
  PIN mmio_axi4_0_r_bits_data[32]
    DIRECTION INPUT ;
    USE SIGNAL ;
    ANTENNAGATEAREA 0.213000 ;
    PORT
      LAYER met2 ;
        RECT 322.090 2596.000 322.370 2600.000 ;
    END
  END mmio_axi4_0_r_bits_data[32]
  PIN mmio_axi4_0_r_bits_data[33]
    DIRECTION INPUT ;
    USE SIGNAL ;
    ANTENNAGATEAREA 0.126000 ;
    PORT
      LAYER met2 ;
        RECT 3992.890 0.000 3993.170 4.000 ;
    END
  END mmio_axi4_0_r_bits_data[33]
  PIN mmio_axi4_0_r_bits_data[34]
    DIRECTION INPUT ;
    USE SIGNAL ;
    ANTENNAGATEAREA 0.990000 ;
    PORT
      LAYER met2 ;
        RECT 219.050 2596.000 219.330 2600.000 ;
    END
  END mmio_axi4_0_r_bits_data[34]
  PIN mmio_axi4_0_r_bits_data[35]
    DIRECTION INPUT ;
    USE SIGNAL ;
    ANTENNAGATEAREA 0.495000 ;
    PORT
      LAYER met2 ;
        RECT 5770.330 0.000 5770.610 4.000 ;
    END
  END mmio_axi4_0_r_bits_data[35]
  PIN mmio_axi4_0_r_bits_data[36]
    DIRECTION INPUT ;
    USE SIGNAL ;
    ANTENNAGATEAREA 0.126000 ;
    PORT
      LAYER met2 ;
        RECT 3876.970 2596.000 3877.250 2600.000 ;
    END
  END mmio_axi4_0_r_bits_data[36]
  PIN mmio_axi4_0_r_bits_data[37]
    DIRECTION INPUT ;
    USE SIGNAL ;
    ANTENNAGATEAREA 0.126000 ;
    PORT
      LAYER met2 ;
        RECT 4865.510 0.000 4865.790 4.000 ;
    END
  END mmio_axi4_0_r_bits_data[37]
  PIN mmio_axi4_0_r_bits_data[38]
    DIRECTION INPUT ;
    USE SIGNAL ;
    ANTENNAGATEAREA 0.126000 ;
    PORT
      LAYER met2 ;
        RECT 2064.110 2596.000 2064.390 2600.000 ;
    END
  END mmio_axi4_0_r_bits_data[38]
  PIN mmio_axi4_0_r_bits_data[39]
    DIRECTION INPUT ;
    USE SIGNAL ;
    ANTENNAGATEAREA 0.495000 ;
    PORT
      LAYER met2 ;
        RECT 669.850 0.000 670.130 4.000 ;
    END
  END mmio_axi4_0_r_bits_data[39]
  PIN mmio_axi4_0_r_bits_data[3]
    DIRECTION INPUT ;
    USE SIGNAL ;
    ANTENNAGATEAREA 0.495000 ;
    PORT
      LAYER met3 ;
        RECT 6996.000 863.640 7000.000 864.240 ;
    END
  END mmio_axi4_0_r_bits_data[3]
  PIN mmio_axi4_0_r_bits_data[40]
    DIRECTION INPUT ;
    USE SIGNAL ;
    ANTENNAGATEAREA 0.126000 ;
    PORT
      LAYER met2 ;
        RECT 2952.830 0.000 2953.110 4.000 ;
    END
  END mmio_axi4_0_r_bits_data[40]
  PIN mmio_axi4_0_r_bits_data[41]
    DIRECTION INPUT ;
    USE SIGNAL ;
    ANTENNAGATEAREA 0.196500 ;
    PORT
      LAYER met3 ;
        RECT 6996.000 1713.640 7000.000 1714.240 ;
    END
  END mmio_axi4_0_r_bits_data[41]
  PIN mmio_axi4_0_r_bits_data[42]
    DIRECTION INPUT ;
    USE SIGNAL ;
    ANTENNAGATEAREA 0.213000 ;
    PORT
      LAYER met2 ;
        RECT 1307.410 0.000 1307.690 4.000 ;
    END
  END mmio_axi4_0_r_bits_data[42]
  PIN mmio_axi4_0_r_bits_data[43]
    DIRECTION INPUT ;
    USE SIGNAL ;
    ANTENNAGATEAREA 0.126000 ;
    PORT
      LAYER met2 ;
        RECT 656.970 2596.000 657.250 2600.000 ;
    END
  END mmio_axi4_0_r_bits_data[43]
  PIN mmio_axi4_0_r_bits_data[44]
    DIRECTION INPUT ;
    USE SIGNAL ;
    ANTENNAGATEAREA 0.126000 ;
    PORT
      LAYER met2 ;
        RECT 2434.410 2596.000 2434.690 2600.000 ;
    END
  END mmio_axi4_0_r_bits_data[44]
  PIN mmio_axi4_0_r_bits_data[45]
    DIRECTION INPUT ;
    USE SIGNAL ;
    ANTENNAGATEAREA 0.126000 ;
    PORT
      LAYER met2 ;
        RECT 5387.150 2596.000 5387.430 2600.000 ;
    END
  END mmio_axi4_0_r_bits_data[45]
  PIN mmio_axi4_0_r_bits_data[46]
    DIRECTION INPUT ;
    USE SIGNAL ;
    ANTENNAGATEAREA 0.495000 ;
    PORT
      LAYER met3 ;
        RECT 6996.000 2244.040 7000.000 2244.640 ;
    END
  END mmio_axi4_0_r_bits_data[46]
  PIN mmio_axi4_0_r_bits_data[47]
    DIRECTION INPUT ;
    USE SIGNAL ;
    ANTENNAGATEAREA 0.126000 ;
    PORT
      LAYER met2 ;
        RECT 2266.970 2596.000 2267.250 2600.000 ;
    END
  END mmio_axi4_0_r_bits_data[47]
  PIN mmio_axi4_0_r_bits_data[48]
    DIRECTION INPUT ;
    USE SIGNAL ;
    ANTENNAGATEAREA 0.742500 ;
    PORT
      LAYER met3 ;
        RECT 0.000 176.840 4.000 177.440 ;
    END
  END mmio_axi4_0_r_bits_data[48]
  PIN mmio_axi4_0_r_bits_data[49]
    DIRECTION INPUT ;
    USE SIGNAL ;
    ANTENNAGATEAREA 0.495000 ;
    PORT
      LAYER met2 ;
        RECT 6073.010 0.000 6073.290 4.000 ;
    END
  END mmio_axi4_0_r_bits_data[49]
  PIN mmio_axi4_0_r_bits_data[4]
    DIRECTION INPUT ;
    USE SIGNAL ;
    ANTENNAGATEAREA 0.213000 ;
    PORT
      LAYER met2 ;
        RECT 1964.290 2596.000 1964.570 2600.000 ;
    END
  END mmio_axi4_0_r_bits_data[4]
  PIN mmio_axi4_0_r_bits_data[50]
    DIRECTION INPUT ;
    USE SIGNAL ;
    ANTENNAGATEAREA 0.852000 ;
    PORT
      LAYER met2 ;
        RECT 6945.630 0.000 6945.910 4.000 ;
    END
  END mmio_axi4_0_r_bits_data[50]
  PIN mmio_axi4_0_r_bits_data[51]
    DIRECTION INPUT ;
    USE SIGNAL ;
    ANTENNAGATEAREA 0.126000 ;
    PORT
      LAYER met2 ;
        RECT 4446.910 2596.000 4447.190 2600.000 ;
    END
  END mmio_axi4_0_r_bits_data[51]
  PIN mmio_axi4_0_r_bits_data[52]
    DIRECTION INPUT ;
    USE SIGNAL ;
    ANTENNAGATEAREA 0.126000 ;
    PORT
      LAYER met2 ;
        RECT 3406.850 2596.000 3407.130 2600.000 ;
    END
  END mmio_axi4_0_r_bits_data[52]
  PIN mmio_axi4_0_r_bits_data[53]
    DIRECTION INPUT ;
    USE SIGNAL ;
    ANTENNAGATEAREA 0.495000 ;
    PORT
      LAYER met3 ;
        RECT 0.000 884.040 4.000 884.640 ;
    END
  END mmio_axi4_0_r_bits_data[53]
  PIN mmio_axi4_0_r_bits_data[54]
    DIRECTION INPUT ;
    USE SIGNAL ;
    ANTENNAGATEAREA 0.426000 ;
    PORT
      LAYER met2 ;
        RECT 466.990 0.000 467.270 4.000 ;
    END
  END mmio_axi4_0_r_bits_data[54]
  PIN mmio_axi4_0_r_bits_data[55]
    DIRECTION INPUT ;
    USE SIGNAL ;
    ANTENNAGATEAREA 0.990000 ;
    PORT
      LAYER met2 ;
        RECT 553.930 2596.000 554.210 2600.000 ;
    END
  END mmio_axi4_0_r_bits_data[55]
  PIN mmio_axi4_0_r_bits_data[56]
    DIRECTION INPUT ;
    USE SIGNAL ;
    ANTENNAGATEAREA 0.495000 ;
    PORT
      LAYER met3 ;
        RECT 6996.000 1995.840 7000.000 1996.440 ;
    END
  END mmio_axi4_0_r_bits_data[56]
  PIN mmio_axi4_0_r_bits_data[57]
    DIRECTION INPUT ;
    USE SIGNAL ;
    ANTENNAGATEAREA 0.196500 ;
    PORT
      LAYER met3 ;
        RECT 6996.000 1642.240 7000.000 1642.840 ;
    END
  END mmio_axi4_0_r_bits_data[57]
  PIN mmio_axi4_0_r_bits_data[58]
    DIRECTION INPUT ;
    USE SIGNAL ;
    ANTENNAGATEAREA 0.495000 ;
    PORT
      LAYER met3 ;
        RECT 0.000 1098.240 4.000 1098.840 ;
    END
  END mmio_axi4_0_r_bits_data[58]
  PIN mmio_axi4_0_r_bits_data[59]
    DIRECTION INPUT ;
    USE SIGNAL ;
    ANTENNAGATEAREA 0.495000 ;
    PORT
      LAYER met3 ;
        RECT 6996.000 1251.240 7000.000 1251.840 ;
    END
  END mmio_axi4_0_r_bits_data[59]
  PIN mmio_axi4_0_r_bits_data[5]
    DIRECTION INPUT ;
    USE SIGNAL ;
    ANTENNAGATEAREA 0.990000 ;
    PORT
      LAYER met2 ;
        RECT 6710.570 0.000 6710.850 4.000 ;
    END
  END mmio_axi4_0_r_bits_data[5]
  PIN mmio_axi4_0_r_bits_data[60]
    DIRECTION INPUT ;
    USE SIGNAL ;
    ANTENNAGATEAREA 0.126000 ;
    PORT
      LAYER met2 ;
        RECT 4933.130 0.000 4933.410 4.000 ;
    END
  END mmio_axi4_0_r_bits_data[60]
  PIN mmio_axi4_0_r_bits_data[61]
    DIRECTION INPUT ;
    USE SIGNAL ;
    ANTENNAGATEAREA 0.126000 ;
    PORT
      LAYER met2 ;
        RECT 4482.330 2596.000 4482.610 2600.000 ;
    END
  END mmio_axi4_0_r_bits_data[61]
  PIN mmio_axi4_0_r_bits_data[62]
    DIRECTION INPUT ;
    USE SIGNAL ;
    ANTENNAGATEAREA 0.126000 ;
    PORT
      LAYER met2 ;
        RECT 5924.890 2596.000 5925.170 2600.000 ;
    END
  END mmio_axi4_0_r_bits_data[62]
  PIN mmio_axi4_0_r_bits_data[63]
    DIRECTION INPUT ;
    USE SIGNAL ;
    ANTENNAGATEAREA 0.426000 ;
    PORT
      LAYER met3 ;
        RECT 0.000 387.640 4.000 388.240 ;
    END
  END mmio_axi4_0_r_bits_data[63]
  PIN mmio_axi4_0_r_bits_data[6]
    DIRECTION INPUT ;
    USE SIGNAL ;
    ANTENNAGATEAREA 0.126000 ;
    PORT
      LAYER met2 ;
        RECT 4124.910 0.000 4125.190 4.000 ;
    END
  END mmio_axi4_0_r_bits_data[6]
  PIN mmio_axi4_0_r_bits_data[7]
    DIRECTION INPUT ;
    USE SIGNAL ;
    ANTENNAGATEAREA 0.742500 ;
    PORT
      LAYER met2 ;
        RECT 6240.450 0.000 6240.730 4.000 ;
    END
  END mmio_axi4_0_r_bits_data[7]
  PIN mmio_axi4_0_r_bits_data[8]
    DIRECTION INPUT ;
    USE SIGNAL ;
    ANTENNAGATEAREA 0.213000 ;
    PORT
      LAYER met3 ;
        RECT 0.000 2125.040 4.000 2125.640 ;
    END
  END mmio_axi4_0_r_bits_data[8]
  PIN mmio_axi4_0_r_bits_data[9]
    DIRECTION INPUT ;
    USE SIGNAL ;
    ANTENNAGATEAREA 0.213000 ;
    PORT
      LAYER met2 ;
        RECT 2785.390 0.000 2785.670 4.000 ;
    END
  END mmio_axi4_0_r_bits_data[9]
  PIN mmio_axi4_0_r_bits_id[0]
    DIRECTION INPUT ;
    USE SIGNAL ;
    ANTENNAGATEAREA 0.213000 ;
    PORT
      LAYER met2 ;
        RECT 534.610 0.000 534.890 4.000 ;
    END
  END mmio_axi4_0_r_bits_id[0]
  PIN mmio_axi4_0_r_bits_id[1]
    DIRECTION INPUT ;
    USE SIGNAL ;
    ANTENNAGATEAREA 0.126000 ;
    PORT
      LAYER met2 ;
        RECT 3039.770 2596.000 3040.050 2600.000 ;
    END
  END mmio_axi4_0_r_bits_id[1]
  PIN mmio_axi4_0_r_bits_id[2]
    DIRECTION INPUT ;
    USE SIGNAL ;
    ANTENNAGATEAREA 0.495000 ;
    PORT
      LAYER met3 ;
        RECT 6996.000 1040.440 7000.000 1041.040 ;
    END
  END mmio_axi4_0_r_bits_id[2]
  PIN mmio_axi4_0_r_bits_id[3]
    DIRECTION INPUT ;
    USE SIGNAL ;
    ANTENNAGATEAREA 0.742500 ;
    PORT
      LAYER met2 ;
        RECT 6594.650 2596.000 6594.930 2600.000 ;
    END
  END mmio_axi4_0_r_bits_id[3]
  PIN mmio_axi4_0_r_bits_last
    DIRECTION INPUT ;
    USE SIGNAL ;
    ANTENNAGATEAREA 0.126000 ;
    PORT
      LAYER met2 ;
        RECT 1977.170 0.000 1977.450 4.000 ;
    END
  END mmio_axi4_0_r_bits_last
  PIN mmio_axi4_0_r_bits_resp[0]
    DIRECTION INPUT ;
    USE SIGNAL ;
    ANTENNAGATEAREA 0.126000 ;
    PORT
      LAYER met2 ;
        RECT 5354.950 2596.000 5355.230 2600.000 ;
    END
  END mmio_axi4_0_r_bits_resp[0]
  PIN mmio_axi4_0_r_bits_resp[1]
    DIRECTION INPUT ;
    USE SIGNAL ;
    ANTENNAGATEAREA 0.990000 ;
    PORT
      LAYER met3 ;
        RECT 6996.000 153.040 7000.000 153.640 ;
    END
  END mmio_axi4_0_r_bits_resp[1]
  PIN mmio_axi4_0_r_ready
    DIRECTION OUTPUT TRISTATE ;
    USE SIGNAL ;
    ANTENNADIFFAREA 0.795200 ;
    PORT
      LAYER met2 ;
        RECT 3925.270 0.000 3925.550 4.000 ;
    END
  END mmio_axi4_0_r_ready
  PIN mmio_axi4_0_r_valid
    DIRECTION INPUT ;
    USE SIGNAL ;
    ANTENNAGATEAREA 0.196500 ;
    PORT
      LAYER met2 ;
        RECT 5287.330 2596.000 5287.610 2600.000 ;
    END
  END mmio_axi4_0_r_valid
  PIN mmio_axi4_0_w_bits_data[0]
    DIRECTION OUTPUT TRISTATE ;
    USE SIGNAL ;
    ANTENNADIFFAREA 0.795200 ;
    PORT
      LAYER met2 ;
        RECT 3757.830 0.000 3758.110 4.000 ;
    END
  END mmio_axi4_0_w_bits_data[0]
  PIN mmio_axi4_0_w_bits_data[10]
    DIRECTION OUTPUT TRISTATE ;
    USE SIGNAL ;
    ANTENNADIFFAREA 0.795200 ;
    PORT
      LAYER met2 ;
        RECT 1574.670 0.000 1574.950 4.000 ;
    END
  END mmio_axi4_0_w_bits_data[10]
  PIN mmio_axi4_0_w_bits_data[11]
    DIRECTION OUTPUT TRISTATE ;
    USE SIGNAL ;
    ANTENNADIFFAREA 0.795200 ;
    PORT
      LAYER met2 ;
        RECT 231.930 0.000 232.210 4.000 ;
    END
  END mmio_axi4_0_w_bits_data[11]
  PIN mmio_axi4_0_w_bits_data[12]
    DIRECTION OUTPUT TRISTATE ;
    USE SIGNAL ;
    ANTENNADIFFAREA 0.795200 ;
    PORT
      LAYER met2 ;
        RECT 4997.530 0.000 4997.810 4.000 ;
    END
  END mmio_axi4_0_w_bits_data[12]
  PIN mmio_axi4_0_w_bits_data[13]
    DIRECTION OUTPUT TRISTATE ;
    USE SIGNAL ;
    ANTENNADIFFAREA 0.795200 ;
    PORT
      LAYER met2 ;
        RECT 6375.690 0.000 6375.970 4.000 ;
    END
  END mmio_axi4_0_w_bits_data[13]
  PIN mmio_axi4_0_w_bits_data[14]
    DIRECTION OUTPUT TRISTATE ;
    USE SIGNAL ;
    ANTENNADIFFAREA 0.795200 ;
    PORT
      LAYER met2 ;
        RECT 3071.970 2596.000 3072.250 2600.000 ;
    END
  END mmio_axi4_0_w_bits_data[14]
  PIN mmio_axi4_0_w_bits_data[15]
    DIRECTION OUTPUT TRISTATE ;
    USE SIGNAL ;
    ANTENNADIFFAREA 0.795200 ;
    PORT
      LAYER met3 ;
        RECT 0.000 1237.640 4.000 1238.240 ;
    END
  END mmio_axi4_0_w_bits_data[15]
  PIN mmio_axi4_0_w_bits_data[16]
    DIRECTION OUTPUT TRISTATE ;
    USE SIGNAL ;
    ANTENNADIFFAREA 0.795200 ;
    PORT
      LAYER met2 ;
        RECT 421.910 2596.000 422.190 2600.000 ;
    END
  END mmio_axi4_0_w_bits_data[16]
  PIN mmio_axi4_0_w_bits_data[17]
    DIRECTION OUTPUT TRISTATE ;
    USE SIGNAL ;
    ANTENNADIFFAREA 0.795200 ;
    PORT
      LAYER met2 ;
        RECT 756.790 2596.000 757.070 2600.000 ;
    END
  END mmio_axi4_0_w_bits_data[17]
  PIN mmio_axi4_0_w_bits_data[18]
    DIRECTION OUTPUT TRISTATE ;
    USE SIGNAL ;
    ANTENNADIFFAREA 0.795200 ;
    PORT
      LAYER met2 ;
        RECT 621.550 2596.000 621.830 2600.000 ;
    END
  END mmio_axi4_0_w_bits_data[18]
  PIN mmio_axi4_0_w_bits_data[19]
    DIRECTION OUTPUT TRISTATE ;
    USE SIGNAL ;
    ANTENNADIFFAREA 0.795200 ;
    PORT
      LAYER met2 ;
        RECT 199.730 0.000 200.010 4.000 ;
    END
  END mmio_axi4_0_w_bits_data[19]
  PIN mmio_axi4_0_w_bits_data[1]
    DIRECTION OUTPUT TRISTATE ;
    USE SIGNAL ;
    ANTENNADIFFAREA 0.795200 ;
    PORT
      LAYER met3 ;
        RECT 0.000 459.040 4.000 459.640 ;
    END
  END mmio_axi4_0_w_bits_data[1]
  PIN mmio_axi4_0_w_bits_data[20]
    DIRECTION OUTPUT TRISTATE ;
    USE SIGNAL ;
    ANTENNADIFFAREA 0.795200 ;
    PORT
      LAYER met3 ;
        RECT 6996.000 578.040 7000.000 578.640 ;
    END
  END mmio_axi4_0_w_bits_data[20]
  PIN mmio_axi4_0_w_bits_data[21]
    DIRECTION OUTPUT TRISTATE ;
    USE SIGNAL ;
    ANTENNADIFFAREA 0.795200 ;
    PORT
      LAYER met2 ;
        RECT 2849.790 0.000 2850.070 4.000 ;
    END
  END mmio_axi4_0_w_bits_data[21]
  PIN mmio_axi4_0_w_bits_data[22]
    DIRECTION OUTPUT TRISTATE ;
    USE SIGNAL ;
    ANTENNADIFFAREA 0.795200 ;
    PORT
      LAYER met2 ;
        RECT 4984.650 2596.000 4984.930 2600.000 ;
    END
  END mmio_axi4_0_w_bits_data[22]
  PIN mmio_axi4_0_w_bits_data[23]
    DIRECTION OUTPUT TRISTATE ;
    USE SIGNAL ;
    ANTENNADIFFAREA 0.795200 ;
    PORT
      LAYER met2 ;
        RECT 6192.150 2596.000 6192.430 2600.000 ;
    END
  END mmio_axi4_0_w_bits_data[23]
  PIN mmio_axi4_0_w_bits_data[24]
    DIRECTION OUTPUT TRISTATE ;
    USE SIGNAL ;
    ANTENNADIFFAREA 0.795200 ;
    PORT
      LAYER met2 ;
        RECT 1896.670 2596.000 1896.950 2600.000 ;
    END
  END mmio_axi4_0_w_bits_data[24]
  PIN mmio_axi4_0_w_bits_data[25]
    DIRECTION OUTPUT TRISTATE ;
    USE SIGNAL ;
    ANTENNADIFFAREA 0.795200 ;
    PORT
      LAYER met2 ;
        RECT 769.670 0.000 769.950 4.000 ;
    END
  END mmio_axi4_0_w_bits_data[25]
  PIN mmio_axi4_0_w_bits_data[26]
    DIRECTION OUTPUT TRISTATE ;
    USE SIGNAL ;
    ANTENNADIFFAREA 0.795200 ;
    PORT
      LAYER met3 ;
        RECT 6996.000 969.040 7000.000 969.640 ;
    END
  END mmio_axi4_0_w_bits_data[26]
  PIN mmio_axi4_0_w_bits_data[27]
    DIRECTION OUTPUT TRISTATE ;
    USE SIGNAL ;
    ANTENNADIFFAREA 0.795200 ;
    PORT
      LAYER met2 ;
        RECT 6395.010 2596.000 6395.290 2600.000 ;
    END
  END mmio_axi4_0_w_bits_data[27]
  PIN mmio_axi4_0_w_bits_data[28]
    DIRECTION OUTPUT TRISTATE ;
    USE SIGNAL ;
    ANTENNADIFFAREA 0.795200 ;
    PORT
      LAYER met3 ;
        RECT 0.000 2267.840 4.000 2268.440 ;
    END
  END mmio_axi4_0_w_bits_data[28]
  PIN mmio_axi4_0_w_bits_data[29]
    DIRECTION OUTPUT TRISTATE ;
    USE SIGNAL ;
    ANTENNADIFFAREA 0.795200 ;
    PORT
      LAYER met3 ;
        RECT 6996.000 1890.440 7000.000 1891.040 ;
    END
  END mmio_axi4_0_w_bits_data[29]
  PIN mmio_axi4_0_w_bits_data[2]
    DIRECTION OUTPUT TRISTATE ;
    USE SIGNAL ;
    ANTENNADIFFAREA 0.795200 ;
    PORT
      LAYER met2 ;
        RECT 6543.130 0.000 6543.410 4.000 ;
    END
  END mmio_axi4_0_w_bits_data[2]
  PIN mmio_axi4_0_w_bits_data[30]
    DIRECTION OUTPUT TRISTATE ;
    USE SIGNAL ;
    ANTENNADIFFAREA 0.795200 ;
    PORT
      LAYER met3 ;
        RECT 0.000 139.440 4.000 140.040 ;
    END
  END mmio_axi4_0_w_bits_data[30]
  PIN mmio_axi4_0_w_bits_data[31]
    DIRECTION OUTPUT TRISTATE ;
    USE SIGNAL ;
    ANTENNADIFFAREA 0.795200 ;
    PORT
      LAYER met2 ;
        RECT 5825.070 2596.000 5825.350 2600.000 ;
    END
  END mmio_axi4_0_w_bits_data[31]
  PIN mmio_axi4_0_w_bits_data[32]
    DIRECTION OUTPUT TRISTATE ;
    USE SIGNAL ;
    ANTENNADIFFAREA 0.795200 ;
    PORT
      LAYER met2 ;
        RECT 2936.730 2596.000 2937.010 2600.000 ;
    END
  END mmio_axi4_0_w_bits_data[32]
  PIN mmio_axi4_0_w_bits_data[33]
    DIRECTION OUTPUT TRISTATE ;
    USE SIGNAL ;
    ANTENNADIFFAREA 0.795200 ;
    PORT
      LAYER met2 ;
        RECT 1542.470 0.000 1542.750 4.000 ;
    END
  END mmio_axi4_0_w_bits_data[33]
  PIN mmio_axi4_0_w_bits_data[34]
    DIRECTION OUTPUT TRISTATE ;
    USE SIGNAL ;
    ANTENNADIFFAREA 0.795200 ;
    PORT
      LAYER met3 ;
        RECT 6996.000 935.040 7000.000 935.640 ;
    END
  END mmio_axi4_0_w_bits_data[34]
  PIN mmio_axi4_0_w_bits_data[35]
    DIRECTION OUTPUT TRISTATE ;
    USE SIGNAL ;
    ANTENNADIFFAREA 0.795200 ;
    PORT
      LAYER met2 ;
        RECT 4025.090 0.000 4025.370 4.000 ;
    END
  END mmio_axi4_0_w_bits_data[35]
  PIN mmio_axi4_0_w_bits_data[36]
    DIRECTION OUTPUT TRISTATE ;
    USE SIGNAL ;
    ANTENNADIFFAREA 0.795200 ;
    PORT
      LAYER met2 ;
        RECT 6340.270 0.000 6340.550 4.000 ;
    END
  END mmio_axi4_0_w_bits_data[36]
  PIN mmio_axi4_0_w_bits_data[37]
    DIRECTION OUTPUT TRISTATE ;
    USE SIGNAL ;
    ANTENNADIFFAREA 0.795200 ;
    PORT
      LAYER met3 ;
        RECT 0.000 918.040 4.000 918.640 ;
    END
  END mmio_axi4_0_w_bits_data[37]
  PIN mmio_axi4_0_w_bits_data[38]
    DIRECTION OUTPUT TRISTATE ;
    USE SIGNAL ;
    ANTENNADIFFAREA 0.795200 ;
    PORT
      LAYER met2 ;
        RECT 5065.150 0.000 5065.430 4.000 ;
    END
  END mmio_axi4_0_w_bits_data[38]
  PIN mmio_axi4_0_w_bits_data[39]
    DIRECTION OUTPUT TRISTATE ;
    USE SIGNAL ;
    ANTENNADIFFAREA 0.795200 ;
    PORT
      LAYER met2 ;
        RECT 805.090 0.000 805.370 4.000 ;
    END
  END mmio_axi4_0_w_bits_data[39]
  PIN mmio_axi4_0_w_bits_data[3]
    DIRECTION OUTPUT TRISTATE ;
    USE SIGNAL ;
    ANTENNADIFFAREA 0.795200 ;
    PORT
      LAYER met2 ;
        RECT 2415.090 0.000 2415.370 4.000 ;
    END
  END mmio_axi4_0_w_bits_data[3]
  PIN mmio_axi4_0_w_bits_data[40]
    DIRECTION OUTPUT TRISTATE ;
    USE SIGNAL ;
    ANTENNADIFFAREA 0.795200 ;
    PORT
      LAYER met3 ;
        RECT 6996.000 13.640 7000.000 14.240 ;
    END
  END mmio_axi4_0_w_bits_data[40]
  PIN mmio_axi4_0_w_bits_data[41]
    DIRECTION OUTPUT TRISTATE ;
    USE SIGNAL ;
    ANTENNADIFFAREA 0.795200 ;
    PORT
      LAYER met2 ;
        RECT 5722.030 2596.000 5722.310 2600.000 ;
    END
  END mmio_axi4_0_w_bits_data[41]
  PIN mmio_axi4_0_w_bits_data[42]
    DIRECTION OUTPUT TRISTATE ;
    USE SIGNAL ;
    ANTENNADIFFAREA 0.795200 ;
    PORT
      LAYER met3 ;
        RECT 6996.000 2352.840 7000.000 2353.440 ;
    END
  END mmio_axi4_0_w_bits_data[42]
  PIN mmio_axi4_0_w_bits_data[43]
    DIRECTION OUTPUT TRISTATE ;
    USE SIGNAL ;
    ANTENNADIFFAREA 0.795200 ;
    PORT
      LAYER met2 ;
        RECT 5132.770 0.000 5133.050 4.000 ;
    END
  END mmio_axi4_0_w_bits_data[43]
  PIN mmio_axi4_0_w_bits_data[44]
    DIRECTION OUTPUT TRISTATE ;
    USE SIGNAL ;
    ANTENNADIFFAREA 0.795200 ;
    PORT
      LAYER met2 ;
        RECT 402.590 0.000 402.870 4.000 ;
    END
  END mmio_axi4_0_w_bits_data[44]
  PIN mmio_axi4_0_w_bits_data[45]
    DIRECTION OUTPUT TRISTATE ;
    USE SIGNAL ;
    ANTENNADIFFAREA 0.795200 ;
    PORT
      LAYER met3 ;
        RECT 6996.000 686.840 7000.000 687.440 ;
    END
  END mmio_axi4_0_w_bits_data[45]
  PIN mmio_axi4_0_w_bits_data[46]
    DIRECTION OUTPUT TRISTATE ;
    USE SIGNAL ;
    ANTENNADIFFAREA 0.795200 ;
    PORT
      LAYER met2 ;
        RECT 99.910 0.000 100.190 4.000 ;
    END
  END mmio_axi4_0_w_bits_data[46]
  PIN mmio_axi4_0_w_bits_data[47]
    DIRECTION OUTPUT TRISTATE ;
    USE SIGNAL ;
    ANTENNADIFFAREA 0.795200 ;
    PORT
      LAYER met3 ;
        RECT 6996.000 2458.240 7000.000 2458.840 ;
    END
  END mmio_axi4_0_w_bits_data[47]
  PIN mmio_axi4_0_w_bits_data[48]
    DIRECTION OUTPUT TRISTATE ;
    USE SIGNAL ;
    ANTENNADIFFAREA 0.795200 ;
    PORT
      LAYER met2 ;
        RECT 5590.010 2596.000 5590.290 2600.000 ;
    END
  END mmio_axi4_0_w_bits_data[48]
  PIN mmio_axi4_0_w_bits_data[49]
    DIRECTION OUTPUT TRISTATE ;
    USE SIGNAL ;
    ANTENNADIFFAREA 0.795200 ;
    PORT
      LAYER met2 ;
        RECT 5400.030 0.000 5400.310 4.000 ;
    END
  END mmio_axi4_0_w_bits_data[49]
  PIN mmio_axi4_0_w_bits_data[4]
    DIRECTION OUTPUT TRISTATE ;
    USE SIGNAL ;
    ANTENNADIFFAREA 0.795200 ;
    PORT
      LAYER met3 ;
        RECT 0.000 601.840 4.000 602.440 ;
    END
  END mmio_axi4_0_w_bits_data[4]
  PIN mmio_axi4_0_w_bits_data[50]
    DIRECTION OUTPUT TRISTATE ;
    USE SIGNAL ;
    ANTENNADIFFAREA 0.795200 ;
    PORT
      LAYER met3 ;
        RECT 0.000 1026.840 4.000 1027.440 ;
    END
  END mmio_axi4_0_w_bits_data[50]
  PIN mmio_axi4_0_w_bits_data[51]
    DIRECTION OUTPUT TRISTATE ;
    USE SIGNAL ;
    ANTENNADIFFAREA 0.795200 ;
    PORT
      LAYER met3 ;
        RECT 0.000 1203.640 4.000 1204.240 ;
    END
  END mmio_axi4_0_w_bits_data[51]
  PIN mmio_axi4_0_w_bits_data[52]
    DIRECTION OUTPUT TRISTATE ;
    USE SIGNAL ;
    ANTENNADIFFAREA 0.795200 ;
    PORT
      LAYER met2 ;
        RECT 3252.290 0.000 3252.570 4.000 ;
    END
  END mmio_axi4_0_w_bits_data[52]
  PIN mmio_axi4_0_w_bits_data[53]
    DIRECTION OUTPUT TRISTATE ;
    USE SIGNAL ;
    ANTENNADIFFAREA 0.795200 ;
    PORT
      LAYER met2 ;
        RECT 0.090 0.000 0.370 4.000 ;
    END
  END mmio_axi4_0_w_bits_data[53]
  PIN mmio_axi4_0_w_bits_data[54]
    DIRECTION OUTPUT TRISTATE ;
    USE SIGNAL ;
    ANTENNADIFFAREA 0.795200 ;
    PORT
      LAYER met2 ;
        RECT 3825.450 0.000 3825.730 4.000 ;
    END
  END mmio_axi4_0_w_bits_data[54]
  PIN mmio_axi4_0_w_bits_data[55]
    DIRECTION OUTPUT TRISTATE ;
    USE SIGNAL ;
    ANTENNADIFFAREA 0.795200 ;
    PORT
      LAYER met3 ;
        RECT 0.000 2087.640 4.000 2088.240 ;
    END
  END mmio_axi4_0_w_bits_data[55]
  PIN mmio_axi4_0_w_bits_data[56]
    DIRECTION OUTPUT TRISTATE ;
    USE SIGNAL ;
    ANTENNADIFFAREA 0.795200 ;
    PORT
      LAYER met2 ;
        RECT 1394.350 2596.000 1394.630 2600.000 ;
    END
  END mmio_axi4_0_w_bits_data[56]
  PIN mmio_axi4_0_w_bits_data[57]
    DIRECTION OUTPUT TRISTATE ;
    USE SIGNAL ;
    ANTENNADIFFAREA 0.795200 ;
    PORT
      LAYER met2 ;
        RECT 3374.650 2596.000 3374.930 2600.000 ;
    END
  END mmio_axi4_0_w_bits_data[57]
  PIN mmio_axi4_0_w_bits_data[58]
    DIRECTION OUTPUT TRISTATE ;
    USE SIGNAL ;
    ANTENNADIFFAREA 0.795200 ;
    PORT
      LAYER met3 ;
        RECT 0.000 1380.440 4.000 1381.040 ;
    END
  END mmio_axi4_0_w_bits_data[58]
  PIN mmio_axi4_0_w_bits_data[59]
    DIRECTION OUTPUT TRISTATE ;
    USE SIGNAL ;
    ANTENNADIFFAREA 0.795200 ;
    PORT
      LAYER met2 ;
        RECT 1004.730 0.000 1005.010 4.000 ;
    END
  END mmio_axi4_0_w_bits_data[59]
  PIN mmio_axi4_0_w_bits_data[5]
    DIRECTION OUTPUT TRISTATE ;
    USE SIGNAL ;
    ANTENNADIFFAREA 0.795200 ;
    PORT
      LAYER met2 ;
        RECT 367.170 0.000 367.450 4.000 ;
    END
  END mmio_axi4_0_w_bits_data[5]
  PIN mmio_axi4_0_w_bits_data[60]
    DIRECTION OUTPUT TRISTATE ;
    USE SIGNAL ;
    ANTENNADIFFAREA 0.795200 ;
    PORT
      LAYER met2 ;
        RECT 4582.150 2596.000 4582.430 2600.000 ;
    END
  END mmio_axi4_0_w_bits_data[60]
  PIN mmio_axi4_0_w_bits_data[61]
    DIRECTION OUTPUT TRISTATE ;
    USE SIGNAL ;
    ANTENNADIFFAREA 0.795200 ;
    PORT
      LAYER met2 ;
        RECT 3509.890 2596.000 3510.170 2600.000 ;
    END
  END mmio_axi4_0_w_bits_data[61]
  PIN mmio_axi4_0_w_bits_data[62]
    DIRECTION OUTPUT TRISTATE ;
    USE SIGNAL ;
    ANTENNADIFFAREA 0.795200 ;
    PORT
      LAYER met2 ;
        RECT 2614.730 0.000 2615.010 4.000 ;
    END
  END mmio_axi4_0_w_bits_data[62]
  PIN mmio_axi4_0_w_bits_data[63]
    DIRECTION OUTPUT TRISTATE ;
    USE SIGNAL ;
    ANTENNADIFFAREA 0.795200 ;
    PORT
      LAYER met2 ;
        RECT 5422.570 2596.000 5422.850 2600.000 ;
    END
  END mmio_axi4_0_w_bits_data[63]
  PIN mmio_axi4_0_w_bits_data[6]
    DIRECTION OUTPUT TRISTATE ;
    USE SIGNAL ;
    ANTENNADIFFAREA 0.795200 ;
    PORT
      LAYER met2 ;
        RECT 6140.630 0.000 6140.910 4.000 ;
    END
  END mmio_axi4_0_w_bits_data[6]
  PIN mmio_axi4_0_w_bits_data[7]
    DIRECTION OUTPUT TRISTATE ;
    USE SIGNAL ;
    ANTENNADIFFAREA 0.795200 ;
    PORT
      LAYER met2 ;
        RECT 489.530 2596.000 489.810 2600.000 ;
    END
  END mmio_axi4_0_w_bits_data[7]
  PIN mmio_axi4_0_w_bits_data[8]
    DIRECTION OUTPUT TRISTATE ;
    USE SIGNAL ;
    ANTENNADIFFAREA 0.795200 ;
    PORT
      LAYER met3 ;
        RECT 6996.000 1570.840 7000.000 1571.440 ;
    END
  END mmio_axi4_0_w_bits_data[8]
  PIN mmio_axi4_0_w_bits_data[9]
    DIRECTION OUTPUT TRISTATE ;
    USE SIGNAL ;
    ANTENNADIFFAREA 0.795200 ;
    PORT
      LAYER met2 ;
        RECT 1072.350 0.000 1072.630 4.000 ;
    END
  END mmio_axi4_0_w_bits_data[9]
  PIN mmio_axi4_0_w_bits_last
    DIRECTION OUTPUT TRISTATE ;
    USE SIGNAL ;
    PORT
      LAYER met2 ;
        RECT 1845.150 0.000 1845.430 4.000 ;
    END
  END mmio_axi4_0_w_bits_last
  PIN mmio_axi4_0_w_bits_strb[0]
    DIRECTION OUTPUT TRISTATE ;
    USE SIGNAL ;
    ANTENNADIFFAREA 0.795200 ;
    PORT
      LAYER met3 ;
        RECT 0.000 316.240 4.000 316.840 ;
    END
  END mmio_axi4_0_w_bits_strb[0]
  PIN mmio_axi4_0_w_bits_strb[1]
    DIRECTION OUTPUT TRISTATE ;
    USE SIGNAL ;
    ANTENNADIFFAREA 0.795200 ;
    PORT
      LAYER met3 ;
        RECT 6996.000 1360.040 7000.000 1360.640 ;
    END
  END mmio_axi4_0_w_bits_strb[1]
  PIN mmio_axi4_0_w_bits_strb[2]
    DIRECTION OUTPUT TRISTATE ;
    USE SIGNAL ;
    ANTENNADIFFAREA 0.795200 ;
    PORT
      LAYER met2 ;
        RECT 2885.210 0.000 2885.490 4.000 ;
    END
  END mmio_axi4_0_w_bits_strb[2]
  PIN mmio_axi4_0_w_bits_strb[3]
    DIRECTION OUTPUT TRISTATE ;
    USE SIGNAL ;
    ANTENNADIFFAREA 0.795200 ;
    PORT
      LAYER met2 ;
        RECT 5319.530 2596.000 5319.810 2600.000 ;
    END
  END mmio_axi4_0_w_bits_strb[3]
  PIN mmio_axi4_0_w_bits_strb[4]
    DIRECTION OUTPUT TRISTATE ;
    USE SIGNAL ;
    ANTENNADIFFAREA 0.795200 ;
    PORT
      LAYER met2 ;
        RECT 5255.130 2596.000 5255.410 2600.000 ;
    END
  END mmio_axi4_0_w_bits_strb[4]
  PIN mmio_axi4_0_w_bits_strb[5]
    DIRECTION OUTPUT TRISTATE ;
    USE SIGNAL ;
    ANTENNADIFFAREA 0.795200 ;
    PORT
      LAYER met2 ;
        RECT 1864.470 2596.000 1864.750 2600.000 ;
    END
  END mmio_axi4_0_w_bits_strb[5]
  PIN mmio_axi4_0_w_bits_strb[6]
    DIRECTION OUTPUT TRISTATE ;
    USE SIGNAL ;
    ANTENNADIFFAREA 0.795200 ;
    PORT
      LAYER met2 ;
        RECT 2737.090 2596.000 2737.370 2600.000 ;
    END
  END mmio_axi4_0_w_bits_strb[6]
  PIN mmio_axi4_0_w_bits_strb[7]
    DIRECTION OUTPUT TRISTATE ;
    USE SIGNAL ;
    ANTENNADIFFAREA 0.795200 ;
    PORT
      LAYER met2 ;
        RECT 3422.950 0.000 3423.230 4.000 ;
    END
  END mmio_axi4_0_w_bits_strb[7]
  PIN mmio_axi4_0_w_ready
    DIRECTION INPUT ;
    USE SIGNAL ;
    ANTENNAGATEAREA 0.126000 ;
    PORT
      LAYER met3 ;
        RECT 0.000 1060.840 4.000 1061.440 ;
    END
  END mmio_axi4_0_w_ready
  PIN mmio_axi4_0_w_valid
    DIRECTION OUTPUT TRISTATE ;
    USE SIGNAL ;
    ANTENNADIFFAREA 0.795200 ;
    PORT
      LAYER met2 ;
        RECT 1426.550 2596.000 1426.830 2600.000 ;
    END
  END mmio_axi4_0_w_valid
  PIN reset
    DIRECTION INPUT ;
    USE SIGNAL ;
    ANTENNAGATEAREA 0.495000 ;
    PORT
      LAYER met3 ;
        RECT 6996.000 85.040 7000.000 85.640 ;
    END
  END reset
  OBS
      LAYER li1 ;
        RECT 20.240 21.675 6979.580 2578.645 ;
      LAYER met1 ;
        RECT 0.070 9.900 6997.450 2584.640 ;
      LAYER met2 ;
        RECT 0.100 2595.720 19.130 2596.650 ;
        RECT 19.970 2595.720 51.330 2596.650 ;
        RECT 52.170 2595.720 86.750 2596.650 ;
        RECT 87.590 2595.720 118.950 2596.650 ;
        RECT 119.790 2595.720 151.150 2596.650 ;
        RECT 151.990 2595.720 186.570 2596.650 ;
        RECT 187.410 2595.720 218.770 2596.650 ;
        RECT 219.610 2595.720 254.190 2596.650 ;
        RECT 255.030 2595.720 286.390 2596.650 ;
        RECT 287.230 2595.720 321.810 2596.650 ;
        RECT 322.650 2595.720 354.010 2596.650 ;
        RECT 354.850 2595.720 386.210 2596.650 ;
        RECT 387.050 2595.720 421.630 2596.650 ;
        RECT 422.470 2595.720 453.830 2596.650 ;
        RECT 454.670 2595.720 489.250 2596.650 ;
        RECT 490.090 2595.720 521.450 2596.650 ;
        RECT 522.290 2595.720 553.650 2596.650 ;
        RECT 554.490 2595.720 589.070 2596.650 ;
        RECT 589.910 2595.720 621.270 2596.650 ;
        RECT 622.110 2595.720 656.690 2596.650 ;
        RECT 657.530 2595.720 688.890 2596.650 ;
        RECT 689.730 2595.720 724.310 2596.650 ;
        RECT 725.150 2595.720 756.510 2596.650 ;
        RECT 757.350 2595.720 788.710 2596.650 ;
        RECT 789.550 2595.720 824.130 2596.650 ;
        RECT 824.970 2595.720 856.330 2596.650 ;
        RECT 857.170 2595.720 891.750 2596.650 ;
        RECT 892.590 2595.720 923.950 2596.650 ;
        RECT 924.790 2595.720 959.370 2596.650 ;
        RECT 960.210 2595.720 991.570 2596.650 ;
        RECT 992.410 2595.720 1023.770 2596.650 ;
        RECT 1024.610 2595.720 1059.190 2596.650 ;
        RECT 1060.030 2595.720 1091.390 2596.650 ;
        RECT 1092.230 2595.720 1126.810 2596.650 ;
        RECT 1127.650 2595.720 1159.010 2596.650 ;
        RECT 1159.850 2595.720 1191.210 2596.650 ;
        RECT 1192.050 2595.720 1226.630 2596.650 ;
        RECT 1227.470 2595.720 1258.830 2596.650 ;
        RECT 1259.670 2595.720 1294.250 2596.650 ;
        RECT 1295.090 2595.720 1326.450 2596.650 ;
        RECT 1327.290 2595.720 1361.870 2596.650 ;
        RECT 1362.710 2595.720 1394.070 2596.650 ;
        RECT 1394.910 2595.720 1426.270 2596.650 ;
        RECT 1427.110 2595.720 1461.690 2596.650 ;
        RECT 1462.530 2595.720 1493.890 2596.650 ;
        RECT 1494.730 2595.720 1529.310 2596.650 ;
        RECT 1530.150 2595.720 1561.510 2596.650 ;
        RECT 1562.350 2595.720 1596.930 2596.650 ;
        RECT 1597.770 2595.720 1629.130 2596.650 ;
        RECT 1629.970 2595.720 1661.330 2596.650 ;
        RECT 1662.170 2595.720 1696.750 2596.650 ;
        RECT 1697.590 2595.720 1728.950 2596.650 ;
        RECT 1729.790 2595.720 1764.370 2596.650 ;
        RECT 1765.210 2595.720 1796.570 2596.650 ;
        RECT 1797.410 2595.720 1831.990 2596.650 ;
        RECT 1832.830 2595.720 1864.190 2596.650 ;
        RECT 1865.030 2595.720 1896.390 2596.650 ;
        RECT 1897.230 2595.720 1931.810 2596.650 ;
        RECT 1932.650 2595.720 1964.010 2596.650 ;
        RECT 1964.850 2595.720 1999.430 2596.650 ;
        RECT 2000.270 2595.720 2031.630 2596.650 ;
        RECT 2032.470 2595.720 2063.830 2596.650 ;
        RECT 2064.670 2595.720 2099.250 2596.650 ;
        RECT 2100.090 2595.720 2131.450 2596.650 ;
        RECT 2132.290 2595.720 2166.870 2596.650 ;
        RECT 2167.710 2595.720 2199.070 2596.650 ;
        RECT 2199.910 2595.720 2234.490 2596.650 ;
        RECT 2235.330 2595.720 2266.690 2596.650 ;
        RECT 2267.530 2595.720 2298.890 2596.650 ;
        RECT 2299.730 2595.720 2334.310 2596.650 ;
        RECT 2335.150 2595.720 2366.510 2596.650 ;
        RECT 2367.350 2595.720 2401.930 2596.650 ;
        RECT 2402.770 2595.720 2434.130 2596.650 ;
        RECT 2434.970 2595.720 2469.550 2596.650 ;
        RECT 2470.390 2595.720 2501.750 2596.650 ;
        RECT 2502.590 2595.720 2533.950 2596.650 ;
        RECT 2534.790 2595.720 2569.370 2596.650 ;
        RECT 2570.210 2595.720 2601.570 2596.650 ;
        RECT 2602.410 2595.720 2636.990 2596.650 ;
        RECT 2637.830 2595.720 2669.190 2596.650 ;
        RECT 2670.030 2595.720 2701.390 2596.650 ;
        RECT 2702.230 2595.720 2736.810 2596.650 ;
        RECT 2737.650 2595.720 2769.010 2596.650 ;
        RECT 2769.850 2595.720 2804.430 2596.650 ;
        RECT 2805.270 2595.720 2836.630 2596.650 ;
        RECT 2837.470 2595.720 2872.050 2596.650 ;
        RECT 2872.890 2595.720 2904.250 2596.650 ;
        RECT 2905.090 2595.720 2936.450 2596.650 ;
        RECT 2937.290 2595.720 2971.870 2596.650 ;
        RECT 2972.710 2595.720 3004.070 2596.650 ;
        RECT 3004.910 2595.720 3039.490 2596.650 ;
        RECT 3040.330 2595.720 3071.690 2596.650 ;
        RECT 3072.530 2595.720 3107.110 2596.650 ;
        RECT 3107.950 2595.720 3139.310 2596.650 ;
        RECT 3140.150 2595.720 3171.510 2596.650 ;
        RECT 3172.350 2595.720 3206.930 2596.650 ;
        RECT 3207.770 2595.720 3239.130 2596.650 ;
        RECT 3239.970 2595.720 3274.550 2596.650 ;
        RECT 3275.390 2595.720 3306.750 2596.650 ;
        RECT 3307.590 2595.720 3342.170 2596.650 ;
        RECT 3343.010 2595.720 3374.370 2596.650 ;
        RECT 3375.210 2595.720 3406.570 2596.650 ;
        RECT 3407.410 2595.720 3441.990 2596.650 ;
        RECT 3442.830 2595.720 3474.190 2596.650 ;
        RECT 3475.030 2595.720 3509.610 2596.650 ;
        RECT 3510.450 2595.720 3541.810 2596.650 ;
        RECT 3542.650 2595.720 3574.010 2596.650 ;
        RECT 3574.850 2595.720 3609.430 2596.650 ;
        RECT 3610.270 2595.720 3641.630 2596.650 ;
        RECT 3642.470 2595.720 3677.050 2596.650 ;
        RECT 3677.890 2595.720 3709.250 2596.650 ;
        RECT 3710.090 2595.720 3744.670 2596.650 ;
        RECT 3745.510 2595.720 3776.870 2596.650 ;
        RECT 3777.710 2595.720 3809.070 2596.650 ;
        RECT 3809.910 2595.720 3844.490 2596.650 ;
        RECT 3845.330 2595.720 3876.690 2596.650 ;
        RECT 3877.530 2595.720 3912.110 2596.650 ;
        RECT 3912.950 2595.720 3944.310 2596.650 ;
        RECT 3945.150 2595.720 3979.730 2596.650 ;
        RECT 3980.570 2595.720 4011.930 2596.650 ;
        RECT 4012.770 2595.720 4044.130 2596.650 ;
        RECT 4044.970 2595.720 4079.550 2596.650 ;
        RECT 4080.390 2595.720 4111.750 2596.650 ;
        RECT 4112.590 2595.720 4147.170 2596.650 ;
        RECT 4148.010 2595.720 4179.370 2596.650 ;
        RECT 4180.210 2595.720 4211.570 2596.650 ;
        RECT 4212.410 2595.720 4246.990 2596.650 ;
        RECT 4247.830 2595.720 4279.190 2596.650 ;
        RECT 4280.030 2595.720 4314.610 2596.650 ;
        RECT 4315.450 2595.720 4346.810 2596.650 ;
        RECT 4347.650 2595.720 4382.230 2596.650 ;
        RECT 4383.070 2595.720 4414.430 2596.650 ;
        RECT 4415.270 2595.720 4446.630 2596.650 ;
        RECT 4447.470 2595.720 4482.050 2596.650 ;
        RECT 4482.890 2595.720 4514.250 2596.650 ;
        RECT 4515.090 2595.720 4549.670 2596.650 ;
        RECT 4550.510 2595.720 4581.870 2596.650 ;
        RECT 4582.710 2595.720 4617.290 2596.650 ;
        RECT 4618.130 2595.720 4649.490 2596.650 ;
        RECT 4650.330 2595.720 4681.690 2596.650 ;
        RECT 4682.530 2595.720 4717.110 2596.650 ;
        RECT 4717.950 2595.720 4749.310 2596.650 ;
        RECT 4750.150 2595.720 4784.730 2596.650 ;
        RECT 4785.570 2595.720 4816.930 2596.650 ;
        RECT 4817.770 2595.720 4849.130 2596.650 ;
        RECT 4849.970 2595.720 4884.550 2596.650 ;
        RECT 4885.390 2595.720 4916.750 2596.650 ;
        RECT 4917.590 2595.720 4952.170 2596.650 ;
        RECT 4953.010 2595.720 4984.370 2596.650 ;
        RECT 4985.210 2595.720 5019.790 2596.650 ;
        RECT 5020.630 2595.720 5051.990 2596.650 ;
        RECT 5052.830 2595.720 5084.190 2596.650 ;
        RECT 5085.030 2595.720 5119.610 2596.650 ;
        RECT 5120.450 2595.720 5151.810 2596.650 ;
        RECT 5152.650 2595.720 5187.230 2596.650 ;
        RECT 5188.070 2595.720 5219.430 2596.650 ;
        RECT 5220.270 2595.720 5254.850 2596.650 ;
        RECT 5255.690 2595.720 5287.050 2596.650 ;
        RECT 5287.890 2595.720 5319.250 2596.650 ;
        RECT 5320.090 2595.720 5354.670 2596.650 ;
        RECT 5355.510 2595.720 5386.870 2596.650 ;
        RECT 5387.710 2595.720 5422.290 2596.650 ;
        RECT 5423.130 2595.720 5454.490 2596.650 ;
        RECT 5455.330 2595.720 5489.910 2596.650 ;
        RECT 5490.750 2595.720 5522.110 2596.650 ;
        RECT 5522.950 2595.720 5554.310 2596.650 ;
        RECT 5555.150 2595.720 5589.730 2596.650 ;
        RECT 5590.570 2595.720 5621.930 2596.650 ;
        RECT 5622.770 2595.720 5657.350 2596.650 ;
        RECT 5658.190 2595.720 5689.550 2596.650 ;
        RECT 5690.390 2595.720 5721.750 2596.650 ;
        RECT 5722.590 2595.720 5757.170 2596.650 ;
        RECT 5758.010 2595.720 5789.370 2596.650 ;
        RECT 5790.210 2595.720 5824.790 2596.650 ;
        RECT 5825.630 2595.720 5856.990 2596.650 ;
        RECT 5857.830 2595.720 5892.410 2596.650 ;
        RECT 5893.250 2595.720 5924.610 2596.650 ;
        RECT 5925.450 2595.720 5956.810 2596.650 ;
        RECT 5957.650 2595.720 5992.230 2596.650 ;
        RECT 5993.070 2595.720 6024.430 2596.650 ;
        RECT 6025.270 2595.720 6059.850 2596.650 ;
        RECT 6060.690 2595.720 6092.050 2596.650 ;
        RECT 6092.890 2595.720 6127.470 2596.650 ;
        RECT 6128.310 2595.720 6159.670 2596.650 ;
        RECT 6160.510 2595.720 6191.870 2596.650 ;
        RECT 6192.710 2595.720 6227.290 2596.650 ;
        RECT 6228.130 2595.720 6259.490 2596.650 ;
        RECT 6260.330 2595.720 6294.910 2596.650 ;
        RECT 6295.750 2595.720 6327.110 2596.650 ;
        RECT 6327.950 2595.720 6359.310 2596.650 ;
        RECT 6360.150 2595.720 6394.730 2596.650 ;
        RECT 6395.570 2595.720 6426.930 2596.650 ;
        RECT 6427.770 2595.720 6462.350 2596.650 ;
        RECT 6463.190 2595.720 6494.550 2596.650 ;
        RECT 6495.390 2595.720 6529.970 2596.650 ;
        RECT 6530.810 2595.720 6562.170 2596.650 ;
        RECT 6563.010 2595.720 6594.370 2596.650 ;
        RECT 6595.210 2595.720 6629.790 2596.650 ;
        RECT 6630.630 2595.720 6661.990 2596.650 ;
        RECT 6662.830 2595.720 6697.410 2596.650 ;
        RECT 6698.250 2595.720 6729.610 2596.650 ;
        RECT 6730.450 2595.720 6765.030 2596.650 ;
        RECT 6765.870 2595.720 6797.230 2596.650 ;
        RECT 6798.070 2595.720 6829.430 2596.650 ;
        RECT 6830.270 2595.720 6864.850 2596.650 ;
        RECT 6865.690 2595.720 6897.050 2596.650 ;
        RECT 6897.890 2595.720 6932.470 2596.650 ;
        RECT 6933.310 2595.720 6964.670 2596.650 ;
        RECT 6965.510 2595.720 6996.870 2596.650 ;
        RECT 0.100 4.280 6997.420 2595.720 ;
        RECT 0.650 3.670 32.010 4.280 ;
        RECT 32.850 3.670 64.210 4.280 ;
        RECT 65.050 3.670 99.630 4.280 ;
        RECT 100.470 3.670 131.830 4.280 ;
        RECT 132.670 3.670 167.250 4.280 ;
        RECT 168.090 3.670 199.450 4.280 ;
        RECT 200.290 3.670 231.650 4.280 ;
        RECT 232.490 3.670 267.070 4.280 ;
        RECT 267.910 3.670 299.270 4.280 ;
        RECT 300.110 3.670 334.690 4.280 ;
        RECT 335.530 3.670 366.890 4.280 ;
        RECT 367.730 3.670 402.310 4.280 ;
        RECT 403.150 3.670 434.510 4.280 ;
        RECT 435.350 3.670 466.710 4.280 ;
        RECT 467.550 3.670 502.130 4.280 ;
        RECT 502.970 3.670 534.330 4.280 ;
        RECT 535.170 3.670 569.750 4.280 ;
        RECT 570.590 3.670 601.950 4.280 ;
        RECT 602.790 3.670 637.370 4.280 ;
        RECT 638.210 3.670 669.570 4.280 ;
        RECT 670.410 3.670 701.770 4.280 ;
        RECT 702.610 3.670 737.190 4.280 ;
        RECT 738.030 3.670 769.390 4.280 ;
        RECT 770.230 3.670 804.810 4.280 ;
        RECT 805.650 3.670 837.010 4.280 ;
        RECT 837.850 3.670 869.210 4.280 ;
        RECT 870.050 3.670 904.630 4.280 ;
        RECT 905.470 3.670 936.830 4.280 ;
        RECT 937.670 3.670 972.250 4.280 ;
        RECT 973.090 3.670 1004.450 4.280 ;
        RECT 1005.290 3.670 1039.870 4.280 ;
        RECT 1040.710 3.670 1072.070 4.280 ;
        RECT 1072.910 3.670 1104.270 4.280 ;
        RECT 1105.110 3.670 1139.690 4.280 ;
        RECT 1140.530 3.670 1171.890 4.280 ;
        RECT 1172.730 3.670 1207.310 4.280 ;
        RECT 1208.150 3.670 1239.510 4.280 ;
        RECT 1240.350 3.670 1274.930 4.280 ;
        RECT 1275.770 3.670 1307.130 4.280 ;
        RECT 1307.970 3.670 1339.330 4.280 ;
        RECT 1340.170 3.670 1374.750 4.280 ;
        RECT 1375.590 3.670 1406.950 4.280 ;
        RECT 1407.790 3.670 1442.370 4.280 ;
        RECT 1443.210 3.670 1474.570 4.280 ;
        RECT 1475.410 3.670 1506.770 4.280 ;
        RECT 1507.610 3.670 1542.190 4.280 ;
        RECT 1543.030 3.670 1574.390 4.280 ;
        RECT 1575.230 3.670 1609.810 4.280 ;
        RECT 1610.650 3.670 1642.010 4.280 ;
        RECT 1642.850 3.670 1677.430 4.280 ;
        RECT 1678.270 3.670 1709.630 4.280 ;
        RECT 1710.470 3.670 1741.830 4.280 ;
        RECT 1742.670 3.670 1777.250 4.280 ;
        RECT 1778.090 3.670 1809.450 4.280 ;
        RECT 1810.290 3.670 1844.870 4.280 ;
        RECT 1845.710 3.670 1877.070 4.280 ;
        RECT 1877.910 3.670 1912.490 4.280 ;
        RECT 1913.330 3.670 1944.690 4.280 ;
        RECT 1945.530 3.670 1976.890 4.280 ;
        RECT 1977.730 3.670 2012.310 4.280 ;
        RECT 2013.150 3.670 2044.510 4.280 ;
        RECT 2045.350 3.670 2079.930 4.280 ;
        RECT 2080.770 3.670 2112.130 4.280 ;
        RECT 2112.970 3.670 2147.550 4.280 ;
        RECT 2148.390 3.670 2179.750 4.280 ;
        RECT 2180.590 3.670 2211.950 4.280 ;
        RECT 2212.790 3.670 2247.370 4.280 ;
        RECT 2248.210 3.670 2279.570 4.280 ;
        RECT 2280.410 3.670 2314.990 4.280 ;
        RECT 2315.830 3.670 2347.190 4.280 ;
        RECT 2348.030 3.670 2379.390 4.280 ;
        RECT 2380.230 3.670 2414.810 4.280 ;
        RECT 2415.650 3.670 2447.010 4.280 ;
        RECT 2447.850 3.670 2482.430 4.280 ;
        RECT 2483.270 3.670 2514.630 4.280 ;
        RECT 2515.470 3.670 2550.050 4.280 ;
        RECT 2550.890 3.670 2582.250 4.280 ;
        RECT 2583.090 3.670 2614.450 4.280 ;
        RECT 2615.290 3.670 2649.870 4.280 ;
        RECT 2650.710 3.670 2682.070 4.280 ;
        RECT 2682.910 3.670 2717.490 4.280 ;
        RECT 2718.330 3.670 2749.690 4.280 ;
        RECT 2750.530 3.670 2785.110 4.280 ;
        RECT 2785.950 3.670 2817.310 4.280 ;
        RECT 2818.150 3.670 2849.510 4.280 ;
        RECT 2850.350 3.670 2884.930 4.280 ;
        RECT 2885.770 3.670 2917.130 4.280 ;
        RECT 2917.970 3.670 2952.550 4.280 ;
        RECT 2953.390 3.670 2984.750 4.280 ;
        RECT 2985.590 3.670 3016.950 4.280 ;
        RECT 3017.790 3.670 3052.370 4.280 ;
        RECT 3053.210 3.670 3084.570 4.280 ;
        RECT 3085.410 3.670 3119.990 4.280 ;
        RECT 3120.830 3.670 3152.190 4.280 ;
        RECT 3153.030 3.670 3187.610 4.280 ;
        RECT 3188.450 3.670 3219.810 4.280 ;
        RECT 3220.650 3.670 3252.010 4.280 ;
        RECT 3252.850 3.670 3287.430 4.280 ;
        RECT 3288.270 3.670 3319.630 4.280 ;
        RECT 3320.470 3.670 3355.050 4.280 ;
        RECT 3355.890 3.670 3387.250 4.280 ;
        RECT 3388.090 3.670 3422.670 4.280 ;
        RECT 3423.510 3.670 3454.870 4.280 ;
        RECT 3455.710 3.670 3487.070 4.280 ;
        RECT 3487.910 3.670 3522.490 4.280 ;
        RECT 3523.330 3.670 3554.690 4.280 ;
        RECT 3555.530 3.670 3590.110 4.280 ;
        RECT 3590.950 3.670 3622.310 4.280 ;
        RECT 3623.150 3.670 3654.510 4.280 ;
        RECT 3655.350 3.670 3689.930 4.280 ;
        RECT 3690.770 3.670 3722.130 4.280 ;
        RECT 3722.970 3.670 3757.550 4.280 ;
        RECT 3758.390 3.670 3789.750 4.280 ;
        RECT 3790.590 3.670 3825.170 4.280 ;
        RECT 3826.010 3.670 3857.370 4.280 ;
        RECT 3858.210 3.670 3889.570 4.280 ;
        RECT 3890.410 3.670 3924.990 4.280 ;
        RECT 3925.830 3.670 3957.190 4.280 ;
        RECT 3958.030 3.670 3992.610 4.280 ;
        RECT 3993.450 3.670 4024.810 4.280 ;
        RECT 4025.650 3.670 4060.230 4.280 ;
        RECT 4061.070 3.670 4092.430 4.280 ;
        RECT 4093.270 3.670 4124.630 4.280 ;
        RECT 4125.470 3.670 4160.050 4.280 ;
        RECT 4160.890 3.670 4192.250 4.280 ;
        RECT 4193.090 3.670 4227.670 4.280 ;
        RECT 4228.510 3.670 4259.870 4.280 ;
        RECT 4260.710 3.670 4295.290 4.280 ;
        RECT 4296.130 3.670 4327.490 4.280 ;
        RECT 4328.330 3.670 4359.690 4.280 ;
        RECT 4360.530 3.670 4395.110 4.280 ;
        RECT 4395.950 3.670 4427.310 4.280 ;
        RECT 4428.150 3.670 4462.730 4.280 ;
        RECT 4463.570 3.670 4494.930 4.280 ;
        RECT 4495.770 3.670 4527.130 4.280 ;
        RECT 4527.970 3.670 4562.550 4.280 ;
        RECT 4563.390 3.670 4594.750 4.280 ;
        RECT 4595.590 3.670 4630.170 4.280 ;
        RECT 4631.010 3.670 4662.370 4.280 ;
        RECT 4663.210 3.670 4697.790 4.280 ;
        RECT 4698.630 3.670 4729.990 4.280 ;
        RECT 4730.830 3.670 4762.190 4.280 ;
        RECT 4763.030 3.670 4797.610 4.280 ;
        RECT 4798.450 3.670 4829.810 4.280 ;
        RECT 4830.650 3.670 4865.230 4.280 ;
        RECT 4866.070 3.670 4897.430 4.280 ;
        RECT 4898.270 3.670 4932.850 4.280 ;
        RECT 4933.690 3.670 4965.050 4.280 ;
        RECT 4965.890 3.670 4997.250 4.280 ;
        RECT 4998.090 3.670 5032.670 4.280 ;
        RECT 5033.510 3.670 5064.870 4.280 ;
        RECT 5065.710 3.670 5100.290 4.280 ;
        RECT 5101.130 3.670 5132.490 4.280 ;
        RECT 5133.330 3.670 5164.690 4.280 ;
        RECT 5165.530 3.670 5200.110 4.280 ;
        RECT 5200.950 3.670 5232.310 4.280 ;
        RECT 5233.150 3.670 5267.730 4.280 ;
        RECT 5268.570 3.670 5299.930 4.280 ;
        RECT 5300.770 3.670 5335.350 4.280 ;
        RECT 5336.190 3.670 5367.550 4.280 ;
        RECT 5368.390 3.670 5399.750 4.280 ;
        RECT 5400.590 3.670 5435.170 4.280 ;
        RECT 5436.010 3.670 5467.370 4.280 ;
        RECT 5468.210 3.670 5502.790 4.280 ;
        RECT 5503.630 3.670 5534.990 4.280 ;
        RECT 5535.830 3.670 5570.410 4.280 ;
        RECT 5571.250 3.670 5602.610 4.280 ;
        RECT 5603.450 3.670 5634.810 4.280 ;
        RECT 5635.650 3.670 5670.230 4.280 ;
        RECT 5671.070 3.670 5702.430 4.280 ;
        RECT 5703.270 3.670 5737.850 4.280 ;
        RECT 5738.690 3.670 5770.050 4.280 ;
        RECT 5770.890 3.670 5805.470 4.280 ;
        RECT 5806.310 3.670 5837.670 4.280 ;
        RECT 5838.510 3.670 5869.870 4.280 ;
        RECT 5870.710 3.670 5905.290 4.280 ;
        RECT 5906.130 3.670 5937.490 4.280 ;
        RECT 5938.330 3.670 5972.910 4.280 ;
        RECT 5973.750 3.670 6005.110 4.280 ;
        RECT 6005.950 3.670 6037.310 4.280 ;
        RECT 6038.150 3.670 6072.730 4.280 ;
        RECT 6073.570 3.670 6104.930 4.280 ;
        RECT 6105.770 3.670 6140.350 4.280 ;
        RECT 6141.190 3.670 6172.550 4.280 ;
        RECT 6173.390 3.670 6207.970 4.280 ;
        RECT 6208.810 3.670 6240.170 4.280 ;
        RECT 6241.010 3.670 6272.370 4.280 ;
        RECT 6273.210 3.670 6307.790 4.280 ;
        RECT 6308.630 3.670 6339.990 4.280 ;
        RECT 6340.830 3.670 6375.410 4.280 ;
        RECT 6376.250 3.670 6407.610 4.280 ;
        RECT 6408.450 3.670 6443.030 4.280 ;
        RECT 6443.870 3.670 6475.230 4.280 ;
        RECT 6476.070 3.670 6507.430 4.280 ;
        RECT 6508.270 3.670 6542.850 4.280 ;
        RECT 6543.690 3.670 6575.050 4.280 ;
        RECT 6575.890 3.670 6610.470 4.280 ;
        RECT 6611.310 3.670 6642.670 4.280 ;
        RECT 6643.510 3.670 6674.870 4.280 ;
        RECT 6675.710 3.670 6710.290 4.280 ;
        RECT 6711.130 3.670 6742.490 4.280 ;
        RECT 6743.330 3.670 6777.910 4.280 ;
        RECT 6778.750 3.670 6810.110 4.280 ;
        RECT 6810.950 3.670 6845.530 4.280 ;
        RECT 6846.370 3.670 6877.730 4.280 ;
        RECT 6878.570 3.670 6909.930 4.280 ;
        RECT 6910.770 3.670 6945.350 4.280 ;
        RECT 6946.190 3.670 6977.550 4.280 ;
        RECT 6978.390 3.670 6997.420 4.280 ;
      LAYER met3 ;
        RECT 4.400 2583.640 6996.000 2584.490 ;
        RECT 4.000 2564.640 6996.000 2583.640 ;
        RECT 4.000 2563.240 6995.600 2564.640 ;
        RECT 4.000 2551.040 6996.000 2563.240 ;
        RECT 4.400 2549.640 6996.000 2551.040 ;
        RECT 4.000 2530.640 6996.000 2549.640 ;
        RECT 4.000 2529.240 6995.600 2530.640 ;
        RECT 4.000 2513.640 6996.000 2529.240 ;
        RECT 4.400 2512.240 6996.000 2513.640 ;
        RECT 4.000 2493.240 6996.000 2512.240 ;
        RECT 4.000 2491.840 6995.600 2493.240 ;
        RECT 4.000 2479.640 6996.000 2491.840 ;
        RECT 4.400 2478.240 6996.000 2479.640 ;
        RECT 4.000 2459.240 6996.000 2478.240 ;
        RECT 4.000 2457.840 6995.600 2459.240 ;
        RECT 4.000 2445.640 6996.000 2457.840 ;
        RECT 4.400 2444.240 6996.000 2445.640 ;
        RECT 4.000 2421.840 6996.000 2444.240 ;
        RECT 4.000 2420.440 6995.600 2421.840 ;
        RECT 4.000 2408.240 6996.000 2420.440 ;
        RECT 4.400 2406.840 6996.000 2408.240 ;
        RECT 4.000 2387.840 6996.000 2406.840 ;
        RECT 4.000 2386.440 6995.600 2387.840 ;
        RECT 4.000 2374.240 6996.000 2386.440 ;
        RECT 4.400 2372.840 6996.000 2374.240 ;
        RECT 4.000 2353.840 6996.000 2372.840 ;
        RECT 4.000 2352.440 6995.600 2353.840 ;
        RECT 4.000 2336.840 6996.000 2352.440 ;
        RECT 4.400 2335.440 6996.000 2336.840 ;
        RECT 4.000 2316.440 6996.000 2335.440 ;
        RECT 4.000 2315.040 6995.600 2316.440 ;
        RECT 4.000 2302.840 6996.000 2315.040 ;
        RECT 4.400 2301.440 6996.000 2302.840 ;
        RECT 4.000 2282.440 6996.000 2301.440 ;
        RECT 4.000 2281.040 6995.600 2282.440 ;
        RECT 4.000 2268.840 6996.000 2281.040 ;
        RECT 4.400 2267.440 6996.000 2268.840 ;
        RECT 4.000 2245.040 6996.000 2267.440 ;
        RECT 4.000 2243.640 6995.600 2245.040 ;
        RECT 4.000 2231.440 6996.000 2243.640 ;
        RECT 4.400 2230.040 6996.000 2231.440 ;
        RECT 4.000 2211.040 6996.000 2230.040 ;
        RECT 4.000 2209.640 6995.600 2211.040 ;
        RECT 4.000 2197.440 6996.000 2209.640 ;
        RECT 4.400 2196.040 6996.000 2197.440 ;
        RECT 4.000 2173.640 6996.000 2196.040 ;
        RECT 4.000 2172.240 6995.600 2173.640 ;
        RECT 4.000 2160.040 6996.000 2172.240 ;
        RECT 4.400 2158.640 6996.000 2160.040 ;
        RECT 4.000 2139.640 6996.000 2158.640 ;
        RECT 4.000 2138.240 6995.600 2139.640 ;
        RECT 4.000 2126.040 6996.000 2138.240 ;
        RECT 4.400 2124.640 6996.000 2126.040 ;
        RECT 4.000 2105.640 6996.000 2124.640 ;
        RECT 4.000 2104.240 6995.600 2105.640 ;
        RECT 4.000 2088.640 6996.000 2104.240 ;
        RECT 4.400 2087.240 6996.000 2088.640 ;
        RECT 4.000 2068.240 6996.000 2087.240 ;
        RECT 4.000 2066.840 6995.600 2068.240 ;
        RECT 4.000 2054.640 6996.000 2066.840 ;
        RECT 4.400 2053.240 6996.000 2054.640 ;
        RECT 4.000 2034.240 6996.000 2053.240 ;
        RECT 4.000 2032.840 6995.600 2034.240 ;
        RECT 4.000 2020.640 6996.000 2032.840 ;
        RECT 4.400 2019.240 6996.000 2020.640 ;
        RECT 4.000 1996.840 6996.000 2019.240 ;
        RECT 4.000 1995.440 6995.600 1996.840 ;
        RECT 4.000 1983.240 6996.000 1995.440 ;
        RECT 4.400 1981.840 6996.000 1983.240 ;
        RECT 4.000 1962.840 6996.000 1981.840 ;
        RECT 4.000 1961.440 6995.600 1962.840 ;
        RECT 4.000 1949.240 6996.000 1961.440 ;
        RECT 4.400 1947.840 6996.000 1949.240 ;
        RECT 4.000 1925.440 6996.000 1947.840 ;
        RECT 4.000 1924.040 6995.600 1925.440 ;
        RECT 4.000 1911.840 6996.000 1924.040 ;
        RECT 4.400 1910.440 6996.000 1911.840 ;
        RECT 4.000 1891.440 6996.000 1910.440 ;
        RECT 4.000 1890.040 6995.600 1891.440 ;
        RECT 4.000 1877.840 6996.000 1890.040 ;
        RECT 4.400 1876.440 6996.000 1877.840 ;
        RECT 4.000 1857.440 6996.000 1876.440 ;
        RECT 4.000 1856.040 6995.600 1857.440 ;
        RECT 4.000 1840.440 6996.000 1856.040 ;
        RECT 4.400 1839.040 6996.000 1840.440 ;
        RECT 4.000 1820.040 6996.000 1839.040 ;
        RECT 4.000 1818.640 6995.600 1820.040 ;
        RECT 4.000 1806.440 6996.000 1818.640 ;
        RECT 4.400 1805.040 6996.000 1806.440 ;
        RECT 4.000 1786.040 6996.000 1805.040 ;
        RECT 4.000 1784.640 6995.600 1786.040 ;
        RECT 4.000 1772.440 6996.000 1784.640 ;
        RECT 4.400 1771.040 6996.000 1772.440 ;
        RECT 4.000 1748.640 6996.000 1771.040 ;
        RECT 4.000 1747.240 6995.600 1748.640 ;
        RECT 4.000 1735.040 6996.000 1747.240 ;
        RECT 4.400 1733.640 6996.000 1735.040 ;
        RECT 4.000 1714.640 6996.000 1733.640 ;
        RECT 4.000 1713.240 6995.600 1714.640 ;
        RECT 4.000 1701.040 6996.000 1713.240 ;
        RECT 4.400 1699.640 6996.000 1701.040 ;
        RECT 4.000 1680.640 6996.000 1699.640 ;
        RECT 4.000 1679.240 6995.600 1680.640 ;
        RECT 4.000 1663.640 6996.000 1679.240 ;
        RECT 4.400 1662.240 6996.000 1663.640 ;
        RECT 4.000 1643.240 6996.000 1662.240 ;
        RECT 4.000 1641.840 6995.600 1643.240 ;
        RECT 4.000 1629.640 6996.000 1641.840 ;
        RECT 4.400 1628.240 6996.000 1629.640 ;
        RECT 4.000 1609.240 6996.000 1628.240 ;
        RECT 4.000 1607.840 6995.600 1609.240 ;
        RECT 4.000 1592.240 6996.000 1607.840 ;
        RECT 4.400 1590.840 6996.000 1592.240 ;
        RECT 4.000 1571.840 6996.000 1590.840 ;
        RECT 4.000 1570.440 6995.600 1571.840 ;
        RECT 4.000 1558.240 6996.000 1570.440 ;
        RECT 4.400 1556.840 6996.000 1558.240 ;
        RECT 4.000 1537.840 6996.000 1556.840 ;
        RECT 4.000 1536.440 6995.600 1537.840 ;
        RECT 4.000 1524.240 6996.000 1536.440 ;
        RECT 4.400 1522.840 6996.000 1524.240 ;
        RECT 4.000 1500.440 6996.000 1522.840 ;
        RECT 4.000 1499.040 6995.600 1500.440 ;
        RECT 4.000 1486.840 6996.000 1499.040 ;
        RECT 4.400 1485.440 6996.000 1486.840 ;
        RECT 4.000 1466.440 6996.000 1485.440 ;
        RECT 4.000 1465.040 6995.600 1466.440 ;
        RECT 4.000 1452.840 6996.000 1465.040 ;
        RECT 4.400 1451.440 6996.000 1452.840 ;
        RECT 4.000 1432.440 6996.000 1451.440 ;
        RECT 4.000 1431.040 6995.600 1432.440 ;
        RECT 4.000 1415.440 6996.000 1431.040 ;
        RECT 4.400 1414.040 6996.000 1415.440 ;
        RECT 4.000 1395.040 6996.000 1414.040 ;
        RECT 4.000 1393.640 6995.600 1395.040 ;
        RECT 4.000 1381.440 6996.000 1393.640 ;
        RECT 4.400 1380.040 6996.000 1381.440 ;
        RECT 4.000 1361.040 6996.000 1380.040 ;
        RECT 4.000 1359.640 6995.600 1361.040 ;
        RECT 4.000 1347.440 6996.000 1359.640 ;
        RECT 4.400 1346.040 6996.000 1347.440 ;
        RECT 4.000 1323.640 6996.000 1346.040 ;
        RECT 4.000 1322.240 6995.600 1323.640 ;
        RECT 4.000 1310.040 6996.000 1322.240 ;
        RECT 4.400 1308.640 6996.000 1310.040 ;
        RECT 4.000 1289.640 6996.000 1308.640 ;
        RECT 4.000 1288.240 6995.600 1289.640 ;
        RECT 4.000 1276.040 6996.000 1288.240 ;
        RECT 4.400 1274.640 6996.000 1276.040 ;
        RECT 4.000 1252.240 6996.000 1274.640 ;
        RECT 4.000 1250.840 6995.600 1252.240 ;
        RECT 4.000 1238.640 6996.000 1250.840 ;
        RECT 4.400 1237.240 6996.000 1238.640 ;
        RECT 4.000 1218.240 6996.000 1237.240 ;
        RECT 4.000 1216.840 6995.600 1218.240 ;
        RECT 4.000 1204.640 6996.000 1216.840 ;
        RECT 4.400 1203.240 6996.000 1204.640 ;
        RECT 4.000 1184.240 6996.000 1203.240 ;
        RECT 4.000 1182.840 6995.600 1184.240 ;
        RECT 4.000 1167.240 6996.000 1182.840 ;
        RECT 4.400 1165.840 6996.000 1167.240 ;
        RECT 4.000 1146.840 6996.000 1165.840 ;
        RECT 4.000 1145.440 6995.600 1146.840 ;
        RECT 4.000 1133.240 6996.000 1145.440 ;
        RECT 4.400 1131.840 6996.000 1133.240 ;
        RECT 4.000 1112.840 6996.000 1131.840 ;
        RECT 4.000 1111.440 6995.600 1112.840 ;
        RECT 4.000 1099.240 6996.000 1111.440 ;
        RECT 4.400 1097.840 6996.000 1099.240 ;
        RECT 4.000 1075.440 6996.000 1097.840 ;
        RECT 4.000 1074.040 6995.600 1075.440 ;
        RECT 4.000 1061.840 6996.000 1074.040 ;
        RECT 4.400 1060.440 6996.000 1061.840 ;
        RECT 4.000 1041.440 6996.000 1060.440 ;
        RECT 4.000 1040.040 6995.600 1041.440 ;
        RECT 4.000 1027.840 6996.000 1040.040 ;
        RECT 4.400 1026.440 6996.000 1027.840 ;
        RECT 4.000 1007.440 6996.000 1026.440 ;
        RECT 4.000 1006.040 6995.600 1007.440 ;
        RECT 4.000 990.440 6996.000 1006.040 ;
        RECT 4.400 989.040 6996.000 990.440 ;
        RECT 4.000 970.040 6996.000 989.040 ;
        RECT 4.000 968.640 6995.600 970.040 ;
        RECT 4.000 956.440 6996.000 968.640 ;
        RECT 4.400 955.040 6996.000 956.440 ;
        RECT 4.000 936.040 6996.000 955.040 ;
        RECT 4.000 934.640 6995.600 936.040 ;
        RECT 4.000 919.040 6996.000 934.640 ;
        RECT 4.400 917.640 6996.000 919.040 ;
        RECT 4.000 898.640 6996.000 917.640 ;
        RECT 4.000 897.240 6995.600 898.640 ;
        RECT 4.000 885.040 6996.000 897.240 ;
        RECT 4.400 883.640 6996.000 885.040 ;
        RECT 4.000 864.640 6996.000 883.640 ;
        RECT 4.000 863.240 6995.600 864.640 ;
        RECT 4.000 851.040 6996.000 863.240 ;
        RECT 4.400 849.640 6996.000 851.040 ;
        RECT 4.000 827.240 6996.000 849.640 ;
        RECT 4.000 825.840 6995.600 827.240 ;
        RECT 4.000 813.640 6996.000 825.840 ;
        RECT 4.400 812.240 6996.000 813.640 ;
        RECT 4.000 793.240 6996.000 812.240 ;
        RECT 4.000 791.840 6995.600 793.240 ;
        RECT 4.000 779.640 6996.000 791.840 ;
        RECT 4.400 778.240 6996.000 779.640 ;
        RECT 4.000 759.240 6996.000 778.240 ;
        RECT 4.000 757.840 6995.600 759.240 ;
        RECT 4.000 742.240 6996.000 757.840 ;
        RECT 4.400 740.840 6996.000 742.240 ;
        RECT 4.000 721.840 6996.000 740.840 ;
        RECT 4.000 720.440 6995.600 721.840 ;
        RECT 4.000 708.240 6996.000 720.440 ;
        RECT 4.400 706.840 6996.000 708.240 ;
        RECT 4.000 687.840 6996.000 706.840 ;
        RECT 4.000 686.440 6995.600 687.840 ;
        RECT 4.000 674.240 6996.000 686.440 ;
        RECT 4.400 672.840 6996.000 674.240 ;
        RECT 4.000 650.440 6996.000 672.840 ;
        RECT 4.000 649.040 6995.600 650.440 ;
        RECT 4.000 636.840 6996.000 649.040 ;
        RECT 4.400 635.440 6996.000 636.840 ;
        RECT 4.000 616.440 6996.000 635.440 ;
        RECT 4.000 615.040 6995.600 616.440 ;
        RECT 4.000 602.840 6996.000 615.040 ;
        RECT 4.400 601.440 6996.000 602.840 ;
        RECT 4.000 579.040 6996.000 601.440 ;
        RECT 4.000 577.640 6995.600 579.040 ;
        RECT 4.000 565.440 6996.000 577.640 ;
        RECT 4.400 564.040 6996.000 565.440 ;
        RECT 4.000 545.040 6996.000 564.040 ;
        RECT 4.000 543.640 6995.600 545.040 ;
        RECT 4.000 531.440 6996.000 543.640 ;
        RECT 4.400 530.040 6996.000 531.440 ;
        RECT 4.000 511.040 6996.000 530.040 ;
        RECT 4.000 509.640 6995.600 511.040 ;
        RECT 4.000 494.040 6996.000 509.640 ;
        RECT 4.400 492.640 6996.000 494.040 ;
        RECT 4.000 473.640 6996.000 492.640 ;
        RECT 4.000 472.240 6995.600 473.640 ;
        RECT 4.000 460.040 6996.000 472.240 ;
        RECT 4.400 458.640 6996.000 460.040 ;
        RECT 4.000 439.640 6996.000 458.640 ;
        RECT 4.000 438.240 6995.600 439.640 ;
        RECT 4.000 426.040 6996.000 438.240 ;
        RECT 4.400 424.640 6996.000 426.040 ;
        RECT 4.000 402.240 6996.000 424.640 ;
        RECT 4.000 400.840 6995.600 402.240 ;
        RECT 4.000 388.640 6996.000 400.840 ;
        RECT 4.400 387.240 6996.000 388.640 ;
        RECT 4.000 368.240 6996.000 387.240 ;
        RECT 4.000 366.840 6995.600 368.240 ;
        RECT 4.000 354.640 6996.000 366.840 ;
        RECT 4.400 353.240 6996.000 354.640 ;
        RECT 4.000 330.840 6996.000 353.240 ;
        RECT 4.000 329.440 6995.600 330.840 ;
        RECT 4.000 317.240 6996.000 329.440 ;
        RECT 4.400 315.840 6996.000 317.240 ;
        RECT 4.000 296.840 6996.000 315.840 ;
        RECT 4.000 295.440 6995.600 296.840 ;
        RECT 4.000 283.240 6996.000 295.440 ;
        RECT 4.400 281.840 6996.000 283.240 ;
        RECT 4.000 262.840 6996.000 281.840 ;
        RECT 4.000 261.440 6995.600 262.840 ;
        RECT 4.000 245.840 6996.000 261.440 ;
        RECT 4.400 244.440 6996.000 245.840 ;
        RECT 4.000 225.440 6996.000 244.440 ;
        RECT 4.000 224.040 6995.600 225.440 ;
        RECT 4.000 211.840 6996.000 224.040 ;
        RECT 4.400 210.440 6996.000 211.840 ;
        RECT 4.000 191.440 6996.000 210.440 ;
        RECT 4.000 190.040 6995.600 191.440 ;
        RECT 4.000 177.840 6996.000 190.040 ;
        RECT 4.400 176.440 6996.000 177.840 ;
        RECT 4.000 154.040 6996.000 176.440 ;
        RECT 4.000 152.640 6995.600 154.040 ;
        RECT 4.000 140.440 6996.000 152.640 ;
        RECT 4.400 139.040 6996.000 140.440 ;
        RECT 4.000 120.040 6996.000 139.040 ;
        RECT 4.000 118.640 6995.600 120.040 ;
        RECT 4.000 106.440 6996.000 118.640 ;
        RECT 4.400 105.040 6996.000 106.440 ;
        RECT 4.000 86.040 6996.000 105.040 ;
        RECT 4.000 84.640 6995.600 86.040 ;
        RECT 4.000 69.040 6996.000 84.640 ;
        RECT 4.400 67.640 6996.000 69.040 ;
        RECT 4.000 48.640 6996.000 67.640 ;
        RECT 4.000 47.240 6995.600 48.640 ;
        RECT 4.000 35.040 6996.000 47.240 ;
        RECT 4.400 33.640 6996.000 35.040 ;
        RECT 4.000 14.640 6996.000 33.640 ;
        RECT 4.000 13.240 6995.600 14.640 ;
        RECT 4.000 11.055 6996.000 13.240 ;
      LAYER met4 ;
        RECT 16.855 2579.200 6965.450 2579.745 ;
        RECT 16.855 21.120 35.360 2579.200 ;
        RECT 37.760 21.120 38.660 2579.200 ;
        RECT 41.060 2509.120 215.360 2579.200 ;
        RECT 217.760 2509.120 218.660 2579.200 ;
        RECT 221.060 2509.120 395.360 2579.200 ;
        RECT 397.760 2509.120 398.660 2579.200 ;
        RECT 401.060 2509.120 575.360 2579.200 ;
        RECT 577.760 2509.740 578.660 2579.200 ;
        RECT 581.060 2509.740 755.360 2579.200 ;
        RECT 577.760 2509.120 755.360 2509.740 ;
        RECT 757.760 2509.120 758.660 2579.200 ;
        RECT 761.060 2513.920 935.360 2579.200 ;
        RECT 761.060 2509.120 864.980 2513.920 ;
        RECT 41.060 2073.420 864.980 2509.120 ;
        RECT 41.060 2072.800 398.660 2073.420 ;
        RECT 41.060 526.740 215.360 2072.800 ;
        RECT 217.760 526.740 218.660 2072.800 ;
        RECT 221.060 526.740 395.360 2072.800 ;
        RECT 397.760 526.740 398.660 2072.800 ;
        RECT 41.060 526.120 398.660 526.740 ;
        RECT 401.060 526.120 575.360 2073.420 ;
        RECT 577.760 2072.800 755.360 2073.420 ;
        RECT 577.760 526.740 578.660 2072.800 ;
        RECT 581.060 526.740 755.360 2072.800 ;
        RECT 577.760 526.120 755.360 526.740 ;
        RECT 757.760 526.120 758.660 2073.420 ;
        RECT 761.060 2072.000 864.980 2073.420 ;
        RECT 867.380 2072.000 935.360 2513.920 ;
        RECT 761.060 528.320 935.360 2072.000 ;
        RECT 761.060 526.120 864.980 528.320 ;
        RECT 41.060 90.420 864.980 526.120 ;
        RECT 41.060 21.120 215.360 90.420 ;
        RECT 217.760 21.120 218.660 90.420 ;
        RECT 221.060 21.120 395.360 90.420 ;
        RECT 397.760 21.120 398.660 90.420 ;
        RECT 401.060 21.120 575.360 90.420 ;
        RECT 577.760 89.800 755.360 90.420 ;
        RECT 577.760 21.120 578.660 89.800 ;
        RECT 581.060 21.120 755.360 89.800 ;
        RECT 757.760 21.120 758.660 90.420 ;
        RECT 761.060 86.400 864.980 90.420 ;
        RECT 867.380 86.400 935.360 528.320 ;
        RECT 761.060 21.120 935.360 86.400 ;
        RECT 937.760 2509.120 938.660 2579.200 ;
        RECT 941.060 2509.740 1115.360 2579.200 ;
        RECT 1117.760 2509.740 1118.660 2579.200 ;
        RECT 941.060 2509.120 1118.660 2509.740 ;
        RECT 1121.060 2509.120 1295.360 2579.200 ;
        RECT 1297.760 2509.120 1298.660 2579.200 ;
        RECT 1301.060 2509.120 1475.360 2579.200 ;
        RECT 1477.760 2509.740 1478.660 2579.200 ;
        RECT 1481.060 2509.740 1655.360 2579.200 ;
        RECT 1477.760 2509.120 1655.360 2509.740 ;
        RECT 937.760 2073.420 1655.360 2509.120 ;
        RECT 937.760 526.120 938.660 2073.420 ;
        RECT 941.060 2072.800 1118.660 2073.420 ;
        RECT 941.060 526.740 1115.360 2072.800 ;
        RECT 1117.760 526.740 1118.660 2072.800 ;
        RECT 941.060 526.120 1118.660 526.740 ;
        RECT 1121.060 526.120 1295.360 2073.420 ;
        RECT 1297.760 526.120 1298.660 2073.420 ;
        RECT 1301.060 526.120 1475.360 2073.420 ;
        RECT 1477.760 2072.800 1655.360 2073.420 ;
        RECT 1477.760 526.740 1478.660 2072.800 ;
        RECT 1481.060 526.740 1655.360 2072.800 ;
        RECT 1477.760 526.120 1655.360 526.740 ;
        RECT 937.760 90.420 1655.360 526.120 ;
        RECT 937.760 21.120 938.660 90.420 ;
        RECT 941.060 89.800 1118.660 90.420 ;
        RECT 941.060 21.120 1115.360 89.800 ;
        RECT 1117.760 21.120 1118.660 89.800 ;
        RECT 1121.060 21.120 1295.360 90.420 ;
        RECT 1297.760 21.120 1298.660 90.420 ;
        RECT 1301.060 21.120 1475.360 90.420 ;
        RECT 1477.760 89.800 1655.360 90.420 ;
        RECT 1477.760 21.120 1478.660 89.800 ;
        RECT 1481.060 21.120 1655.360 89.800 ;
        RECT 1657.760 21.120 1658.660 2579.200 ;
        RECT 1661.060 2509.120 1835.360 2579.200 ;
        RECT 1837.760 2509.120 1838.660 2579.200 ;
        RECT 1841.060 2509.740 2015.360 2579.200 ;
        RECT 2017.760 2509.740 2018.660 2579.200 ;
        RECT 1841.060 2509.120 2018.660 2509.740 ;
        RECT 2021.060 2509.120 2195.360 2579.200 ;
        RECT 2197.760 2509.120 2198.660 2579.200 ;
        RECT 2201.060 2509.120 2375.360 2579.200 ;
        RECT 2377.760 2509.120 2378.660 2579.200 ;
        RECT 2381.060 2509.120 2555.360 2579.200 ;
        RECT 1661.060 2073.420 2555.360 2509.120 ;
        RECT 1661.060 526.120 1835.360 2073.420 ;
        RECT 1837.760 526.120 1838.660 2073.420 ;
        RECT 1841.060 2072.800 2195.360 2073.420 ;
        RECT 1841.060 526.740 2015.360 2072.800 ;
        RECT 2017.760 526.740 2018.660 2072.800 ;
        RECT 2021.060 526.740 2195.360 2072.800 ;
        RECT 1841.060 526.120 2195.360 526.740 ;
        RECT 2197.760 526.120 2198.660 2073.420 ;
        RECT 2201.060 526.120 2375.360 2073.420 ;
        RECT 2377.760 526.120 2378.660 2073.420 ;
        RECT 2381.060 526.120 2555.360 2073.420 ;
        RECT 1661.060 90.420 2555.360 526.120 ;
        RECT 1661.060 21.120 1835.360 90.420 ;
        RECT 1837.760 21.120 1838.660 90.420 ;
        RECT 1841.060 89.800 2018.660 90.420 ;
        RECT 1841.060 21.120 2015.360 89.800 ;
        RECT 2017.760 21.120 2018.660 89.800 ;
        RECT 2021.060 21.120 2195.360 90.420 ;
        RECT 2197.760 21.120 2198.660 90.420 ;
        RECT 2201.060 21.120 2375.360 90.420 ;
        RECT 2377.760 21.120 2378.660 90.420 ;
        RECT 2381.060 21.120 2555.360 90.420 ;
        RECT 2557.760 21.120 2558.660 2579.200 ;
        RECT 2561.060 2509.120 2735.360 2579.200 ;
        RECT 2737.760 2509.120 2738.660 2579.200 ;
        RECT 2741.060 2509.740 2915.360 2579.200 ;
        RECT 2917.760 2509.740 2918.660 2579.200 ;
        RECT 2741.060 2509.120 2918.660 2509.740 ;
        RECT 2921.060 2509.120 3095.360 2579.200 ;
        RECT 3097.760 2509.120 3098.660 2579.200 ;
        RECT 3101.060 2509.120 3275.360 2579.200 ;
        RECT 3277.760 2509.120 3278.660 2579.200 ;
        RECT 3281.060 2509.120 3455.360 2579.200 ;
        RECT 2561.060 2073.420 3455.360 2509.120 ;
        RECT 2561.060 2072.800 2918.660 2073.420 ;
        RECT 2561.060 526.740 2735.360 2072.800 ;
        RECT 2737.760 526.740 2738.660 2072.800 ;
        RECT 2741.060 526.740 2915.360 2072.800 ;
        RECT 2917.760 526.740 2918.660 2072.800 ;
        RECT 2561.060 526.120 2918.660 526.740 ;
        RECT 2921.060 526.120 3095.360 2073.420 ;
        RECT 3097.760 526.120 3098.660 2073.420 ;
        RECT 3101.060 526.120 3275.360 2073.420 ;
        RECT 3277.760 526.120 3278.660 2073.420 ;
        RECT 3281.060 526.120 3455.360 2073.420 ;
        RECT 2561.060 90.420 3455.360 526.120 ;
        RECT 2561.060 21.120 2735.360 90.420 ;
        RECT 2737.760 21.120 2738.660 90.420 ;
        RECT 2741.060 89.800 2918.660 90.420 ;
        RECT 2741.060 21.120 2915.360 89.800 ;
        RECT 2917.760 21.120 2918.660 89.800 ;
        RECT 2921.060 21.120 3095.360 90.420 ;
        RECT 3097.760 21.120 3098.660 90.420 ;
        RECT 3101.060 21.120 3275.360 90.420 ;
        RECT 3277.760 21.120 3278.660 90.420 ;
        RECT 3281.060 21.120 3455.360 90.420 ;
        RECT 3457.760 21.120 3458.660 2579.200 ;
        RECT 3461.060 2509.120 3635.360 2579.200 ;
        RECT 3637.760 2509.120 3638.660 2579.200 ;
        RECT 3641.060 2509.120 3815.360 2579.200 ;
        RECT 3817.760 2509.740 3818.660 2579.200 ;
        RECT 3821.060 2509.740 3995.360 2579.200 ;
        RECT 3817.760 2509.120 3995.360 2509.740 ;
        RECT 3997.760 2509.120 3998.660 2579.200 ;
        RECT 4001.060 2509.120 4175.360 2579.200 ;
        RECT 4177.760 2509.120 4178.660 2579.200 ;
        RECT 4181.060 2513.920 4355.360 2579.200 ;
        RECT 4181.060 2509.120 4263.460 2513.920 ;
        RECT 3461.060 2073.420 4263.460 2509.120 ;
        RECT 3461.060 526.120 3635.360 2073.420 ;
        RECT 3637.760 526.120 3638.660 2073.420 ;
        RECT 3641.060 2072.800 3818.660 2073.420 ;
        RECT 3641.060 526.740 3815.360 2072.800 ;
        RECT 3817.760 526.740 3818.660 2072.800 ;
        RECT 3641.060 526.120 3818.660 526.740 ;
        RECT 3821.060 526.120 3995.360 2073.420 ;
        RECT 3997.760 526.120 3998.660 2073.420 ;
        RECT 4001.060 526.120 4175.360 2073.420 ;
        RECT 4177.760 526.120 4178.660 2073.420 ;
        RECT 4181.060 2069.280 4263.460 2073.420 ;
        RECT 4265.860 2069.280 4267.140 2513.920 ;
        RECT 4269.540 2509.120 4355.360 2513.920 ;
        RECT 4357.760 2509.120 4358.660 2579.200 ;
        RECT 4361.060 2509.120 4535.360 2579.200 ;
        RECT 4537.760 2509.120 4538.660 2579.200 ;
        RECT 4541.060 2509.740 4715.360 2579.200 ;
        RECT 4717.760 2509.740 4718.660 2579.200 ;
        RECT 4541.060 2509.120 4718.660 2509.740 ;
        RECT 4721.060 2509.120 4895.360 2579.200 ;
        RECT 4897.760 2509.120 4898.660 2579.200 ;
        RECT 4901.060 2509.120 5075.360 2579.200 ;
        RECT 4269.540 2073.420 5075.360 2509.120 ;
        RECT 4269.540 2069.280 4355.360 2073.420 ;
        RECT 4181.060 531.040 4355.360 2069.280 ;
        RECT 4181.060 526.120 4263.460 531.040 ;
        RECT 3461.060 90.420 4263.460 526.120 ;
        RECT 3461.060 21.120 3635.360 90.420 ;
        RECT 3637.760 21.120 3638.660 90.420 ;
        RECT 3641.060 21.120 3815.360 90.420 ;
        RECT 3817.760 89.800 3995.360 90.420 ;
        RECT 3817.760 21.120 3818.660 89.800 ;
        RECT 3821.060 21.120 3995.360 89.800 ;
        RECT 3997.760 21.120 3998.660 90.420 ;
        RECT 4001.060 21.120 4175.360 90.420 ;
        RECT 4177.760 21.120 4178.660 90.420 ;
        RECT 4181.060 86.400 4263.460 90.420 ;
        RECT 4265.860 86.400 4267.140 531.040 ;
        RECT 4269.540 526.120 4355.360 531.040 ;
        RECT 4357.760 526.120 4358.660 2073.420 ;
        RECT 4361.060 2072.800 4718.660 2073.420 ;
        RECT 4361.060 526.740 4535.360 2072.800 ;
        RECT 4537.760 526.740 4538.660 2072.800 ;
        RECT 4541.060 526.740 4715.360 2072.800 ;
        RECT 4717.760 526.740 4718.660 2072.800 ;
        RECT 4361.060 526.120 4718.660 526.740 ;
        RECT 4721.060 526.120 4895.360 2073.420 ;
        RECT 4897.760 526.120 4898.660 2073.420 ;
        RECT 4901.060 526.120 5075.360 2073.420 ;
        RECT 4269.540 90.420 5075.360 526.120 ;
        RECT 4269.540 86.400 4355.360 90.420 ;
        RECT 4181.060 21.120 4355.360 86.400 ;
        RECT 4357.760 21.120 4358.660 90.420 ;
        RECT 4361.060 21.120 4535.360 90.420 ;
        RECT 4537.760 21.120 4538.660 90.420 ;
        RECT 4541.060 89.800 4718.660 90.420 ;
        RECT 4541.060 21.120 4715.360 89.800 ;
        RECT 4717.760 21.120 4718.660 89.800 ;
        RECT 4721.060 21.120 4895.360 90.420 ;
        RECT 4897.760 21.120 4898.660 90.420 ;
        RECT 4901.060 21.120 5075.360 90.420 ;
        RECT 5077.760 21.120 5078.660 2579.200 ;
        RECT 5081.060 2509.120 5255.360 2579.200 ;
        RECT 5257.760 2509.120 5258.660 2579.200 ;
        RECT 5261.060 2509.120 5435.360 2579.200 ;
        RECT 5437.760 2509.120 5438.660 2579.200 ;
        RECT 5441.060 2509.740 5615.360 2579.200 ;
        RECT 5617.760 2509.740 5618.660 2579.200 ;
        RECT 5441.060 2509.120 5618.660 2509.740 ;
        RECT 5621.060 2509.120 5795.360 2579.200 ;
        RECT 5797.760 2509.740 5798.660 2579.200 ;
        RECT 5801.060 2509.740 5975.360 2579.200 ;
        RECT 5797.760 2509.120 5975.360 2509.740 ;
        RECT 5081.060 2073.420 5975.360 2509.120 ;
        RECT 5081.060 526.120 5255.360 2073.420 ;
        RECT 5257.760 526.120 5258.660 2073.420 ;
        RECT 5261.060 526.120 5435.360 2073.420 ;
        RECT 5437.760 526.120 5438.660 2073.420 ;
        RECT 5441.060 2072.800 5618.660 2073.420 ;
        RECT 5441.060 526.740 5615.360 2072.800 ;
        RECT 5617.760 526.740 5618.660 2072.800 ;
        RECT 5441.060 526.120 5618.660 526.740 ;
        RECT 5621.060 526.120 5795.360 2073.420 ;
        RECT 5797.760 526.120 5798.660 2073.420 ;
        RECT 5801.060 526.120 5975.360 2073.420 ;
        RECT 5081.060 90.420 5975.360 526.120 ;
        RECT 5081.060 21.120 5255.360 90.420 ;
        RECT 5257.760 21.120 5258.660 90.420 ;
        RECT 5261.060 21.120 5435.360 90.420 ;
        RECT 5437.760 21.120 5438.660 90.420 ;
        RECT 5441.060 89.800 5618.660 90.420 ;
        RECT 5441.060 21.120 5615.360 89.800 ;
        RECT 5617.760 21.120 5618.660 89.800 ;
        RECT 5621.060 21.120 5795.360 90.420 ;
        RECT 5797.760 89.800 5975.360 90.420 ;
        RECT 5797.760 21.120 5798.660 89.800 ;
        RECT 5801.060 21.120 5975.360 89.800 ;
        RECT 5977.760 21.120 5978.660 2579.200 ;
        RECT 5981.060 2509.120 6155.360 2579.200 ;
        RECT 6157.760 2509.120 6158.660 2579.200 ;
        RECT 6161.060 2509.120 6335.360 2579.200 ;
        RECT 6337.760 2509.120 6338.660 2579.200 ;
        RECT 6341.060 2509.740 6515.360 2579.200 ;
        RECT 6517.760 2509.740 6518.660 2579.200 ;
        RECT 6341.060 2509.120 6518.660 2509.740 ;
        RECT 6521.060 2509.120 6695.360 2579.200 ;
        RECT 6697.760 2509.120 6698.660 2579.200 ;
        RECT 6701.060 2509.120 6875.360 2579.200 ;
        RECT 5981.060 2073.420 6875.360 2509.120 ;
        RECT 5981.060 526.120 6155.360 2073.420 ;
        RECT 6157.760 2072.800 6518.660 2073.420 ;
        RECT 6157.760 526.740 6158.660 2072.800 ;
        RECT 6161.060 526.740 6335.360 2072.800 ;
        RECT 6337.760 526.740 6338.660 2072.800 ;
        RECT 6341.060 526.740 6515.360 2072.800 ;
        RECT 6517.760 526.740 6518.660 2072.800 ;
        RECT 6157.760 526.120 6518.660 526.740 ;
        RECT 6521.060 526.120 6695.360 2073.420 ;
        RECT 6697.760 526.120 6698.660 2073.420 ;
        RECT 6701.060 526.120 6875.360 2073.420 ;
        RECT 5981.060 90.420 6875.360 526.120 ;
        RECT 5981.060 21.120 6155.360 90.420 ;
        RECT 6157.760 21.120 6158.660 90.420 ;
        RECT 6161.060 21.120 6335.360 90.420 ;
        RECT 6337.760 21.120 6338.660 90.420 ;
        RECT 6341.060 89.800 6518.660 90.420 ;
        RECT 6341.060 21.120 6515.360 89.800 ;
        RECT 6517.760 21.120 6518.660 89.800 ;
        RECT 6521.060 21.120 6695.360 90.420 ;
        RECT 6697.760 21.120 6698.660 90.420 ;
        RECT 6701.060 21.120 6875.360 90.420 ;
        RECT 6877.760 21.120 6878.660 2579.200 ;
        RECT 6881.060 21.120 6965.450 2579.200 ;
        RECT 16.855 11.055 6965.450 21.120 ;
      LAYER met5 ;
        RECT 32.780 2204.110 6965.660 2355.300 ;
        RECT 32.780 2024.110 6965.660 2196.010 ;
        RECT 32.780 1844.110 6965.660 2016.010 ;
        RECT 32.780 1664.110 6965.660 1836.010 ;
        RECT 32.780 1484.110 6965.660 1656.010 ;
        RECT 32.780 1304.110 6965.660 1476.010 ;
        RECT 32.780 1124.110 6965.660 1296.010 ;
        RECT 32.780 944.110 6965.660 1116.010 ;
        RECT 32.780 764.110 6965.660 936.010 ;
        RECT 32.780 584.110 6965.660 756.010 ;
        RECT 32.780 404.110 6965.660 576.010 ;
        RECT 32.780 224.110 6965.660 396.010 ;
        RECT 32.780 45.100 6965.660 216.010 ;
  END
END RocketAXITileTop
END LIBRARY

